VERSION 5.7 ;
  NOWIREEXTENSIONATPIN ON ;
  DIVIDERCHAR "/" ;
  BUSBITCHARS "[]" ;
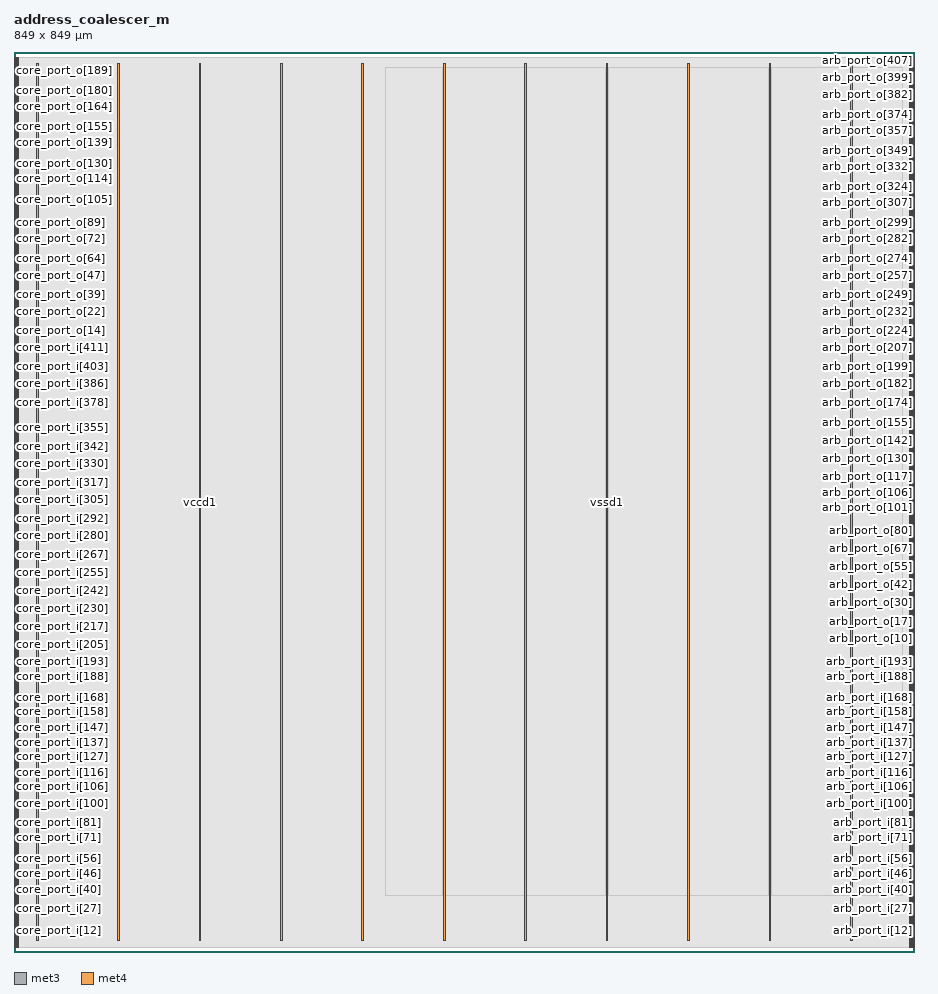
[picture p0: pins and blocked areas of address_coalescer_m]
MACRO address_coalescer_m
  CLASS BLOCK ;
  FOREIGN address_coalescer_m ;
  ORIGIN 0.000 0.000 ;
  SIZE 849.000 BY 849.000 ;
  PIN arb_port_i[0]
    DIRECTION INPUT ;
    USE SIGNAL ;
    ANTENNAGATEAREA 0.852000 ;
    PORT
      LAYER met3 ;
        RECT 845.000 4.120 849.000 4.720 ;
    END
  END arb_port_i[0]
  PIN arb_port_i[100]
    DIRECTION INPUT ;
    USE SIGNAL ;
    ANTENNAGATEAREA 0.426000 ;
    PORT
      LAYER met3 ;
        RECT 845.000 140.120 849.000 140.720 ;
    END
  END arb_port_i[100]
  PIN arb_port_i[101]
    DIRECTION INPUT ;
    USE SIGNAL ;
    ANTENNAGATEAREA 0.426000 ;
    PORT
      LAYER met3 ;
        RECT 845.000 141.480 849.000 142.080 ;
    END
  END arb_port_i[101]
  PIN arb_port_i[102]
    DIRECTION INPUT ;
    USE SIGNAL ;
    ANTENNAGATEAREA 0.426000 ;
    PORT
      LAYER met3 ;
        RECT 845.000 142.840 849.000 143.440 ;
    END
  END arb_port_i[102]
  PIN arb_port_i[103]
    DIRECTION INPUT ;
    USE SIGNAL ;
    ANTENNAGATEAREA 0.426000 ;
    PORT
      LAYER met3 ;
        RECT 845.000 144.200 849.000 144.800 ;
    END
  END arb_port_i[103]
  PIN arb_port_i[104]
    DIRECTION INPUT ;
    USE SIGNAL ;
    ANTENNAGATEAREA 0.426000 ;
    PORT
      LAYER met3 ;
        RECT 845.000 145.560 849.000 146.160 ;
    END
  END arb_port_i[104]
  PIN arb_port_i[105]
    DIRECTION INPUT ;
    USE SIGNAL ;
    ANTENNAGATEAREA 0.426000 ;
    PORT
      LAYER met3 ;
        RECT 845.000 146.920 849.000 147.520 ;
    END
  END arb_port_i[105]
  PIN arb_port_i[106]
    DIRECTION INPUT ;
    USE SIGNAL ;
    ANTENNAGATEAREA 0.426000 ;
    PORT
      LAYER met3 ;
        RECT 845.000 148.280 849.000 148.880 ;
    END
  END arb_port_i[106]
  PIN arb_port_i[107]
    DIRECTION INPUT ;
    USE SIGNAL ;
    ANTENNAGATEAREA 0.426000 ;
    PORT
      LAYER met3 ;
        RECT 845.000 149.640 849.000 150.240 ;
    END
  END arb_port_i[107]
  PIN arb_port_i[108]
    DIRECTION INPUT ;
    USE SIGNAL ;
    ANTENNAGATEAREA 0.426000 ;
    PORT
      LAYER met3 ;
        RECT 845.000 151.000 849.000 151.600 ;
    END
  END arb_port_i[108]
  PIN arb_port_i[109]
    DIRECTION INPUT ;
    USE SIGNAL ;
    ANTENNAGATEAREA 0.426000 ;
    PORT
      LAYER met3 ;
        RECT 845.000 152.360 849.000 152.960 ;
    END
  END arb_port_i[109]
  PIN arb_port_i[10]
    DIRECTION INPUT ;
    USE SIGNAL ;
    ANTENNAGATEAREA 0.852000 ;
    PORT
      LAYER met3 ;
        RECT 845.000 17.720 849.000 18.320 ;
    END
  END arb_port_i[10]
  PIN arb_port_i[110]
    DIRECTION INPUT ;
    USE SIGNAL ;
    ANTENNAGATEAREA 0.426000 ;
    PORT
      LAYER met3 ;
        RECT 845.000 153.720 849.000 154.320 ;
    END
  END arb_port_i[110]
  PIN arb_port_i[111]
    DIRECTION INPUT ;
    USE SIGNAL ;
    ANTENNAGATEAREA 0.426000 ;
    PORT
      LAYER met3 ;
        RECT 845.000 155.080 849.000 155.680 ;
    END
  END arb_port_i[111]
  PIN arb_port_i[112]
    DIRECTION INPUT ;
    USE SIGNAL ;
    ANTENNAGATEAREA 0.426000 ;
    PORT
      LAYER met3 ;
        RECT 845.000 156.440 849.000 157.040 ;
    END
  END arb_port_i[112]
  PIN arb_port_i[113]
    DIRECTION INPUT ;
    USE SIGNAL ;
    ANTENNAGATEAREA 0.426000 ;
    PORT
      LAYER met3 ;
        RECT 845.000 157.800 849.000 158.400 ;
    END
  END arb_port_i[113]
  PIN arb_port_i[114]
    DIRECTION INPUT ;
    USE SIGNAL ;
    ANTENNAGATEAREA 0.247500 ;
    PORT
      LAYER met3 ;
        RECT 845.000 159.160 849.000 159.760 ;
    END
  END arb_port_i[114]
  PIN arb_port_i[115]
    DIRECTION INPUT ;
    USE SIGNAL ;
    ANTENNAGATEAREA 0.247500 ;
    PORT
      LAYER met3 ;
        RECT 845.000 160.520 849.000 161.120 ;
    END
  END arb_port_i[115]
  PIN arb_port_i[116]
    DIRECTION INPUT ;
    USE SIGNAL ;
    ANTENNAGATEAREA 0.247500 ;
    PORT
      LAYER met3 ;
        RECT 845.000 161.880 849.000 162.480 ;
    END
  END arb_port_i[116]
  PIN arb_port_i[117]
    DIRECTION INPUT ;
    USE SIGNAL ;
    ANTENNAGATEAREA 0.426000 ;
    PORT
      LAYER met3 ;
        RECT 845.000 163.240 849.000 163.840 ;
    END
  END arb_port_i[117]
  PIN arb_port_i[118]
    DIRECTION INPUT ;
    USE SIGNAL ;
    ANTENNAGATEAREA 0.426000 ;
    PORT
      LAYER met3 ;
        RECT 845.000 164.600 849.000 165.200 ;
    END
  END arb_port_i[118]
  PIN arb_port_i[119]
    DIRECTION INPUT ;
    USE SIGNAL ;
    ANTENNAGATEAREA 0.426000 ;
    PORT
      LAYER met3 ;
        RECT 845.000 165.960 849.000 166.560 ;
    END
  END arb_port_i[119]
  PIN arb_port_i[11]
    DIRECTION INPUT ;
    USE SIGNAL ;
    ANTENNAGATEAREA 0.852000 ;
    PORT
      LAYER met3 ;
        RECT 845.000 19.080 849.000 19.680 ;
    END
  END arb_port_i[11]
  PIN arb_port_i[120]
    DIRECTION INPUT ;
    USE SIGNAL ;
    ANTENNAGATEAREA 0.426000 ;
    PORT
      LAYER met3 ;
        RECT 845.000 167.320 849.000 167.920 ;
    END
  END arb_port_i[120]
  PIN arb_port_i[121]
    DIRECTION INPUT ;
    USE SIGNAL ;
    ANTENNAGATEAREA 0.426000 ;
    PORT
      LAYER met3 ;
        RECT 845.000 168.680 849.000 169.280 ;
    END
  END arb_port_i[121]
  PIN arb_port_i[122]
    DIRECTION INPUT ;
    USE SIGNAL ;
    ANTENNAGATEAREA 0.426000 ;
    PORT
      LAYER met3 ;
        RECT 845.000 170.040 849.000 170.640 ;
    END
  END arb_port_i[122]
  PIN arb_port_i[123]
    DIRECTION INPUT ;
    USE SIGNAL ;
    ANTENNAGATEAREA 0.426000 ;
    PORT
      LAYER met3 ;
        RECT 845.000 171.400 849.000 172.000 ;
    END
  END arb_port_i[123]
  PIN arb_port_i[124]
    DIRECTION INPUT ;
    USE SIGNAL ;
    ANTENNAGATEAREA 0.426000 ;
    PORT
      LAYER met3 ;
        RECT 845.000 172.760 849.000 173.360 ;
    END
  END arb_port_i[124]
  PIN arb_port_i[125]
    DIRECTION INPUT ;
    USE SIGNAL ;
    ANTENNAGATEAREA 0.426000 ;
    PORT
      LAYER met3 ;
        RECT 845.000 174.120 849.000 174.720 ;
    END
  END arb_port_i[125]
  PIN arb_port_i[126]
    DIRECTION INPUT ;
    USE SIGNAL ;
    ANTENNAGATEAREA 0.426000 ;
    PORT
      LAYER met3 ;
        RECT 845.000 175.480 849.000 176.080 ;
    END
  END arb_port_i[126]
  PIN arb_port_i[127]
    DIRECTION INPUT ;
    USE SIGNAL ;
    ANTENNAGATEAREA 0.426000 ;
    PORT
      LAYER met3 ;
        RECT 845.000 176.840 849.000 177.440 ;
    END
  END arb_port_i[127]
  PIN arb_port_i[128]
    DIRECTION INPUT ;
    USE SIGNAL ;
    ANTENNAGATEAREA 0.426000 ;
    PORT
      LAYER met3 ;
        RECT 845.000 178.200 849.000 178.800 ;
    END
  END arb_port_i[128]
  PIN arb_port_i[129]
    DIRECTION INPUT ;
    USE SIGNAL ;
    ANTENNAGATEAREA 0.426000 ;
    PORT
      LAYER met3 ;
        RECT 845.000 179.560 849.000 180.160 ;
    END
  END arb_port_i[129]
  PIN arb_port_i[12]
    DIRECTION INPUT ;
    USE SIGNAL ;
    ANTENNAGATEAREA 0.852000 ;
    PORT
      LAYER met3 ;
        RECT 845.000 20.440 849.000 21.040 ;
    END
  END arb_port_i[12]
  PIN arb_port_i[130]
    DIRECTION INPUT ;
    USE SIGNAL ;
    ANTENNAGATEAREA 0.426000 ;
    PORT
      LAYER met3 ;
        RECT 845.000 180.920 849.000 181.520 ;
    END
  END arb_port_i[130]
  PIN arb_port_i[131]
    DIRECTION INPUT ;
    USE SIGNAL ;
    ANTENNAGATEAREA 0.426000 ;
    PORT
      LAYER met3 ;
        RECT 845.000 182.280 849.000 182.880 ;
    END
  END arb_port_i[131]
  PIN arb_port_i[132]
    DIRECTION INPUT ;
    USE SIGNAL ;
    ANTENNAGATEAREA 0.426000 ;
    PORT
      LAYER met3 ;
        RECT 845.000 183.640 849.000 184.240 ;
    END
  END arb_port_i[132]
  PIN arb_port_i[133]
    DIRECTION INPUT ;
    USE SIGNAL ;
    ANTENNAGATEAREA 0.426000 ;
    PORT
      LAYER met3 ;
        RECT 845.000 185.000 849.000 185.600 ;
    END
  END arb_port_i[133]
  PIN arb_port_i[134]
    DIRECTION INPUT ;
    USE SIGNAL ;
    ANTENNAGATEAREA 0.426000 ;
    PORT
      LAYER met3 ;
        RECT 845.000 186.360 849.000 186.960 ;
    END
  END arb_port_i[134]
  PIN arb_port_i[135]
    DIRECTION INPUT ;
    USE SIGNAL ;
    ANTENNAGATEAREA 0.426000 ;
    PORT
      LAYER met3 ;
        RECT 845.000 187.720 849.000 188.320 ;
    END
  END arb_port_i[135]
  PIN arb_port_i[136]
    DIRECTION INPUT ;
    USE SIGNAL ;
    ANTENNAGATEAREA 0.426000 ;
    PORT
      LAYER met3 ;
        RECT 845.000 189.080 849.000 189.680 ;
    END
  END arb_port_i[136]
  PIN arb_port_i[137]
    DIRECTION INPUT ;
    USE SIGNAL ;
    ANTENNAGATEAREA 0.426000 ;
    PORT
      LAYER met3 ;
        RECT 845.000 190.440 849.000 191.040 ;
    END
  END arb_port_i[137]
  PIN arb_port_i[138]
    DIRECTION INPUT ;
    USE SIGNAL ;
    ANTENNAGATEAREA 0.426000 ;
    PORT
      LAYER met3 ;
        RECT 845.000 191.800 849.000 192.400 ;
    END
  END arb_port_i[138]
  PIN arb_port_i[139]
    DIRECTION INPUT ;
    USE SIGNAL ;
    ANTENNAGATEAREA 0.426000 ;
    PORT
      LAYER met3 ;
        RECT 845.000 193.160 849.000 193.760 ;
    END
  END arb_port_i[139]
  PIN arb_port_i[13]
    DIRECTION INPUT ;
    USE SIGNAL ;
    ANTENNAGATEAREA 0.852000 ;
    PORT
      LAYER met3 ;
        RECT 845.000 21.800 849.000 22.400 ;
    END
  END arb_port_i[13]
  PIN arb_port_i[140]
    DIRECTION INPUT ;
    USE SIGNAL ;
    ANTENNAGATEAREA 0.426000 ;
    PORT
      LAYER met3 ;
        RECT 845.000 194.520 849.000 195.120 ;
    END
  END arb_port_i[140]
  PIN arb_port_i[141]
    DIRECTION INPUT ;
    USE SIGNAL ;
    ANTENNAGATEAREA 0.426000 ;
    PORT
      LAYER met3 ;
        RECT 845.000 195.880 849.000 196.480 ;
    END
  END arb_port_i[141]
  PIN arb_port_i[142]
    DIRECTION INPUT ;
    USE SIGNAL ;
    ANTENNAGATEAREA 0.426000 ;
    PORT
      LAYER met3 ;
        RECT 845.000 197.240 849.000 197.840 ;
    END
  END arb_port_i[142]
  PIN arb_port_i[143]
    DIRECTION INPUT ;
    USE SIGNAL ;
    ANTENNAGATEAREA 0.426000 ;
    PORT
      LAYER met3 ;
        RECT 845.000 198.600 849.000 199.200 ;
    END
  END arb_port_i[143]
  PIN arb_port_i[144]
    DIRECTION INPUT ;
    USE SIGNAL ;
    ANTENNAGATEAREA 0.426000 ;
    PORT
      LAYER met3 ;
        RECT 845.000 199.960 849.000 200.560 ;
    END
  END arb_port_i[144]
  PIN arb_port_i[145]
    DIRECTION INPUT ;
    USE SIGNAL ;
    ANTENNAGATEAREA 0.426000 ;
    PORT
      LAYER met3 ;
        RECT 845.000 201.320 849.000 201.920 ;
    END
  END arb_port_i[145]
  PIN arb_port_i[146]
    DIRECTION INPUT ;
    USE SIGNAL ;
    ANTENNAGATEAREA 0.426000 ;
    PORT
      LAYER met3 ;
        RECT 845.000 202.680 849.000 203.280 ;
    END
  END arb_port_i[146]
  PIN arb_port_i[147]
    DIRECTION INPUT ;
    USE SIGNAL ;
    ANTENNAGATEAREA 0.426000 ;
    PORT
      LAYER met3 ;
        RECT 845.000 204.040 849.000 204.640 ;
    END
  END arb_port_i[147]
  PIN arb_port_i[148]
    DIRECTION INPUT ;
    USE SIGNAL ;
    ANTENNAGATEAREA 0.426000 ;
    PORT
      LAYER met3 ;
        RECT 845.000 205.400 849.000 206.000 ;
    END
  END arb_port_i[148]
  PIN arb_port_i[149]
    DIRECTION INPUT ;
    USE SIGNAL ;
    ANTENNAGATEAREA 0.426000 ;
    PORT
      LAYER met3 ;
        RECT 845.000 206.760 849.000 207.360 ;
    END
  END arb_port_i[149]
  PIN arb_port_i[14]
    DIRECTION INPUT ;
    USE SIGNAL ;
    ANTENNAGATEAREA 0.852000 ;
    PORT
      LAYER met3 ;
        RECT 845.000 23.160 849.000 23.760 ;
    END
  END arb_port_i[14]
  PIN arb_port_i[150]
    DIRECTION INPUT ;
    USE SIGNAL ;
    ANTENNAGATEAREA 0.426000 ;
    PORT
      LAYER met3 ;
        RECT 845.000 208.120 849.000 208.720 ;
    END
  END arb_port_i[150]
  PIN arb_port_i[151]
    DIRECTION INPUT ;
    USE SIGNAL ;
    ANTENNAGATEAREA 0.426000 ;
    PORT
      LAYER met3 ;
        RECT 845.000 209.480 849.000 210.080 ;
    END
  END arb_port_i[151]
  PIN arb_port_i[152]
    DIRECTION INPUT ;
    USE SIGNAL ;
    ANTENNAGATEAREA 0.426000 ;
    PORT
      LAYER met3 ;
        RECT 845.000 210.840 849.000 211.440 ;
    END
  END arb_port_i[152]
  PIN arb_port_i[153]
    DIRECTION INPUT ;
    USE SIGNAL ;
    ANTENNAGATEAREA 0.426000 ;
    PORT
      LAYER met3 ;
        RECT 845.000 212.200 849.000 212.800 ;
    END
  END arb_port_i[153]
  PIN arb_port_i[154]
    DIRECTION INPUT ;
    USE SIGNAL ;
    ANTENNAGATEAREA 0.426000 ;
    PORT
      LAYER met3 ;
        RECT 845.000 213.560 849.000 214.160 ;
    END
  END arb_port_i[154]
  PIN arb_port_i[155]
    DIRECTION INPUT ;
    USE SIGNAL ;
    ANTENNAGATEAREA 0.426000 ;
    PORT
      LAYER met3 ;
        RECT 845.000 214.920 849.000 215.520 ;
    END
  END arb_port_i[155]
  PIN arb_port_i[156]
    DIRECTION INPUT ;
    USE SIGNAL ;
    ANTENNAGATEAREA 0.426000 ;
    PORT
      LAYER met3 ;
        RECT 845.000 216.280 849.000 216.880 ;
    END
  END arb_port_i[156]
  PIN arb_port_i[157]
    DIRECTION INPUT ;
    USE SIGNAL ;
    ANTENNAGATEAREA 0.426000 ;
    PORT
      LAYER met3 ;
        RECT 845.000 217.640 849.000 218.240 ;
    END
  END arb_port_i[157]
  PIN arb_port_i[158]
    DIRECTION INPUT ;
    USE SIGNAL ;
    ANTENNAGATEAREA 0.426000 ;
    PORT
      LAYER met3 ;
        RECT 845.000 219.000 849.000 219.600 ;
    END
  END arb_port_i[158]
  PIN arb_port_i[159]
    DIRECTION INPUT ;
    USE SIGNAL ;
    ANTENNAGATEAREA 0.426000 ;
    PORT
      LAYER met3 ;
        RECT 845.000 220.360 849.000 220.960 ;
    END
  END arb_port_i[159]
  PIN arb_port_i[15]
    DIRECTION INPUT ;
    USE SIGNAL ;
    ANTENNAGATEAREA 0.852000 ;
    PORT
      LAYER met3 ;
        RECT 845.000 24.520 849.000 25.120 ;
    END
  END arb_port_i[15]
  PIN arb_port_i[160]
    DIRECTION INPUT ;
    USE SIGNAL ;
    ANTENNAGATEAREA 0.426000 ;
    PORT
      LAYER met3 ;
        RECT 845.000 221.720 849.000 222.320 ;
    END
  END arb_port_i[160]
  PIN arb_port_i[161]
    DIRECTION INPUT ;
    USE SIGNAL ;
    ANTENNAGATEAREA 0.426000 ;
    PORT
      LAYER met3 ;
        RECT 845.000 223.080 849.000 223.680 ;
    END
  END arb_port_i[161]
  PIN arb_port_i[162]
    DIRECTION INPUT ;
    USE SIGNAL ;
    ANTENNAGATEAREA 0.426000 ;
    PORT
      LAYER met3 ;
        RECT 845.000 224.440 849.000 225.040 ;
    END
  END arb_port_i[162]
  PIN arb_port_i[163]
    DIRECTION INPUT ;
    USE SIGNAL ;
    ANTENNAGATEAREA 0.426000 ;
    PORT
      LAYER met3 ;
        RECT 845.000 225.800 849.000 226.400 ;
    END
  END arb_port_i[163]
  PIN arb_port_i[164]
    DIRECTION INPUT ;
    USE SIGNAL ;
    ANTENNAGATEAREA 0.426000 ;
    PORT
      LAYER met3 ;
        RECT 845.000 227.160 849.000 227.760 ;
    END
  END arb_port_i[164]
  PIN arb_port_i[165]
    DIRECTION INPUT ;
    USE SIGNAL ;
    ANTENNAGATEAREA 0.247500 ;
    PORT
      LAYER met3 ;
        RECT 845.000 228.520 849.000 229.120 ;
    END
  END arb_port_i[165]
  PIN arb_port_i[166]
    DIRECTION INPUT ;
    USE SIGNAL ;
    ANTENNAGATEAREA 0.247500 ;
    PORT
      LAYER met3 ;
        RECT 845.000 229.880 849.000 230.480 ;
    END
  END arb_port_i[166]
  PIN arb_port_i[167]
    DIRECTION INPUT ;
    USE SIGNAL ;
    ANTENNAGATEAREA 0.247500 ;
    PORT
      LAYER met3 ;
        RECT 845.000 231.240 849.000 231.840 ;
    END
  END arb_port_i[167]
  PIN arb_port_i[168]
    DIRECTION INPUT ;
    USE SIGNAL ;
    ANTENNAGATEAREA 0.247500 ;
    PORT
      LAYER met3 ;
        RECT 845.000 232.600 849.000 233.200 ;
    END
  END arb_port_i[168]
  PIN arb_port_i[169]
    DIRECTION INPUT ;
    USE SIGNAL ;
    ANTENNAGATEAREA 0.247500 ;
    PORT
      LAYER met3 ;
        RECT 845.000 233.960 849.000 234.560 ;
    END
  END arb_port_i[169]
  PIN arb_port_i[16]
    DIRECTION INPUT ;
    USE SIGNAL ;
    ANTENNAGATEAREA 0.742500 ;
    PORT
      LAYER met3 ;
        RECT 845.000 25.880 849.000 26.480 ;
    END
  END arb_port_i[16]
  PIN arb_port_i[170]
    DIRECTION INPUT ;
    USE SIGNAL ;
    ANTENNAGATEAREA 0.247500 ;
    PORT
      LAYER met3 ;
        RECT 845.000 235.320 849.000 235.920 ;
    END
  END arb_port_i[170]
  PIN arb_port_i[171]
    DIRECTION INPUT ;
    USE SIGNAL ;
    ANTENNAGATEAREA 0.426000 ;
    PORT
      LAYER met3 ;
        RECT 845.000 236.680 849.000 237.280 ;
    END
  END arb_port_i[171]
  PIN arb_port_i[172]
    DIRECTION INPUT ;
    USE SIGNAL ;
    ANTENNAGATEAREA 0.426000 ;
    PORT
      LAYER met3 ;
        RECT 845.000 238.040 849.000 238.640 ;
    END
  END arb_port_i[172]
  PIN arb_port_i[173]
    DIRECTION INPUT ;
    USE SIGNAL ;
    ANTENNAGATEAREA 0.426000 ;
    PORT
      LAYER met3 ;
        RECT 845.000 239.400 849.000 240.000 ;
    END
  END arb_port_i[173]
  PIN arb_port_i[174]
    DIRECTION INPUT ;
    USE SIGNAL ;
    ANTENNAGATEAREA 0.247500 ;
    PORT
      LAYER met3 ;
        RECT 845.000 240.760 849.000 241.360 ;
    END
  END arb_port_i[174]
  PIN arb_port_i[175]
    DIRECTION INPUT ;
    USE SIGNAL ;
    ANTENNAGATEAREA 0.247500 ;
    PORT
      LAYER met3 ;
        RECT 845.000 242.120 849.000 242.720 ;
    END
  END arb_port_i[175]
  PIN arb_port_i[176]
    DIRECTION INPUT ;
    USE SIGNAL ;
    ANTENNAGATEAREA 0.247500 ;
    PORT
      LAYER met3 ;
        RECT 845.000 243.480 849.000 244.080 ;
    END
  END arb_port_i[176]
  PIN arb_port_i[177]
    DIRECTION INPUT ;
    USE SIGNAL ;
    ANTENNAGATEAREA 0.247500 ;
    PORT
      LAYER met3 ;
        RECT 845.000 244.840 849.000 245.440 ;
    END
  END arb_port_i[177]
  PIN arb_port_i[178]
    DIRECTION INPUT ;
    USE SIGNAL ;
    ANTENNAGATEAREA 0.426000 ;
    PORT
      LAYER met3 ;
        RECT 845.000 246.200 849.000 246.800 ;
    END
  END arb_port_i[178]
  PIN arb_port_i[179]
    DIRECTION INPUT ;
    USE SIGNAL ;
    ANTENNAGATEAREA 0.426000 ;
    PORT
      LAYER met3 ;
        RECT 845.000 247.560 849.000 248.160 ;
    END
  END arb_port_i[179]
  PIN arb_port_i[17]
    DIRECTION INPUT ;
    USE SIGNAL ;
    ANTENNAGATEAREA 0.852000 ;
    PORT
      LAYER met3 ;
        RECT 845.000 27.240 849.000 27.840 ;
    END
  END arb_port_i[17]
  PIN arb_port_i[180]
    DIRECTION INPUT ;
    USE SIGNAL ;
    ANTENNAGATEAREA 0.247500 ;
    PORT
      LAYER met3 ;
        RECT 845.000 248.920 849.000 249.520 ;
    END
  END arb_port_i[180]
  PIN arb_port_i[181]
    DIRECTION INPUT ;
    USE SIGNAL ;
    ANTENNAGATEAREA 0.247500 ;
    PORT
      LAYER met3 ;
        RECT 845.000 250.280 849.000 250.880 ;
    END
  END arb_port_i[181]
  PIN arb_port_i[182]
    DIRECTION INPUT ;
    USE SIGNAL ;
    ANTENNAGATEAREA 0.247500 ;
    PORT
      LAYER met3 ;
        RECT 845.000 251.640 849.000 252.240 ;
    END
  END arb_port_i[182]
  PIN arb_port_i[183]
    DIRECTION INPUT ;
    USE SIGNAL ;
    ANTENNAGATEAREA 0.247500 ;
    PORT
      LAYER met3 ;
        RECT 845.000 253.000 849.000 253.600 ;
    END
  END arb_port_i[183]
  PIN arb_port_i[184]
    DIRECTION INPUT ;
    USE SIGNAL ;
    ANTENNAGATEAREA 0.247500 ;
    PORT
      LAYER met3 ;
        RECT 845.000 254.360 849.000 254.960 ;
    END
  END arb_port_i[184]
  PIN arb_port_i[185]
    DIRECTION INPUT ;
    USE SIGNAL ;
    ANTENNAGATEAREA 0.247500 ;
    PORT
      LAYER met3 ;
        RECT 845.000 255.720 849.000 256.320 ;
    END
  END arb_port_i[185]
  PIN arb_port_i[186]
    DIRECTION INPUT ;
    USE SIGNAL ;
    ANTENNAGATEAREA 0.247500 ;
    PORT
      LAYER met3 ;
        RECT 845.000 257.080 849.000 257.680 ;
    END
  END arb_port_i[186]
  PIN arb_port_i[187]
    DIRECTION INPUT ;
    USE SIGNAL ;
    ANTENNAGATEAREA 0.247500 ;
    PORT
      LAYER met3 ;
        RECT 845.000 258.440 849.000 259.040 ;
    END
  END arb_port_i[187]
  PIN arb_port_i[188]
    DIRECTION INPUT ;
    USE SIGNAL ;
    ANTENNAGATEAREA 0.426000 ;
    PORT
      LAYER met3 ;
        RECT 845.000 259.800 849.000 260.400 ;
    END
  END arb_port_i[188]
  PIN arb_port_i[189]
    DIRECTION INPUT ;
    USE SIGNAL ;
    ANTENNAGATEAREA 0.247500 ;
    PORT
      LAYER met3 ;
        RECT 845.000 261.160 849.000 261.760 ;
    END
  END arb_port_i[189]
  PIN arb_port_i[18]
    DIRECTION INPUT ;
    USE SIGNAL ;
    ANTENNAGATEAREA 0.742500 ;
    PORT
      LAYER met3 ;
        RECT 845.000 28.600 849.000 29.200 ;
    END
  END arb_port_i[18]
  PIN arb_port_i[190]
    DIRECTION INPUT ;
    USE SIGNAL ;
    ANTENNAGATEAREA 0.426000 ;
    PORT
      LAYER met3 ;
        RECT 845.000 262.520 849.000 263.120 ;
    END
  END arb_port_i[190]
  PIN arb_port_i[191]
    DIRECTION INPUT ;
    USE SIGNAL ;
    ANTENNAGATEAREA 0.426000 ;
    PORT
      LAYER met3 ;
        RECT 845.000 263.880 849.000 264.480 ;
    END
  END arb_port_i[191]
  PIN arb_port_i[192]
    DIRECTION INPUT ;
    USE SIGNAL ;
    ANTENNAGATEAREA 0.247500 ;
    PORT
      LAYER met3 ;
        RECT 845.000 265.240 849.000 265.840 ;
    END
  END arb_port_i[192]
  PIN arb_port_i[193]
    DIRECTION INPUT ;
    USE SIGNAL ;
    ANTENNAGATEAREA 0.426000 ;
    PORT
      LAYER met3 ;
        RECT 845.000 266.600 849.000 267.200 ;
    END
  END arb_port_i[193]
  PIN arb_port_i[194]
    DIRECTION INPUT ;
    USE SIGNAL ;
    ANTENNAGATEAREA 0.247500 ;
    PORT
      LAYER met3 ;
        RECT 845.000 267.960 849.000 268.560 ;
    END
  END arb_port_i[194]
  PIN arb_port_i[195]
    DIRECTION INPUT ;
    USE SIGNAL ;
    ANTENNAGATEAREA 0.426000 ;
    PORT
      LAYER met3 ;
        RECT 845.000 269.320 849.000 269.920 ;
    END
  END arb_port_i[195]
  PIN arb_port_i[196]
    DIRECTION INPUT ;
    USE SIGNAL ;
    ANTENNAGATEAREA 0.247500 ;
    PORT
      LAYER met3 ;
        RECT 845.000 270.680 849.000 271.280 ;
    END
  END arb_port_i[196]
  PIN arb_port_i[197]
    DIRECTION INPUT ;
    USE SIGNAL ;
    ANTENNAGATEAREA 0.426000 ;
    PORT
      LAYER met3 ;
        RECT 845.000 272.040 849.000 272.640 ;
    END
  END arb_port_i[197]
  PIN arb_port_i[198]
    DIRECTION INPUT ;
    USE SIGNAL ;
    ANTENNAGATEAREA 0.247500 ;
    PORT
      LAYER met3 ;
        RECT 845.000 273.400 849.000 274.000 ;
    END
  END arb_port_i[198]
  PIN arb_port_i[199]
    DIRECTION INPUT ;
    USE SIGNAL ;
    ANTENNAGATEAREA 0.247500 ;
    PORT
      LAYER met3 ;
        RECT 845.000 274.760 849.000 275.360 ;
    END
  END arb_port_i[199]
  PIN arb_port_i[19]
    DIRECTION INPUT ;
    USE SIGNAL ;
    ANTENNAGATEAREA 0.852000 ;
    PORT
      LAYER met3 ;
        RECT 845.000 29.960 849.000 30.560 ;
    END
  END arb_port_i[19]
  PIN arb_port_i[1]
    DIRECTION INPUT ;
    USE SIGNAL ;
    ANTENNAGATEAREA 0.742500 ;
    PORT
      LAYER met3 ;
        RECT 845.000 5.480 849.000 6.080 ;
    END
  END arb_port_i[1]
  PIN arb_port_i[200]
    DIRECTION INPUT ;
    USE SIGNAL ;
    ANTENNAGATEAREA 0.247500 ;
    PORT
      LAYER met3 ;
        RECT 845.000 276.120 849.000 276.720 ;
    END
  END arb_port_i[200]
  PIN arb_port_i[201]
    DIRECTION INPUT ;
    USE SIGNAL ;
    ANTENNAGATEAREA 0.247500 ;
    PORT
      LAYER met3 ;
        RECT 845.000 277.480 849.000 278.080 ;
    END
  END arb_port_i[201]
  PIN arb_port_i[202]
    DIRECTION INPUT ;
    USE SIGNAL ;
    ANTENNAGATEAREA 0.247500 ;
    PORT
      LAYER met3 ;
        RECT 845.000 278.840 849.000 279.440 ;
    END
  END arb_port_i[202]
  PIN arb_port_i[203]
    DIRECTION INPUT ;
    USE SIGNAL ;
    ANTENNAGATEAREA 0.247500 ;
    PORT
      LAYER met3 ;
        RECT 845.000 280.200 849.000 280.800 ;
    END
  END arb_port_i[203]
  PIN arb_port_i[20]
    DIRECTION INPUT ;
    USE SIGNAL ;
    ANTENNAGATEAREA 0.742500 ;
    PORT
      LAYER met3 ;
        RECT 845.000 31.320 849.000 31.920 ;
    END
  END arb_port_i[20]
  PIN arb_port_i[21]
    DIRECTION INPUT ;
    USE SIGNAL ;
    ANTENNAGATEAREA 0.852000 ;
    PORT
      LAYER met3 ;
        RECT 845.000 32.680 849.000 33.280 ;
    END
  END arb_port_i[21]
  PIN arb_port_i[22]
    DIRECTION INPUT ;
    USE SIGNAL ;
    ANTENNAGATEAREA 0.852000 ;
    PORT
      LAYER met3 ;
        RECT 845.000 34.040 849.000 34.640 ;
    END
  END arb_port_i[22]
  PIN arb_port_i[23]
    DIRECTION INPUT ;
    USE SIGNAL ;
    ANTENNAGATEAREA 0.852000 ;
    PORT
      LAYER met3 ;
        RECT 845.000 35.400 849.000 36.000 ;
    END
  END arb_port_i[23]
  PIN arb_port_i[24]
    DIRECTION INPUT ;
    USE SIGNAL ;
    ANTENNAGATEAREA 0.852000 ;
    PORT
      LAYER met3 ;
        RECT 845.000 36.760 849.000 37.360 ;
    END
  END arb_port_i[24]
  PIN arb_port_i[25]
    DIRECTION INPUT ;
    USE SIGNAL ;
    ANTENNAGATEAREA 0.852000 ;
    PORT
      LAYER met3 ;
        RECT 845.000 38.120 849.000 38.720 ;
    END
  END arb_port_i[25]
  PIN arb_port_i[26]
    DIRECTION INPUT ;
    USE SIGNAL ;
    ANTENNAGATEAREA 0.742500 ;
    PORT
      LAYER met3 ;
        RECT 845.000 39.480 849.000 40.080 ;
    END
  END arb_port_i[26]
  PIN arb_port_i[27]
    DIRECTION INPUT ;
    USE SIGNAL ;
    ANTENNAGATEAREA 0.852000 ;
    PORT
      LAYER met3 ;
        RECT 845.000 40.840 849.000 41.440 ;
    END
  END arb_port_i[27]
  PIN arb_port_i[28]
    DIRECTION INPUT ;
    USE SIGNAL ;
    ANTENNAGATEAREA 0.852000 ;
    PORT
      LAYER met3 ;
        RECT 845.000 42.200 849.000 42.800 ;
    END
  END arb_port_i[28]
  PIN arb_port_i[29]
    DIRECTION INPUT ;
    USE SIGNAL ;
    ANTENNAGATEAREA 0.742500 ;
    PORT
      LAYER met3 ;
        RECT 845.000 43.560 849.000 44.160 ;
    END
  END arb_port_i[29]
  PIN arb_port_i[2]
    DIRECTION INPUT ;
    USE SIGNAL ;
    ANTENNAGATEAREA 0.742500 ;
    PORT
      LAYER met3 ;
        RECT 845.000 6.840 849.000 7.440 ;
    END
  END arb_port_i[2]
  PIN arb_port_i[30]
    DIRECTION INPUT ;
    USE SIGNAL ;
    ANTENNAGATEAREA 0.742500 ;
    PORT
      LAYER met3 ;
        RECT 845.000 44.920 849.000 45.520 ;
    END
  END arb_port_i[30]
  PIN arb_port_i[31]
    DIRECTION INPUT ;
    USE SIGNAL ;
    ANTENNAGATEAREA 0.742500 ;
    PORT
      LAYER met3 ;
        RECT 845.000 46.280 849.000 46.880 ;
    END
  END arb_port_i[31]
  PIN arb_port_i[32]
    DIRECTION INPUT ;
    USE SIGNAL ;
    ANTENNAGATEAREA 0.742500 ;
    PORT
      LAYER met3 ;
        RECT 845.000 47.640 849.000 48.240 ;
    END
  END arb_port_i[32]
  PIN arb_port_i[33]
    DIRECTION INPUT ;
    USE SIGNAL ;
    ANTENNAGATEAREA 0.742500 ;
    PORT
      LAYER met3 ;
        RECT 845.000 49.000 849.000 49.600 ;
    END
  END arb_port_i[33]
  PIN arb_port_i[34]
    DIRECTION INPUT ;
    USE SIGNAL ;
    ANTENNAGATEAREA 0.426000 ;
    PORT
      LAYER met3 ;
        RECT 845.000 50.360 849.000 50.960 ;
    END
  END arb_port_i[34]
  PIN arb_port_i[35]
    DIRECTION INPUT ;
    USE SIGNAL ;
    ANTENNAGATEAREA 0.426000 ;
    PORT
      LAYER met3 ;
        RECT 845.000 51.720 849.000 52.320 ;
    END
  END arb_port_i[35]
  PIN arb_port_i[36]
    DIRECTION INPUT ;
    USE SIGNAL ;
    ANTENNAGATEAREA 0.426000 ;
    PORT
      LAYER met3 ;
        RECT 845.000 53.080 849.000 53.680 ;
    END
  END arb_port_i[36]
  PIN arb_port_i[37]
    DIRECTION INPUT ;
    USE SIGNAL ;
    ANTENNAGATEAREA 0.426000 ;
    PORT
      LAYER met3 ;
        RECT 845.000 54.440 849.000 55.040 ;
    END
  END arb_port_i[37]
  PIN arb_port_i[38]
    DIRECTION INPUT ;
    USE SIGNAL ;
    ANTENNAGATEAREA 0.426000 ;
    PORT
      LAYER met3 ;
        RECT 845.000 55.800 849.000 56.400 ;
    END
  END arb_port_i[38]
  PIN arb_port_i[39]
    DIRECTION INPUT ;
    USE SIGNAL ;
    ANTENNAGATEAREA 0.426000 ;
    PORT
      LAYER met3 ;
        RECT 845.000 57.160 849.000 57.760 ;
    END
  END arb_port_i[39]
  PIN arb_port_i[3]
    DIRECTION INPUT ;
    USE SIGNAL ;
    ANTENNAGATEAREA 0.742500 ;
    PORT
      LAYER met3 ;
        RECT 845.000 8.200 849.000 8.800 ;
    END
  END arb_port_i[3]
  PIN arb_port_i[40]
    DIRECTION INPUT ;
    USE SIGNAL ;
    ANTENNAGATEAREA 0.426000 ;
    PORT
      LAYER met3 ;
        RECT 845.000 58.520 849.000 59.120 ;
    END
  END arb_port_i[40]
  PIN arb_port_i[41]
    DIRECTION INPUT ;
    USE SIGNAL ;
    ANTENNAGATEAREA 0.426000 ;
    PORT
      LAYER met3 ;
        RECT 845.000 59.880 849.000 60.480 ;
    END
  END arb_port_i[41]
  PIN arb_port_i[42]
    DIRECTION INPUT ;
    USE SIGNAL ;
    ANTENNAGATEAREA 0.426000 ;
    PORT
      LAYER met3 ;
        RECT 845.000 61.240 849.000 61.840 ;
    END
  END arb_port_i[42]
  PIN arb_port_i[43]
    DIRECTION INPUT ;
    USE SIGNAL ;
    ANTENNAGATEAREA 0.426000 ;
    PORT
      LAYER met3 ;
        RECT 845.000 62.600 849.000 63.200 ;
    END
  END arb_port_i[43]
  PIN arb_port_i[44]
    DIRECTION INPUT ;
    USE SIGNAL ;
    ANTENNAGATEAREA 0.426000 ;
    PORT
      LAYER met3 ;
        RECT 845.000 63.960 849.000 64.560 ;
    END
  END arb_port_i[44]
  PIN arb_port_i[45]
    DIRECTION INPUT ;
    USE SIGNAL ;
    ANTENNAGATEAREA 0.426000 ;
    PORT
      LAYER met3 ;
        RECT 845.000 65.320 849.000 65.920 ;
    END
  END arb_port_i[45]
  PIN arb_port_i[46]
    DIRECTION INPUT ;
    USE SIGNAL ;
    ANTENNAGATEAREA 0.426000 ;
    PORT
      LAYER met3 ;
        RECT 845.000 66.680 849.000 67.280 ;
    END
  END arb_port_i[46]
  PIN arb_port_i[47]
    DIRECTION INPUT ;
    USE SIGNAL ;
    ANTENNAGATEAREA 0.426000 ;
    PORT
      LAYER met3 ;
        RECT 845.000 68.040 849.000 68.640 ;
    END
  END arb_port_i[47]
  PIN arb_port_i[48]
    DIRECTION INPUT ;
    USE SIGNAL ;
    ANTENNAGATEAREA 0.426000 ;
    PORT
      LAYER met3 ;
        RECT 845.000 69.400 849.000 70.000 ;
    END
  END arb_port_i[48]
  PIN arb_port_i[49]
    DIRECTION INPUT ;
    USE SIGNAL ;
    ANTENNAGATEAREA 0.426000 ;
    PORT
      LAYER met3 ;
        RECT 845.000 70.760 849.000 71.360 ;
    END
  END arb_port_i[49]
  PIN arb_port_i[4]
    DIRECTION INPUT ;
    USE SIGNAL ;
    ANTENNAGATEAREA 0.742500 ;
    PORT
      LAYER met3 ;
        RECT 845.000 9.560 849.000 10.160 ;
    END
  END arb_port_i[4]
  PIN arb_port_i[50]
    DIRECTION INPUT ;
    USE SIGNAL ;
    ANTENNAGATEAREA 0.426000 ;
    PORT
      LAYER met3 ;
        RECT 845.000 72.120 849.000 72.720 ;
    END
  END arb_port_i[50]
  PIN arb_port_i[51]
    DIRECTION INPUT ;
    USE SIGNAL ;
    ANTENNAGATEAREA 0.426000 ;
    PORT
      LAYER met3 ;
        RECT 845.000 73.480 849.000 74.080 ;
    END
  END arb_port_i[51]
  PIN arb_port_i[52]
    DIRECTION INPUT ;
    USE SIGNAL ;
    ANTENNAGATEAREA 0.426000 ;
    PORT
      LAYER met3 ;
        RECT 845.000 74.840 849.000 75.440 ;
    END
  END arb_port_i[52]
  PIN arb_port_i[53]
    DIRECTION INPUT ;
    USE SIGNAL ;
    ANTENNAGATEAREA 0.426000 ;
    PORT
      LAYER met3 ;
        RECT 845.000 76.200 849.000 76.800 ;
    END
  END arb_port_i[53]
  PIN arb_port_i[54]
    DIRECTION INPUT ;
    USE SIGNAL ;
    ANTENNAGATEAREA 0.426000 ;
    PORT
      LAYER met3 ;
        RECT 845.000 77.560 849.000 78.160 ;
    END
  END arb_port_i[54]
  PIN arb_port_i[55]
    DIRECTION INPUT ;
    USE SIGNAL ;
    ANTENNAGATEAREA 0.426000 ;
    PORT
      LAYER met3 ;
        RECT 845.000 78.920 849.000 79.520 ;
    END
  END arb_port_i[55]
  PIN arb_port_i[56]
    DIRECTION INPUT ;
    USE SIGNAL ;
    ANTENNAGATEAREA 0.426000 ;
    PORT
      LAYER met3 ;
        RECT 845.000 80.280 849.000 80.880 ;
    END
  END arb_port_i[56]
  PIN arb_port_i[57]
    DIRECTION INPUT ;
    USE SIGNAL ;
    ANTENNAGATEAREA 0.426000 ;
    PORT
      LAYER met3 ;
        RECT 845.000 81.640 849.000 82.240 ;
    END
  END arb_port_i[57]
  PIN arb_port_i[58]
    DIRECTION INPUT ;
    USE SIGNAL ;
    ANTENNAGATEAREA 0.426000 ;
    PORT
      LAYER met3 ;
        RECT 845.000 83.000 849.000 83.600 ;
    END
  END arb_port_i[58]
  PIN arb_port_i[59]
    DIRECTION INPUT ;
    USE SIGNAL ;
    ANTENNAGATEAREA 0.426000 ;
    PORT
      LAYER met3 ;
        RECT 845.000 84.360 849.000 84.960 ;
    END
  END arb_port_i[59]
  PIN arb_port_i[5]
    DIRECTION INPUT ;
    USE SIGNAL ;
    ANTENNAGATEAREA 0.742500 ;
    PORT
      LAYER met3 ;
        RECT 845.000 10.920 849.000 11.520 ;
    END
  END arb_port_i[5]
  PIN arb_port_i[60]
    DIRECTION INPUT ;
    USE SIGNAL ;
    ANTENNAGATEAREA 0.426000 ;
    PORT
      LAYER met3 ;
        RECT 845.000 85.720 849.000 86.320 ;
    END
  END arb_port_i[60]
  PIN arb_port_i[61]
    DIRECTION INPUT ;
    USE SIGNAL ;
    ANTENNAGATEAREA 0.426000 ;
    PORT
      LAYER met3 ;
        RECT 845.000 87.080 849.000 87.680 ;
    END
  END arb_port_i[61]
  PIN arb_port_i[62]
    DIRECTION INPUT ;
    USE SIGNAL ;
    ANTENNAGATEAREA 0.426000 ;
    PORT
      LAYER met3 ;
        RECT 845.000 88.440 849.000 89.040 ;
    END
  END arb_port_i[62]
  PIN arb_port_i[63]
    DIRECTION INPUT ;
    USE SIGNAL ;
    ANTENNAGATEAREA 0.426000 ;
    PORT
      LAYER met3 ;
        RECT 845.000 89.800 849.000 90.400 ;
    END
  END arb_port_i[63]
  PIN arb_port_i[64]
    DIRECTION INPUT ;
    USE SIGNAL ;
    ANTENNAGATEAREA 0.426000 ;
    PORT
      LAYER met3 ;
        RECT 845.000 91.160 849.000 91.760 ;
    END
  END arb_port_i[64]
  PIN arb_port_i[65]
    DIRECTION INPUT ;
    USE SIGNAL ;
    ANTENNAGATEAREA 0.426000 ;
    PORT
      LAYER met3 ;
        RECT 845.000 92.520 849.000 93.120 ;
    END
  END arb_port_i[65]
  PIN arb_port_i[66]
    DIRECTION INPUT ;
    USE SIGNAL ;
    ANTENNAGATEAREA 0.426000 ;
    PORT
      LAYER met3 ;
        RECT 845.000 93.880 849.000 94.480 ;
    END
  END arb_port_i[66]
  PIN arb_port_i[67]
    DIRECTION INPUT ;
    USE SIGNAL ;
    ANTENNAGATEAREA 0.426000 ;
    PORT
      LAYER met3 ;
        RECT 845.000 95.240 849.000 95.840 ;
    END
  END arb_port_i[67]
  PIN arb_port_i[68]
    DIRECTION INPUT ;
    USE SIGNAL ;
    ANTENNAGATEAREA 0.426000 ;
    PORT
      LAYER met3 ;
        RECT 845.000 96.600 849.000 97.200 ;
    END
  END arb_port_i[68]
  PIN arb_port_i[69]
    DIRECTION INPUT ;
    USE SIGNAL ;
    ANTENNAGATEAREA 0.426000 ;
    PORT
      LAYER met3 ;
        RECT 845.000 97.960 849.000 98.560 ;
    END
  END arb_port_i[69]
  PIN arb_port_i[6]
    DIRECTION INPUT ;
    USE SIGNAL ;
    ANTENNAGATEAREA 0.742500 ;
    PORT
      LAYER met3 ;
        RECT 845.000 12.280 849.000 12.880 ;
    END
  END arb_port_i[6]
  PIN arb_port_i[70]
    DIRECTION INPUT ;
    USE SIGNAL ;
    ANTENNAGATEAREA 0.426000 ;
    PORT
      LAYER met3 ;
        RECT 845.000 99.320 849.000 99.920 ;
    END
  END arb_port_i[70]
  PIN arb_port_i[71]
    DIRECTION INPUT ;
    USE SIGNAL ;
    ANTENNAGATEAREA 0.426000 ;
    PORT
      LAYER met3 ;
        RECT 845.000 100.680 849.000 101.280 ;
    END
  END arb_port_i[71]
  PIN arb_port_i[72]
    DIRECTION INPUT ;
    USE SIGNAL ;
    ANTENNAGATEAREA 0.426000 ;
    PORT
      LAYER met3 ;
        RECT 845.000 102.040 849.000 102.640 ;
    END
  END arb_port_i[72]
  PIN arb_port_i[73]
    DIRECTION INPUT ;
    USE SIGNAL ;
    ANTENNAGATEAREA 0.426000 ;
    PORT
      LAYER met3 ;
        RECT 845.000 103.400 849.000 104.000 ;
    END
  END arb_port_i[73]
  PIN arb_port_i[74]
    DIRECTION INPUT ;
    USE SIGNAL ;
    ANTENNAGATEAREA 0.426000 ;
    PORT
      LAYER met3 ;
        RECT 845.000 104.760 849.000 105.360 ;
    END
  END arb_port_i[74]
  PIN arb_port_i[75]
    DIRECTION INPUT ;
    USE SIGNAL ;
    ANTENNAGATEAREA 0.426000 ;
    PORT
      LAYER met3 ;
        RECT 845.000 106.120 849.000 106.720 ;
    END
  END arb_port_i[75]
  PIN arb_port_i[76]
    DIRECTION INPUT ;
    USE SIGNAL ;
    ANTENNAGATEAREA 0.426000 ;
    PORT
      LAYER met3 ;
        RECT 845.000 107.480 849.000 108.080 ;
    END
  END arb_port_i[76]
  PIN arb_port_i[77]
    DIRECTION INPUT ;
    USE SIGNAL ;
    ANTENNAGATEAREA 0.426000 ;
    PORT
      LAYER met3 ;
        RECT 845.000 108.840 849.000 109.440 ;
    END
  END arb_port_i[77]
  PIN arb_port_i[78]
    DIRECTION INPUT ;
    USE SIGNAL ;
    ANTENNAGATEAREA 0.426000 ;
    PORT
      LAYER met3 ;
        RECT 845.000 110.200 849.000 110.800 ;
    END
  END arb_port_i[78]
  PIN arb_port_i[79]
    DIRECTION INPUT ;
    USE SIGNAL ;
    ANTENNAGATEAREA 0.426000 ;
    PORT
      LAYER met3 ;
        RECT 845.000 111.560 849.000 112.160 ;
    END
  END arb_port_i[79]
  PIN arb_port_i[7]
    DIRECTION INPUT ;
    USE SIGNAL ;
    ANTENNAGATEAREA 0.742500 ;
    PORT
      LAYER met3 ;
        RECT 845.000 13.640 849.000 14.240 ;
    END
  END arb_port_i[7]
  PIN arb_port_i[80]
    DIRECTION INPUT ;
    USE SIGNAL ;
    ANTENNAGATEAREA 0.426000 ;
    PORT
      LAYER met3 ;
        RECT 845.000 112.920 849.000 113.520 ;
    END
  END arb_port_i[80]
  PIN arb_port_i[81]
    DIRECTION INPUT ;
    USE SIGNAL ;
    ANTENNAGATEAREA 0.426000 ;
    PORT
      LAYER met3 ;
        RECT 845.000 114.280 849.000 114.880 ;
    END
  END arb_port_i[81]
  PIN arb_port_i[82]
    DIRECTION INPUT ;
    USE SIGNAL ;
    ANTENNAGATEAREA 0.426000 ;
    PORT
      LAYER met3 ;
        RECT 845.000 115.640 849.000 116.240 ;
    END
  END arb_port_i[82]
  PIN arb_port_i[83]
    DIRECTION INPUT ;
    USE SIGNAL ;
    ANTENNAGATEAREA 0.426000 ;
    PORT
      LAYER met3 ;
        RECT 845.000 117.000 849.000 117.600 ;
    END
  END arb_port_i[83]
  PIN arb_port_i[84]
    DIRECTION INPUT ;
    USE SIGNAL ;
    ANTENNAGATEAREA 0.426000 ;
    PORT
      LAYER met3 ;
        RECT 845.000 118.360 849.000 118.960 ;
    END
  END arb_port_i[84]
  PIN arb_port_i[85]
    DIRECTION INPUT ;
    USE SIGNAL ;
    ANTENNAGATEAREA 0.426000 ;
    PORT
      LAYER met3 ;
        RECT 845.000 119.720 849.000 120.320 ;
    END
  END arb_port_i[85]
  PIN arb_port_i[86]
    DIRECTION INPUT ;
    USE SIGNAL ;
    ANTENNAGATEAREA 0.495000 ;
    PORT
      LAYER met3 ;
        RECT 845.000 121.080 849.000 121.680 ;
    END
  END arb_port_i[86]
  PIN arb_port_i[87]
    DIRECTION INPUT ;
    USE SIGNAL ;
    ANTENNAGATEAREA 0.495000 ;
    PORT
      LAYER met3 ;
        RECT 845.000 122.440 849.000 123.040 ;
    END
  END arb_port_i[87]
  PIN arb_port_i[88]
    DIRECTION INPUT ;
    USE SIGNAL ;
    ANTENNAGATEAREA 0.495000 ;
    PORT
      LAYER met3 ;
        RECT 845.000 123.800 849.000 124.400 ;
    END
  END arb_port_i[88]
  PIN arb_port_i[89]
    DIRECTION INPUT ;
    USE SIGNAL ;
    ANTENNAGATEAREA 0.426000 ;
    PORT
      LAYER met3 ;
        RECT 845.000 125.160 849.000 125.760 ;
    END
  END arb_port_i[89]
  PIN arb_port_i[8]
    DIRECTION INPUT ;
    USE SIGNAL ;
    ANTENNAGATEAREA 0.742500 ;
    PORT
      LAYER met3 ;
        RECT 845.000 15.000 849.000 15.600 ;
    END
  END arb_port_i[8]
  PIN arb_port_i[90]
    DIRECTION INPUT ;
    USE SIGNAL ;
    ANTENNAGATEAREA 0.495000 ;
    PORT
      LAYER met3 ;
        RECT 845.000 126.520 849.000 127.120 ;
    END
  END arb_port_i[90]
  PIN arb_port_i[91]
    DIRECTION INPUT ;
    USE SIGNAL ;
    ANTENNAGATEAREA 0.426000 ;
    PORT
      LAYER met3 ;
        RECT 845.000 127.880 849.000 128.480 ;
    END
  END arb_port_i[91]
  PIN arb_port_i[92]
    DIRECTION INPUT ;
    USE SIGNAL ;
    ANTENNAGATEAREA 0.495000 ;
    PORT
      LAYER met3 ;
        RECT 845.000 129.240 849.000 129.840 ;
    END
  END arb_port_i[92]
  PIN arb_port_i[93]
    DIRECTION INPUT ;
    USE SIGNAL ;
    ANTENNAGATEAREA 0.426000 ;
    PORT
      LAYER met3 ;
        RECT 845.000 130.600 849.000 131.200 ;
    END
  END arb_port_i[93]
  PIN arb_port_i[94]
    DIRECTION INPUT ;
    USE SIGNAL ;
    ANTENNAGATEAREA 0.426000 ;
    PORT
      LAYER met3 ;
        RECT 845.000 131.960 849.000 132.560 ;
    END
  END arb_port_i[94]
  PIN arb_port_i[95]
    DIRECTION INPUT ;
    USE SIGNAL ;
    ANTENNAGATEAREA 0.495000 ;
    PORT
      LAYER met3 ;
        RECT 845.000 133.320 849.000 133.920 ;
    END
  END arb_port_i[95]
  PIN arb_port_i[96]
    DIRECTION INPUT ;
    USE SIGNAL ;
    ANTENNAGATEAREA 0.426000 ;
    PORT
      LAYER met3 ;
        RECT 845.000 134.680 849.000 135.280 ;
    END
  END arb_port_i[96]
  PIN arb_port_i[97]
    DIRECTION INPUT ;
    USE SIGNAL ;
    ANTENNAGATEAREA 0.426000 ;
    PORT
      LAYER met3 ;
        RECT 845.000 136.040 849.000 136.640 ;
    END
  END arb_port_i[97]
  PIN arb_port_i[98]
    DIRECTION INPUT ;
    USE SIGNAL ;
    ANTENNAGATEAREA 0.426000 ;
    PORT
      LAYER met3 ;
        RECT 845.000 137.400 849.000 138.000 ;
    END
  END arb_port_i[98]
  PIN arb_port_i[99]
    DIRECTION INPUT ;
    USE SIGNAL ;
    ANTENNAGATEAREA 0.426000 ;
    PORT
      LAYER met3 ;
        RECT 845.000 138.760 849.000 139.360 ;
    END
  END arb_port_i[99]
  PIN arb_port_i[9]
    DIRECTION INPUT ;
    USE SIGNAL ;
    ANTENNAGATEAREA 0.742500 ;
    PORT
      LAYER met3 ;
        RECT 845.000 16.360 849.000 16.960 ;
    END
  END arb_port_i[9]
  PIN arb_port_o[0]
    DIRECTION OUTPUT TRISTATE ;
    USE SIGNAL ;
    ANTENNADIFFAREA 2.673000 ;
    PORT
      LAYER met3 ;
        RECT 845.000 281.560 849.000 282.160 ;
    END
  END arb_port_o[0]
  PIN arb_port_o[100]
    DIRECTION OUTPUT TRISTATE ;
    USE SIGNAL ;
    ANTENNADIFFAREA 2.673000 ;
    PORT
      LAYER met3 ;
        RECT 845.000 417.560 849.000 418.160 ;
    END
  END arb_port_o[100]
  PIN arb_port_o[101]
    DIRECTION OUTPUT TRISTATE ;
    USE SIGNAL ;
    ANTENNADIFFAREA 2.673000 ;
    PORT
      LAYER met3 ;
        RECT 845.000 418.920 849.000 419.520 ;
    END
  END arb_port_o[101]
  PIN arb_port_o[102]
    DIRECTION OUTPUT TRISTATE ;
    USE SIGNAL ;
    ANTENNADIFFAREA 2.673000 ;
    PORT
      LAYER met3 ;
        RECT 845.000 420.280 849.000 420.880 ;
    END
  END arb_port_o[102]
  PIN arb_port_o[103]
    DIRECTION OUTPUT TRISTATE ;
    USE SIGNAL ;
    ANTENNADIFFAREA 2.673000 ;
    PORT
      LAYER met3 ;
        RECT 845.000 421.640 849.000 422.240 ;
    END
  END arb_port_o[103]
  PIN arb_port_o[104]
    DIRECTION OUTPUT TRISTATE ;
    USE SIGNAL ;
    ANTENNADIFFAREA 2.673000 ;
    PORT
      LAYER met3 ;
        RECT 845.000 423.000 849.000 423.600 ;
    END
  END arb_port_o[104]
  PIN arb_port_o[105]
    DIRECTION OUTPUT TRISTATE ;
    USE SIGNAL ;
    ANTENNADIFFAREA 2.673000 ;
    PORT
      LAYER met3 ;
        RECT 845.000 424.360 849.000 424.960 ;
    END
  END arb_port_o[105]
  PIN arb_port_o[106]
    DIRECTION OUTPUT TRISTATE ;
    USE SIGNAL ;
    ANTENNADIFFAREA 2.673000 ;
    PORT
      LAYER met3 ;
        RECT 845.000 425.720 849.000 426.320 ;
    END
  END arb_port_o[106]
  PIN arb_port_o[107]
    DIRECTION OUTPUT TRISTATE ;
    USE SIGNAL ;
    ANTENNADIFFAREA 2.673000 ;
    PORT
      LAYER met3 ;
        RECT 845.000 427.080 849.000 427.680 ;
    END
  END arb_port_o[107]
  PIN arb_port_o[108]
    DIRECTION OUTPUT TRISTATE ;
    USE SIGNAL ;
    ANTENNADIFFAREA 2.673000 ;
    PORT
      LAYER met3 ;
        RECT 845.000 428.440 849.000 429.040 ;
    END
  END arb_port_o[108]
  PIN arb_port_o[109]
    DIRECTION OUTPUT TRISTATE ;
    USE SIGNAL ;
    ANTENNADIFFAREA 2.673000 ;
    PORT
      LAYER met3 ;
        RECT 845.000 429.800 849.000 430.400 ;
    END
  END arb_port_o[109]
  PIN arb_port_o[10]
    DIRECTION OUTPUT TRISTATE ;
    USE SIGNAL ;
    ANTENNADIFFAREA 2.673000 ;
    PORT
      LAYER met3 ;
        RECT 845.000 295.160 849.000 295.760 ;
    END
  END arb_port_o[10]
  PIN arb_port_o[110]
    DIRECTION OUTPUT TRISTATE ;
    USE SIGNAL ;
    ANTENNADIFFAREA 2.673000 ;
    PORT
      LAYER met3 ;
        RECT 845.000 431.160 849.000 431.760 ;
    END
  END arb_port_o[110]
  PIN arb_port_o[111]
    DIRECTION OUTPUT TRISTATE ;
    USE SIGNAL ;
    ANTENNADIFFAREA 2.673000 ;
    PORT
      LAYER met3 ;
        RECT 845.000 432.520 849.000 433.120 ;
    END
  END arb_port_o[111]
  PIN arb_port_o[112]
    DIRECTION OUTPUT TRISTATE ;
    USE SIGNAL ;
    ANTENNADIFFAREA 2.673000 ;
    PORT
      LAYER met3 ;
        RECT 845.000 433.880 849.000 434.480 ;
    END
  END arb_port_o[112]
  PIN arb_port_o[113]
    DIRECTION OUTPUT TRISTATE ;
    USE SIGNAL ;
    ANTENNADIFFAREA 2.673000 ;
    PORT
      LAYER met3 ;
        RECT 845.000 435.240 849.000 435.840 ;
    END
  END arb_port_o[113]
  PIN arb_port_o[114]
    DIRECTION OUTPUT TRISTATE ;
    USE SIGNAL ;
    ANTENNADIFFAREA 2.673000 ;
    PORT
      LAYER met3 ;
        RECT 845.000 436.600 849.000 437.200 ;
    END
  END arb_port_o[114]
  PIN arb_port_o[115]
    DIRECTION OUTPUT TRISTATE ;
    USE SIGNAL ;
    ANTENNADIFFAREA 2.673000 ;
    PORT
      LAYER met3 ;
        RECT 845.000 437.960 849.000 438.560 ;
    END
  END arb_port_o[115]
  PIN arb_port_o[116]
    DIRECTION OUTPUT TRISTATE ;
    USE SIGNAL ;
    ANTENNADIFFAREA 2.673000 ;
    PORT
      LAYER met3 ;
        RECT 845.000 439.320 849.000 439.920 ;
    END
  END arb_port_o[116]
  PIN arb_port_o[117]
    DIRECTION OUTPUT TRISTATE ;
    USE SIGNAL ;
    ANTENNADIFFAREA 2.673000 ;
    PORT
      LAYER met3 ;
        RECT 845.000 440.680 849.000 441.280 ;
    END
  END arb_port_o[117]
  PIN arb_port_o[118]
    DIRECTION OUTPUT TRISTATE ;
    USE SIGNAL ;
    ANTENNADIFFAREA 2.673000 ;
    PORT
      LAYER met3 ;
        RECT 845.000 442.040 849.000 442.640 ;
    END
  END arb_port_o[118]
  PIN arb_port_o[119]
    DIRECTION OUTPUT TRISTATE ;
    USE SIGNAL ;
    ANTENNADIFFAREA 2.673000 ;
    PORT
      LAYER met3 ;
        RECT 845.000 443.400 849.000 444.000 ;
    END
  END arb_port_o[119]
  PIN arb_port_o[11]
    DIRECTION OUTPUT TRISTATE ;
    USE SIGNAL ;
    ANTENNADIFFAREA 2.673000 ;
    PORT
      LAYER met3 ;
        RECT 845.000 296.520 849.000 297.120 ;
    END
  END arb_port_o[11]
  PIN arb_port_o[120]
    DIRECTION OUTPUT TRISTATE ;
    USE SIGNAL ;
    ANTENNADIFFAREA 2.673000 ;
    PORT
      LAYER met3 ;
        RECT 845.000 444.760 849.000 445.360 ;
    END
  END arb_port_o[120]
  PIN arb_port_o[121]
    DIRECTION OUTPUT TRISTATE ;
    USE SIGNAL ;
    ANTENNADIFFAREA 2.673000 ;
    PORT
      LAYER met3 ;
        RECT 845.000 446.120 849.000 446.720 ;
    END
  END arb_port_o[121]
  PIN arb_port_o[122]
    DIRECTION OUTPUT TRISTATE ;
    USE SIGNAL ;
    ANTENNADIFFAREA 2.673000 ;
    PORT
      LAYER met3 ;
        RECT 845.000 447.480 849.000 448.080 ;
    END
  END arb_port_o[122]
  PIN arb_port_o[123]
    DIRECTION OUTPUT TRISTATE ;
    USE SIGNAL ;
    ANTENNADIFFAREA 2.673000 ;
    PORT
      LAYER met3 ;
        RECT 845.000 448.840 849.000 449.440 ;
    END
  END arb_port_o[123]
  PIN arb_port_o[124]
    DIRECTION OUTPUT TRISTATE ;
    USE SIGNAL ;
    ANTENNADIFFAREA 2.673000 ;
    PORT
      LAYER met3 ;
        RECT 845.000 450.200 849.000 450.800 ;
    END
  END arb_port_o[124]
  PIN arb_port_o[125]
    DIRECTION OUTPUT TRISTATE ;
    USE SIGNAL ;
    ANTENNADIFFAREA 2.673000 ;
    PORT
      LAYER met3 ;
        RECT 845.000 451.560 849.000 452.160 ;
    END
  END arb_port_o[125]
  PIN arb_port_o[126]
    DIRECTION OUTPUT TRISTATE ;
    USE SIGNAL ;
    ANTENNADIFFAREA 2.673000 ;
    PORT
      LAYER met3 ;
        RECT 845.000 452.920 849.000 453.520 ;
    END
  END arb_port_o[126]
  PIN arb_port_o[127]
    DIRECTION OUTPUT TRISTATE ;
    USE SIGNAL ;
    ANTENNADIFFAREA 2.673000 ;
    PORT
      LAYER met3 ;
        RECT 845.000 454.280 849.000 454.880 ;
    END
  END arb_port_o[127]
  PIN arb_port_o[128]
    DIRECTION OUTPUT TRISTATE ;
    USE SIGNAL ;
    ANTENNADIFFAREA 2.673000 ;
    PORT
      LAYER met3 ;
        RECT 845.000 455.640 849.000 456.240 ;
    END
  END arb_port_o[128]
  PIN arb_port_o[129]
    DIRECTION OUTPUT TRISTATE ;
    USE SIGNAL ;
    ANTENNADIFFAREA 2.673000 ;
    PORT
      LAYER met3 ;
        RECT 845.000 457.000 849.000 457.600 ;
    END
  END arb_port_o[129]
  PIN arb_port_o[12]
    DIRECTION OUTPUT TRISTATE ;
    USE SIGNAL ;
    ANTENNADIFFAREA 2.673000 ;
    PORT
      LAYER met3 ;
        RECT 845.000 297.880 849.000 298.480 ;
    END
  END arb_port_o[12]
  PIN arb_port_o[130]
    DIRECTION OUTPUT TRISTATE ;
    USE SIGNAL ;
    ANTENNADIFFAREA 2.673000 ;
    PORT
      LAYER met3 ;
        RECT 845.000 458.360 849.000 458.960 ;
    END
  END arb_port_o[130]
  PIN arb_port_o[131]
    DIRECTION OUTPUT TRISTATE ;
    USE SIGNAL ;
    ANTENNADIFFAREA 2.673000 ;
    PORT
      LAYER met3 ;
        RECT 845.000 459.720 849.000 460.320 ;
    END
  END arb_port_o[131]
  PIN arb_port_o[132]
    DIRECTION OUTPUT TRISTATE ;
    USE SIGNAL ;
    ANTENNADIFFAREA 2.673000 ;
    PORT
      LAYER met3 ;
        RECT 845.000 461.080 849.000 461.680 ;
    END
  END arb_port_o[132]
  PIN arb_port_o[133]
    DIRECTION OUTPUT TRISTATE ;
    USE SIGNAL ;
    ANTENNADIFFAREA 2.673000 ;
    PORT
      LAYER met3 ;
        RECT 845.000 462.440 849.000 463.040 ;
    END
  END arb_port_o[133]
  PIN arb_port_o[134]
    DIRECTION OUTPUT TRISTATE ;
    USE SIGNAL ;
    ANTENNADIFFAREA 2.673000 ;
    PORT
      LAYER met3 ;
        RECT 845.000 463.800 849.000 464.400 ;
    END
  END arb_port_o[134]
  PIN arb_port_o[135]
    DIRECTION OUTPUT TRISTATE ;
    USE SIGNAL ;
    ANTENNADIFFAREA 2.673000 ;
    PORT
      LAYER met3 ;
        RECT 845.000 465.160 849.000 465.760 ;
    END
  END arb_port_o[135]
  PIN arb_port_o[136]
    DIRECTION OUTPUT TRISTATE ;
    USE SIGNAL ;
    ANTENNADIFFAREA 2.673000 ;
    PORT
      LAYER met3 ;
        RECT 845.000 466.520 849.000 467.120 ;
    END
  END arb_port_o[136]
  PIN arb_port_o[137]
    DIRECTION OUTPUT TRISTATE ;
    USE SIGNAL ;
    ANTENNADIFFAREA 2.673000 ;
    PORT
      LAYER met3 ;
        RECT 845.000 467.880 849.000 468.480 ;
    END
  END arb_port_o[137]
  PIN arb_port_o[138]
    DIRECTION OUTPUT TRISTATE ;
    USE SIGNAL ;
    ANTENNADIFFAREA 2.673000 ;
    PORT
      LAYER met3 ;
        RECT 845.000 469.240 849.000 469.840 ;
    END
  END arb_port_o[138]
  PIN arb_port_o[139]
    DIRECTION OUTPUT TRISTATE ;
    USE SIGNAL ;
    ANTENNADIFFAREA 2.673000 ;
    PORT
      LAYER met3 ;
        RECT 845.000 470.600 849.000 471.200 ;
    END
  END arb_port_o[139]
  PIN arb_port_o[13]
    DIRECTION OUTPUT TRISTATE ;
    USE SIGNAL ;
    ANTENNADIFFAREA 2.673000 ;
    PORT
      LAYER met3 ;
        RECT 845.000 299.240 849.000 299.840 ;
    END
  END arb_port_o[13]
  PIN arb_port_o[140]
    DIRECTION OUTPUT TRISTATE ;
    USE SIGNAL ;
    ANTENNADIFFAREA 2.673000 ;
    PORT
      LAYER met3 ;
        RECT 845.000 471.960 849.000 472.560 ;
    END
  END arb_port_o[140]
  PIN arb_port_o[141]
    DIRECTION OUTPUT TRISTATE ;
    USE SIGNAL ;
    ANTENNADIFFAREA 2.673000 ;
    PORT
      LAYER met3 ;
        RECT 845.000 473.320 849.000 473.920 ;
    END
  END arb_port_o[141]
  PIN arb_port_o[142]
    DIRECTION OUTPUT TRISTATE ;
    USE SIGNAL ;
    ANTENNADIFFAREA 2.673000 ;
    PORT
      LAYER met3 ;
        RECT 845.000 474.680 849.000 475.280 ;
    END
  END arb_port_o[142]
  PIN arb_port_o[143]
    DIRECTION OUTPUT TRISTATE ;
    USE SIGNAL ;
    ANTENNADIFFAREA 2.673000 ;
    PORT
      LAYER met3 ;
        RECT 845.000 476.040 849.000 476.640 ;
    END
  END arb_port_o[143]
  PIN arb_port_o[144]
    DIRECTION OUTPUT TRISTATE ;
    USE SIGNAL ;
    ANTENNADIFFAREA 2.673000 ;
    PORT
      LAYER met3 ;
        RECT 845.000 477.400 849.000 478.000 ;
    END
  END arb_port_o[144]
  PIN arb_port_o[145]
    DIRECTION OUTPUT TRISTATE ;
    USE SIGNAL ;
    ANTENNADIFFAREA 2.673000 ;
    PORT
      LAYER met3 ;
        RECT 845.000 478.760 849.000 479.360 ;
    END
  END arb_port_o[145]
  PIN arb_port_o[146]
    DIRECTION OUTPUT TRISTATE ;
    USE SIGNAL ;
    ANTENNADIFFAREA 2.673000 ;
    PORT
      LAYER met3 ;
        RECT 845.000 480.120 849.000 480.720 ;
    END
  END arb_port_o[146]
  PIN arb_port_o[147]
    DIRECTION OUTPUT TRISTATE ;
    USE SIGNAL ;
    ANTENNADIFFAREA 2.673000 ;
    PORT
      LAYER met3 ;
        RECT 845.000 481.480 849.000 482.080 ;
    END
  END arb_port_o[147]
  PIN arb_port_o[148]
    DIRECTION OUTPUT TRISTATE ;
    USE SIGNAL ;
    ANTENNADIFFAREA 2.673000 ;
    PORT
      LAYER met3 ;
        RECT 845.000 482.840 849.000 483.440 ;
    END
  END arb_port_o[148]
  PIN arb_port_o[149]
    DIRECTION OUTPUT TRISTATE ;
    USE SIGNAL ;
    ANTENNADIFFAREA 2.673000 ;
    PORT
      LAYER met3 ;
        RECT 845.000 484.200 849.000 484.800 ;
    END
  END arb_port_o[149]
  PIN arb_port_o[14]
    DIRECTION OUTPUT TRISTATE ;
    USE SIGNAL ;
    ANTENNADIFFAREA 2.673000 ;
    PORT
      LAYER met3 ;
        RECT 845.000 300.600 849.000 301.200 ;
    END
  END arb_port_o[14]
  PIN arb_port_o[150]
    DIRECTION OUTPUT TRISTATE ;
    USE SIGNAL ;
    ANTENNADIFFAREA 2.673000 ;
    PORT
      LAYER met3 ;
        RECT 845.000 485.560 849.000 486.160 ;
    END
  END arb_port_o[150]
  PIN arb_port_o[151]
    DIRECTION OUTPUT TRISTATE ;
    USE SIGNAL ;
    ANTENNADIFFAREA 2.673000 ;
    PORT
      LAYER met3 ;
        RECT 845.000 486.920 849.000 487.520 ;
    END
  END arb_port_o[151]
  PIN arb_port_o[152]
    DIRECTION OUTPUT TRISTATE ;
    USE SIGNAL ;
    ANTENNADIFFAREA 2.673000 ;
    PORT
      LAYER met3 ;
        RECT 845.000 488.280 849.000 488.880 ;
    END
  END arb_port_o[152]
  PIN arb_port_o[153]
    DIRECTION OUTPUT TRISTATE ;
    USE SIGNAL ;
    ANTENNADIFFAREA 2.673000 ;
    PORT
      LAYER met3 ;
        RECT 845.000 489.640 849.000 490.240 ;
    END
  END arb_port_o[153]
  PIN arb_port_o[154]
    DIRECTION OUTPUT TRISTATE ;
    USE SIGNAL ;
    ANTENNADIFFAREA 2.673000 ;
    PORT
      LAYER met3 ;
        RECT 845.000 491.000 849.000 491.600 ;
    END
  END arb_port_o[154]
  PIN arb_port_o[155]
    DIRECTION OUTPUT TRISTATE ;
    USE SIGNAL ;
    ANTENNADIFFAREA 2.673000 ;
    PORT
      LAYER met3 ;
        RECT 845.000 492.360 849.000 492.960 ;
    END
  END arb_port_o[155]
  PIN arb_port_o[156]
    DIRECTION OUTPUT TRISTATE ;
    USE SIGNAL ;
    ANTENNADIFFAREA 2.673000 ;
    PORT
      LAYER met3 ;
        RECT 845.000 493.720 849.000 494.320 ;
    END
  END arb_port_o[156]
  PIN arb_port_o[157]
    DIRECTION OUTPUT TRISTATE ;
    USE SIGNAL ;
    ANTENNADIFFAREA 2.673000 ;
    PORT
      LAYER met3 ;
        RECT 845.000 495.080 849.000 495.680 ;
    END
  END arb_port_o[157]
  PIN arb_port_o[158]
    DIRECTION OUTPUT TRISTATE ;
    USE SIGNAL ;
    ANTENNADIFFAREA 2.673000 ;
    PORT
      LAYER met3 ;
        RECT 845.000 496.440 849.000 497.040 ;
    END
  END arb_port_o[158]
  PIN arb_port_o[159]
    DIRECTION OUTPUT TRISTATE ;
    USE SIGNAL ;
    ANTENNADIFFAREA 2.673000 ;
    PORT
      LAYER met3 ;
        RECT 845.000 497.800 849.000 498.400 ;
    END
  END arb_port_o[159]
  PIN arb_port_o[15]
    DIRECTION OUTPUT TRISTATE ;
    USE SIGNAL ;
    ANTENNADIFFAREA 2.673000 ;
    PORT
      LAYER met3 ;
        RECT 845.000 301.960 849.000 302.560 ;
    END
  END arb_port_o[15]
  PIN arb_port_o[160]
    DIRECTION OUTPUT TRISTATE ;
    USE SIGNAL ;
    ANTENNADIFFAREA 2.673000 ;
    PORT
      LAYER met3 ;
        RECT 845.000 499.160 849.000 499.760 ;
    END
  END arb_port_o[160]
  PIN arb_port_o[161]
    DIRECTION OUTPUT TRISTATE ;
    USE SIGNAL ;
    ANTENNADIFFAREA 2.673000 ;
    PORT
      LAYER met3 ;
        RECT 845.000 500.520 849.000 501.120 ;
    END
  END arb_port_o[161]
  PIN arb_port_o[162]
    DIRECTION OUTPUT TRISTATE ;
    USE SIGNAL ;
    ANTENNADIFFAREA 2.673000 ;
    PORT
      LAYER met3 ;
        RECT 845.000 501.880 849.000 502.480 ;
    END
  END arb_port_o[162]
  PIN arb_port_o[163]
    DIRECTION OUTPUT TRISTATE ;
    USE SIGNAL ;
    ANTENNADIFFAREA 2.673000 ;
    PORT
      LAYER met3 ;
        RECT 845.000 503.240 849.000 503.840 ;
    END
  END arb_port_o[163]
  PIN arb_port_o[164]
    DIRECTION OUTPUT TRISTATE ;
    USE SIGNAL ;
    ANTENNADIFFAREA 2.673000 ;
    PORT
      LAYER met3 ;
        RECT 845.000 504.600 849.000 505.200 ;
    END
  END arb_port_o[164]
  PIN arb_port_o[165]
    DIRECTION OUTPUT TRISTATE ;
    USE SIGNAL ;
    ANTENNADIFFAREA 2.673000 ;
    PORT
      LAYER met3 ;
        RECT 845.000 505.960 849.000 506.560 ;
    END
  END arb_port_o[165]
  PIN arb_port_o[166]
    DIRECTION OUTPUT TRISTATE ;
    USE SIGNAL ;
    ANTENNADIFFAREA 2.673000 ;
    PORT
      LAYER met3 ;
        RECT 845.000 507.320 849.000 507.920 ;
    END
  END arb_port_o[166]
  PIN arb_port_o[167]
    DIRECTION OUTPUT TRISTATE ;
    USE SIGNAL ;
    ANTENNADIFFAREA 2.673000 ;
    PORT
      LAYER met3 ;
        RECT 845.000 508.680 849.000 509.280 ;
    END
  END arb_port_o[167]
  PIN arb_port_o[168]
    DIRECTION OUTPUT TRISTATE ;
    USE SIGNAL ;
    ANTENNADIFFAREA 2.673000 ;
    PORT
      LAYER met3 ;
        RECT 845.000 510.040 849.000 510.640 ;
    END
  END arb_port_o[168]
  PIN arb_port_o[169]
    DIRECTION OUTPUT TRISTATE ;
    USE SIGNAL ;
    ANTENNADIFFAREA 2.673000 ;
    PORT
      LAYER met3 ;
        RECT 845.000 511.400 849.000 512.000 ;
    END
  END arb_port_o[169]
  PIN arb_port_o[16]
    DIRECTION OUTPUT TRISTATE ;
    USE SIGNAL ;
    ANTENNADIFFAREA 2.673000 ;
    PORT
      LAYER met3 ;
        RECT 845.000 303.320 849.000 303.920 ;
    END
  END arb_port_o[16]
  PIN arb_port_o[170]
    DIRECTION OUTPUT TRISTATE ;
    USE SIGNAL ;
    ANTENNADIFFAREA 2.673000 ;
    PORT
      LAYER met3 ;
        RECT 845.000 512.760 849.000 513.360 ;
    END
  END arb_port_o[170]
  PIN arb_port_o[171]
    DIRECTION OUTPUT TRISTATE ;
    USE SIGNAL ;
    ANTENNADIFFAREA 2.673000 ;
    PORT
      LAYER met3 ;
        RECT 845.000 514.120 849.000 514.720 ;
    END
  END arb_port_o[171]
  PIN arb_port_o[172]
    DIRECTION OUTPUT TRISTATE ;
    USE SIGNAL ;
    ANTENNADIFFAREA 2.673000 ;
    PORT
      LAYER met3 ;
        RECT 845.000 515.480 849.000 516.080 ;
    END
  END arb_port_o[172]
  PIN arb_port_o[173]
    DIRECTION OUTPUT TRISTATE ;
    USE SIGNAL ;
    ANTENNADIFFAREA 2.673000 ;
    PORT
      LAYER met3 ;
        RECT 845.000 516.840 849.000 517.440 ;
    END
  END arb_port_o[173]
  PIN arb_port_o[174]
    DIRECTION OUTPUT TRISTATE ;
    USE SIGNAL ;
    ANTENNADIFFAREA 2.673000 ;
    PORT
      LAYER met3 ;
        RECT 845.000 518.200 849.000 518.800 ;
    END
  END arb_port_o[174]
  PIN arb_port_o[175]
    DIRECTION OUTPUT TRISTATE ;
    USE SIGNAL ;
    ANTENNADIFFAREA 2.673000 ;
    PORT
      LAYER met3 ;
        RECT 845.000 519.560 849.000 520.160 ;
    END
  END arb_port_o[175]
  PIN arb_port_o[176]
    DIRECTION OUTPUT TRISTATE ;
    USE SIGNAL ;
    ANTENNADIFFAREA 2.673000 ;
    PORT
      LAYER met3 ;
        RECT 845.000 520.920 849.000 521.520 ;
    END
  END arb_port_o[176]
  PIN arb_port_o[177]
    DIRECTION OUTPUT TRISTATE ;
    USE SIGNAL ;
    ANTENNADIFFAREA 2.673000 ;
    PORT
      LAYER met3 ;
        RECT 845.000 522.280 849.000 522.880 ;
    END
  END arb_port_o[177]
  PIN arb_port_o[178]
    DIRECTION OUTPUT TRISTATE ;
    USE SIGNAL ;
    ANTENNADIFFAREA 2.673000 ;
    PORT
      LAYER met3 ;
        RECT 845.000 523.640 849.000 524.240 ;
    END
  END arb_port_o[178]
  PIN arb_port_o[179]
    DIRECTION OUTPUT TRISTATE ;
    USE SIGNAL ;
    ANTENNADIFFAREA 2.673000 ;
    PORT
      LAYER met3 ;
        RECT 845.000 525.000 849.000 525.600 ;
    END
  END arb_port_o[179]
  PIN arb_port_o[17]
    DIRECTION OUTPUT TRISTATE ;
    USE SIGNAL ;
    ANTENNADIFFAREA 2.673000 ;
    PORT
      LAYER met3 ;
        RECT 845.000 304.680 849.000 305.280 ;
    END
  END arb_port_o[17]
  PIN arb_port_o[180]
    DIRECTION OUTPUT TRISTATE ;
    USE SIGNAL ;
    ANTENNADIFFAREA 2.673000 ;
    PORT
      LAYER met3 ;
        RECT 845.000 526.360 849.000 526.960 ;
    END
  END arb_port_o[180]
  PIN arb_port_o[181]
    DIRECTION OUTPUT TRISTATE ;
    USE SIGNAL ;
    ANTENNADIFFAREA 2.673000 ;
    PORT
      LAYER met3 ;
        RECT 845.000 527.720 849.000 528.320 ;
    END
  END arb_port_o[181]
  PIN arb_port_o[182]
    DIRECTION OUTPUT TRISTATE ;
    USE SIGNAL ;
    ANTENNADIFFAREA 2.673000 ;
    PORT
      LAYER met3 ;
        RECT 845.000 529.080 849.000 529.680 ;
    END
  END arb_port_o[182]
  PIN arb_port_o[183]
    DIRECTION OUTPUT TRISTATE ;
    USE SIGNAL ;
    ANTENNADIFFAREA 2.673000 ;
    PORT
      LAYER met3 ;
        RECT 845.000 530.440 849.000 531.040 ;
    END
  END arb_port_o[183]
  PIN arb_port_o[184]
    DIRECTION OUTPUT TRISTATE ;
    USE SIGNAL ;
    ANTENNADIFFAREA 2.673000 ;
    PORT
      LAYER met3 ;
        RECT 845.000 531.800 849.000 532.400 ;
    END
  END arb_port_o[184]
  PIN arb_port_o[185]
    DIRECTION OUTPUT TRISTATE ;
    USE SIGNAL ;
    ANTENNADIFFAREA 2.673000 ;
    PORT
      LAYER met3 ;
        RECT 845.000 533.160 849.000 533.760 ;
    END
  END arb_port_o[185]
  PIN arb_port_o[186]
    DIRECTION OUTPUT TRISTATE ;
    USE SIGNAL ;
    ANTENNADIFFAREA 2.673000 ;
    PORT
      LAYER met3 ;
        RECT 845.000 534.520 849.000 535.120 ;
    END
  END arb_port_o[186]
  PIN arb_port_o[187]
    DIRECTION OUTPUT TRISTATE ;
    USE SIGNAL ;
    ANTENNADIFFAREA 2.673000 ;
    PORT
      LAYER met3 ;
        RECT 845.000 535.880 849.000 536.480 ;
    END
  END arb_port_o[187]
  PIN arb_port_o[188]
    DIRECTION OUTPUT TRISTATE ;
    USE SIGNAL ;
    ANTENNADIFFAREA 2.673000 ;
    PORT
      LAYER met3 ;
        RECT 845.000 537.240 849.000 537.840 ;
    END
  END arb_port_o[188]
  PIN arb_port_o[189]
    DIRECTION OUTPUT TRISTATE ;
    USE SIGNAL ;
    ANTENNADIFFAREA 2.673000 ;
    PORT
      LAYER met3 ;
        RECT 845.000 538.600 849.000 539.200 ;
    END
  END arb_port_o[189]
  PIN arb_port_o[18]
    DIRECTION OUTPUT TRISTATE ;
    USE SIGNAL ;
    ANTENNADIFFAREA 2.673000 ;
    PORT
      LAYER met3 ;
        RECT 845.000 306.040 849.000 306.640 ;
    END
  END arb_port_o[18]
  PIN arb_port_o[190]
    DIRECTION OUTPUT TRISTATE ;
    USE SIGNAL ;
    ANTENNADIFFAREA 2.673000 ;
    PORT
      LAYER met3 ;
        RECT 845.000 539.960 849.000 540.560 ;
    END
  END arb_port_o[190]
  PIN arb_port_o[191]
    DIRECTION OUTPUT TRISTATE ;
    USE SIGNAL ;
    ANTENNADIFFAREA 2.673000 ;
    PORT
      LAYER met3 ;
        RECT 845.000 541.320 849.000 541.920 ;
    END
  END arb_port_o[191]
  PIN arb_port_o[192]
    DIRECTION OUTPUT TRISTATE ;
    USE SIGNAL ;
    ANTENNADIFFAREA 2.673000 ;
    PORT
      LAYER met3 ;
        RECT 845.000 542.680 849.000 543.280 ;
    END
  END arb_port_o[192]
  PIN arb_port_o[193]
    DIRECTION OUTPUT TRISTATE ;
    USE SIGNAL ;
    ANTENNADIFFAREA 2.673000 ;
    PORT
      LAYER met3 ;
        RECT 845.000 544.040 849.000 544.640 ;
    END
  END arb_port_o[193]
  PIN arb_port_o[194]
    DIRECTION OUTPUT TRISTATE ;
    USE SIGNAL ;
    ANTENNADIFFAREA 2.673000 ;
    PORT
      LAYER met3 ;
        RECT 845.000 545.400 849.000 546.000 ;
    END
  END arb_port_o[194]
  PIN arb_port_o[195]
    DIRECTION OUTPUT TRISTATE ;
    USE SIGNAL ;
    ANTENNADIFFAREA 2.673000 ;
    PORT
      LAYER met3 ;
        RECT 845.000 546.760 849.000 547.360 ;
    END
  END arb_port_o[195]
  PIN arb_port_o[196]
    DIRECTION OUTPUT TRISTATE ;
    USE SIGNAL ;
    ANTENNADIFFAREA 2.673000 ;
    PORT
      LAYER met3 ;
        RECT 845.000 548.120 849.000 548.720 ;
    END
  END arb_port_o[196]
  PIN arb_port_o[197]
    DIRECTION OUTPUT TRISTATE ;
    USE SIGNAL ;
    ANTENNADIFFAREA 2.673000 ;
    PORT
      LAYER met3 ;
        RECT 845.000 549.480 849.000 550.080 ;
    END
  END arb_port_o[197]
  PIN arb_port_o[198]
    DIRECTION OUTPUT TRISTATE ;
    USE SIGNAL ;
    ANTENNADIFFAREA 2.673000 ;
    PORT
      LAYER met3 ;
        RECT 845.000 550.840 849.000 551.440 ;
    END
  END arb_port_o[198]
  PIN arb_port_o[199]
    DIRECTION OUTPUT TRISTATE ;
    USE SIGNAL ;
    ANTENNADIFFAREA 2.673000 ;
    PORT
      LAYER met3 ;
        RECT 845.000 552.200 849.000 552.800 ;
    END
  END arb_port_o[199]
  PIN arb_port_o[19]
    DIRECTION OUTPUT TRISTATE ;
    USE SIGNAL ;
    ANTENNADIFFAREA 2.673000 ;
    PORT
      LAYER met3 ;
        RECT 845.000 307.400 849.000 308.000 ;
    END
  END arb_port_o[19]
  PIN arb_port_o[1]
    DIRECTION OUTPUT TRISTATE ;
    USE SIGNAL ;
    ANTENNADIFFAREA 2.673000 ;
    PORT
      LAYER met3 ;
        RECT 845.000 282.920 849.000 283.520 ;
    END
  END arb_port_o[1]
  PIN arb_port_o[200]
    DIRECTION OUTPUT TRISTATE ;
    USE SIGNAL ;
    ANTENNADIFFAREA 2.673000 ;
    PORT
      LAYER met3 ;
        RECT 845.000 553.560 849.000 554.160 ;
    END
  END arb_port_o[200]
  PIN arb_port_o[201]
    DIRECTION OUTPUT TRISTATE ;
    USE SIGNAL ;
    ANTENNADIFFAREA 2.673000 ;
    PORT
      LAYER met3 ;
        RECT 845.000 554.920 849.000 555.520 ;
    END
  END arb_port_o[201]
  PIN arb_port_o[202]
    DIRECTION OUTPUT TRISTATE ;
    USE SIGNAL ;
    ANTENNADIFFAREA 2.673000 ;
    PORT
      LAYER met3 ;
        RECT 845.000 556.280 849.000 556.880 ;
    END
  END arb_port_o[202]
  PIN arb_port_o[203]
    DIRECTION OUTPUT TRISTATE ;
    USE SIGNAL ;
    ANTENNADIFFAREA 2.673000 ;
    PORT
      LAYER met3 ;
        RECT 845.000 557.640 849.000 558.240 ;
    END
  END arb_port_o[203]
  PIN arb_port_o[204]
    DIRECTION OUTPUT TRISTATE ;
    USE SIGNAL ;
    ANTENNADIFFAREA 2.673000 ;
    PORT
      LAYER met3 ;
        RECT 845.000 559.000 849.000 559.600 ;
    END
  END arb_port_o[204]
  PIN arb_port_o[205]
    DIRECTION OUTPUT TRISTATE ;
    USE SIGNAL ;
    ANTENNADIFFAREA 2.673000 ;
    PORT
      LAYER met3 ;
        RECT 845.000 560.360 849.000 560.960 ;
    END
  END arb_port_o[205]
  PIN arb_port_o[206]
    DIRECTION OUTPUT TRISTATE ;
    USE SIGNAL ;
    ANTENNADIFFAREA 2.673000 ;
    PORT
      LAYER met3 ;
        RECT 845.000 561.720 849.000 562.320 ;
    END
  END arb_port_o[206]
  PIN arb_port_o[207]
    DIRECTION OUTPUT TRISTATE ;
    USE SIGNAL ;
    ANTENNADIFFAREA 2.673000 ;
    PORT
      LAYER met3 ;
        RECT 845.000 563.080 849.000 563.680 ;
    END
  END arb_port_o[207]
  PIN arb_port_o[208]
    DIRECTION OUTPUT TRISTATE ;
    USE SIGNAL ;
    ANTENNADIFFAREA 2.673000 ;
    PORT
      LAYER met3 ;
        RECT 845.000 564.440 849.000 565.040 ;
    END
  END arb_port_o[208]
  PIN arb_port_o[209]
    DIRECTION OUTPUT TRISTATE ;
    USE SIGNAL ;
    ANTENNADIFFAREA 2.673000 ;
    PORT
      LAYER met3 ;
        RECT 845.000 565.800 849.000 566.400 ;
    END
  END arb_port_o[209]
  PIN arb_port_o[20]
    DIRECTION OUTPUT TRISTATE ;
    USE SIGNAL ;
    ANTENNADIFFAREA 2.673000 ;
    PORT
      LAYER met3 ;
        RECT 845.000 308.760 849.000 309.360 ;
    END
  END arb_port_o[20]
  PIN arb_port_o[210]
    DIRECTION OUTPUT TRISTATE ;
    USE SIGNAL ;
    ANTENNADIFFAREA 2.673000 ;
    PORT
      LAYER met3 ;
        RECT 845.000 567.160 849.000 567.760 ;
    END
  END arb_port_o[210]
  PIN arb_port_o[211]
    DIRECTION OUTPUT TRISTATE ;
    USE SIGNAL ;
    ANTENNADIFFAREA 2.673000 ;
    PORT
      LAYER met3 ;
        RECT 845.000 568.520 849.000 569.120 ;
    END
  END arb_port_o[211]
  PIN arb_port_o[212]
    DIRECTION OUTPUT TRISTATE ;
    USE SIGNAL ;
    ANTENNADIFFAREA 2.673000 ;
    PORT
      LAYER met3 ;
        RECT 845.000 569.880 849.000 570.480 ;
    END
  END arb_port_o[212]
  PIN arb_port_o[213]
    DIRECTION OUTPUT TRISTATE ;
    USE SIGNAL ;
    ANTENNADIFFAREA 2.673000 ;
    PORT
      LAYER met3 ;
        RECT 845.000 571.240 849.000 571.840 ;
    END
  END arb_port_o[213]
  PIN arb_port_o[214]
    DIRECTION OUTPUT TRISTATE ;
    USE SIGNAL ;
    ANTENNADIFFAREA 2.673000 ;
    PORT
      LAYER met3 ;
        RECT 845.000 572.600 849.000 573.200 ;
    END
  END arb_port_o[214]
  PIN arb_port_o[215]
    DIRECTION OUTPUT TRISTATE ;
    USE SIGNAL ;
    ANTENNADIFFAREA 2.673000 ;
    PORT
      LAYER met3 ;
        RECT 845.000 573.960 849.000 574.560 ;
    END
  END arb_port_o[215]
  PIN arb_port_o[216]
    DIRECTION OUTPUT TRISTATE ;
    USE SIGNAL ;
    ANTENNADIFFAREA 2.673000 ;
    PORT
      LAYER met3 ;
        RECT 845.000 575.320 849.000 575.920 ;
    END
  END arb_port_o[216]
  PIN arb_port_o[217]
    DIRECTION OUTPUT TRISTATE ;
    USE SIGNAL ;
    ANTENNADIFFAREA 2.673000 ;
    PORT
      LAYER met3 ;
        RECT 845.000 576.680 849.000 577.280 ;
    END
  END arb_port_o[217]
  PIN arb_port_o[218]
    DIRECTION OUTPUT TRISTATE ;
    USE SIGNAL ;
    ANTENNADIFFAREA 2.673000 ;
    PORT
      LAYER met3 ;
        RECT 845.000 578.040 849.000 578.640 ;
    END
  END arb_port_o[218]
  PIN arb_port_o[219]
    DIRECTION OUTPUT TRISTATE ;
    USE SIGNAL ;
    ANTENNADIFFAREA 2.673000 ;
    PORT
      LAYER met3 ;
        RECT 845.000 579.400 849.000 580.000 ;
    END
  END arb_port_o[219]
  PIN arb_port_o[21]
    DIRECTION OUTPUT TRISTATE ;
    USE SIGNAL ;
    ANTENNADIFFAREA 2.673000 ;
    PORT
      LAYER met3 ;
        RECT 845.000 310.120 849.000 310.720 ;
    END
  END arb_port_o[21]
  PIN arb_port_o[220]
    DIRECTION OUTPUT TRISTATE ;
    USE SIGNAL ;
    ANTENNADIFFAREA 2.673000 ;
    PORT
      LAYER met3 ;
        RECT 845.000 580.760 849.000 581.360 ;
    END
  END arb_port_o[220]
  PIN arb_port_o[221]
    DIRECTION OUTPUT TRISTATE ;
    USE SIGNAL ;
    ANTENNADIFFAREA 2.673000 ;
    PORT
      LAYER met3 ;
        RECT 845.000 582.120 849.000 582.720 ;
    END
  END arb_port_o[221]
  PIN arb_port_o[222]
    DIRECTION OUTPUT TRISTATE ;
    USE SIGNAL ;
    ANTENNADIFFAREA 2.673000 ;
    PORT
      LAYER met3 ;
        RECT 845.000 583.480 849.000 584.080 ;
    END
  END arb_port_o[222]
  PIN arb_port_o[223]
    DIRECTION OUTPUT TRISTATE ;
    USE SIGNAL ;
    ANTENNADIFFAREA 2.673000 ;
    PORT
      LAYER met3 ;
        RECT 845.000 584.840 849.000 585.440 ;
    END
  END arb_port_o[223]
  PIN arb_port_o[224]
    DIRECTION OUTPUT TRISTATE ;
    USE SIGNAL ;
    ANTENNADIFFAREA 2.673000 ;
    PORT
      LAYER met3 ;
        RECT 845.000 586.200 849.000 586.800 ;
    END
  END arb_port_o[224]
  PIN arb_port_o[225]
    DIRECTION OUTPUT TRISTATE ;
    USE SIGNAL ;
    ANTENNADIFFAREA 2.673000 ;
    PORT
      LAYER met3 ;
        RECT 845.000 587.560 849.000 588.160 ;
    END
  END arb_port_o[225]
  PIN arb_port_o[226]
    DIRECTION OUTPUT TRISTATE ;
    USE SIGNAL ;
    ANTENNADIFFAREA 2.673000 ;
    PORT
      LAYER met3 ;
        RECT 845.000 588.920 849.000 589.520 ;
    END
  END arb_port_o[226]
  PIN arb_port_o[227]
    DIRECTION OUTPUT TRISTATE ;
    USE SIGNAL ;
    ANTENNADIFFAREA 2.673000 ;
    PORT
      LAYER met3 ;
        RECT 845.000 590.280 849.000 590.880 ;
    END
  END arb_port_o[227]
  PIN arb_port_o[228]
    DIRECTION OUTPUT TRISTATE ;
    USE SIGNAL ;
    ANTENNADIFFAREA 2.673000 ;
    PORT
      LAYER met3 ;
        RECT 845.000 591.640 849.000 592.240 ;
    END
  END arb_port_o[228]
  PIN arb_port_o[229]
    DIRECTION OUTPUT TRISTATE ;
    USE SIGNAL ;
    ANTENNADIFFAREA 2.673000 ;
    PORT
      LAYER met3 ;
        RECT 845.000 593.000 849.000 593.600 ;
    END
  END arb_port_o[229]
  PIN arb_port_o[22]
    DIRECTION OUTPUT TRISTATE ;
    USE SIGNAL ;
    ANTENNADIFFAREA 2.673000 ;
    PORT
      LAYER met3 ;
        RECT 845.000 311.480 849.000 312.080 ;
    END
  END arb_port_o[22]
  PIN arb_port_o[230]
    DIRECTION OUTPUT TRISTATE ;
    USE SIGNAL ;
    ANTENNADIFFAREA 2.673000 ;
    PORT
      LAYER met3 ;
        RECT 845.000 594.360 849.000 594.960 ;
    END
  END arb_port_o[230]
  PIN arb_port_o[231]
    DIRECTION OUTPUT TRISTATE ;
    USE SIGNAL ;
    ANTENNADIFFAREA 2.673000 ;
    PORT
      LAYER met3 ;
        RECT 845.000 595.720 849.000 596.320 ;
    END
  END arb_port_o[231]
  PIN arb_port_o[232]
    DIRECTION OUTPUT TRISTATE ;
    USE SIGNAL ;
    ANTENNADIFFAREA 2.673000 ;
    PORT
      LAYER met3 ;
        RECT 845.000 597.080 849.000 597.680 ;
    END
  END arb_port_o[232]
  PIN arb_port_o[233]
    DIRECTION OUTPUT TRISTATE ;
    USE SIGNAL ;
    ANTENNADIFFAREA 2.673000 ;
    PORT
      LAYER met3 ;
        RECT 845.000 598.440 849.000 599.040 ;
    END
  END arb_port_o[233]
  PIN arb_port_o[234]
    DIRECTION OUTPUT TRISTATE ;
    USE SIGNAL ;
    ANTENNADIFFAREA 2.673000 ;
    PORT
      LAYER met3 ;
        RECT 845.000 599.800 849.000 600.400 ;
    END
  END arb_port_o[234]
  PIN arb_port_o[235]
    DIRECTION OUTPUT TRISTATE ;
    USE SIGNAL ;
    ANTENNADIFFAREA 2.673000 ;
    PORT
      LAYER met3 ;
        RECT 845.000 601.160 849.000 601.760 ;
    END
  END arb_port_o[235]
  PIN arb_port_o[236]
    DIRECTION OUTPUT TRISTATE ;
    USE SIGNAL ;
    ANTENNADIFFAREA 2.673000 ;
    PORT
      LAYER met3 ;
        RECT 845.000 602.520 849.000 603.120 ;
    END
  END arb_port_o[236]
  PIN arb_port_o[237]
    DIRECTION OUTPUT TRISTATE ;
    USE SIGNAL ;
    ANTENNADIFFAREA 2.673000 ;
    PORT
      LAYER met3 ;
        RECT 845.000 603.880 849.000 604.480 ;
    END
  END arb_port_o[237]
  PIN arb_port_o[238]
    DIRECTION OUTPUT TRISTATE ;
    USE SIGNAL ;
    ANTENNADIFFAREA 2.673000 ;
    PORT
      LAYER met3 ;
        RECT 845.000 605.240 849.000 605.840 ;
    END
  END arb_port_o[238]
  PIN arb_port_o[239]
    DIRECTION OUTPUT TRISTATE ;
    USE SIGNAL ;
    ANTENNADIFFAREA 2.673000 ;
    PORT
      LAYER met3 ;
        RECT 845.000 606.600 849.000 607.200 ;
    END
  END arb_port_o[239]
  PIN arb_port_o[23]
    DIRECTION OUTPUT TRISTATE ;
    USE SIGNAL ;
    ANTENNADIFFAREA 2.673000 ;
    PORT
      LAYER met3 ;
        RECT 845.000 312.840 849.000 313.440 ;
    END
  END arb_port_o[23]
  PIN arb_port_o[240]
    DIRECTION OUTPUT TRISTATE ;
    USE SIGNAL ;
    ANTENNADIFFAREA 2.673000 ;
    PORT
      LAYER met3 ;
        RECT 845.000 607.960 849.000 608.560 ;
    END
  END arb_port_o[240]
  PIN arb_port_o[241]
    DIRECTION OUTPUT TRISTATE ;
    USE SIGNAL ;
    ANTENNADIFFAREA 2.673000 ;
    PORT
      LAYER met3 ;
        RECT 845.000 609.320 849.000 609.920 ;
    END
  END arb_port_o[241]
  PIN arb_port_o[242]
    DIRECTION OUTPUT TRISTATE ;
    USE SIGNAL ;
    ANTENNADIFFAREA 2.673000 ;
    PORT
      LAYER met3 ;
        RECT 845.000 610.680 849.000 611.280 ;
    END
  END arb_port_o[242]
  PIN arb_port_o[243]
    DIRECTION OUTPUT TRISTATE ;
    USE SIGNAL ;
    ANTENNADIFFAREA 2.673000 ;
    PORT
      LAYER met3 ;
        RECT 845.000 612.040 849.000 612.640 ;
    END
  END arb_port_o[243]
  PIN arb_port_o[244]
    DIRECTION OUTPUT TRISTATE ;
    USE SIGNAL ;
    ANTENNADIFFAREA 2.673000 ;
    PORT
      LAYER met3 ;
        RECT 845.000 613.400 849.000 614.000 ;
    END
  END arb_port_o[244]
  PIN arb_port_o[245]
    DIRECTION OUTPUT TRISTATE ;
    USE SIGNAL ;
    ANTENNADIFFAREA 2.673000 ;
    PORT
      LAYER met3 ;
        RECT 845.000 614.760 849.000 615.360 ;
    END
  END arb_port_o[245]
  PIN arb_port_o[246]
    DIRECTION OUTPUT TRISTATE ;
    USE SIGNAL ;
    ANTENNADIFFAREA 2.673000 ;
    PORT
      LAYER met3 ;
        RECT 845.000 616.120 849.000 616.720 ;
    END
  END arb_port_o[246]
  PIN arb_port_o[247]
    DIRECTION OUTPUT TRISTATE ;
    USE SIGNAL ;
    ANTENNADIFFAREA 2.673000 ;
    PORT
      LAYER met3 ;
        RECT 845.000 617.480 849.000 618.080 ;
    END
  END arb_port_o[247]
  PIN arb_port_o[248]
    DIRECTION OUTPUT TRISTATE ;
    USE SIGNAL ;
    ANTENNADIFFAREA 2.673000 ;
    PORT
      LAYER met3 ;
        RECT 845.000 618.840 849.000 619.440 ;
    END
  END arb_port_o[248]
  PIN arb_port_o[249]
    DIRECTION OUTPUT TRISTATE ;
    USE SIGNAL ;
    ANTENNADIFFAREA 2.673000 ;
    PORT
      LAYER met3 ;
        RECT 845.000 620.200 849.000 620.800 ;
    END
  END arb_port_o[249]
  PIN arb_port_o[24]
    DIRECTION OUTPUT TRISTATE ;
    USE SIGNAL ;
    ANTENNADIFFAREA 2.673000 ;
    PORT
      LAYER met3 ;
        RECT 845.000 314.200 849.000 314.800 ;
    END
  END arb_port_o[24]
  PIN arb_port_o[250]
    DIRECTION OUTPUT TRISTATE ;
    USE SIGNAL ;
    ANTENNADIFFAREA 2.673000 ;
    PORT
      LAYER met3 ;
        RECT 845.000 621.560 849.000 622.160 ;
    END
  END arb_port_o[250]
  PIN arb_port_o[251]
    DIRECTION OUTPUT TRISTATE ;
    USE SIGNAL ;
    ANTENNADIFFAREA 2.673000 ;
    PORT
      LAYER met3 ;
        RECT 845.000 622.920 849.000 623.520 ;
    END
  END arb_port_o[251]
  PIN arb_port_o[252]
    DIRECTION OUTPUT TRISTATE ;
    USE SIGNAL ;
    ANTENNADIFFAREA 2.673000 ;
    PORT
      LAYER met3 ;
        RECT 845.000 624.280 849.000 624.880 ;
    END
  END arb_port_o[252]
  PIN arb_port_o[253]
    DIRECTION OUTPUT TRISTATE ;
    USE SIGNAL ;
    ANTENNADIFFAREA 2.673000 ;
    PORT
      LAYER met3 ;
        RECT 845.000 625.640 849.000 626.240 ;
    END
  END arb_port_o[253]
  PIN arb_port_o[254]
    DIRECTION OUTPUT TRISTATE ;
    USE SIGNAL ;
    ANTENNADIFFAREA 2.673000 ;
    PORT
      LAYER met3 ;
        RECT 845.000 627.000 849.000 627.600 ;
    END
  END arb_port_o[254]
  PIN arb_port_o[255]
    DIRECTION OUTPUT TRISTATE ;
    USE SIGNAL ;
    ANTENNADIFFAREA 2.673000 ;
    PORT
      LAYER met3 ;
        RECT 845.000 628.360 849.000 628.960 ;
    END
  END arb_port_o[255]
  PIN arb_port_o[256]
    DIRECTION OUTPUT TRISTATE ;
    USE SIGNAL ;
    ANTENNADIFFAREA 2.673000 ;
    PORT
      LAYER met3 ;
        RECT 845.000 629.720 849.000 630.320 ;
    END
  END arb_port_o[256]
  PIN arb_port_o[257]
    DIRECTION OUTPUT TRISTATE ;
    USE SIGNAL ;
    ANTENNADIFFAREA 2.673000 ;
    PORT
      LAYER met3 ;
        RECT 845.000 631.080 849.000 631.680 ;
    END
  END arb_port_o[257]
  PIN arb_port_o[258]
    DIRECTION OUTPUT TRISTATE ;
    USE SIGNAL ;
    ANTENNADIFFAREA 2.673000 ;
    PORT
      LAYER met3 ;
        RECT 845.000 632.440 849.000 633.040 ;
    END
  END arb_port_o[258]
  PIN arb_port_o[259]
    DIRECTION OUTPUT TRISTATE ;
    USE SIGNAL ;
    ANTENNADIFFAREA 2.673000 ;
    PORT
      LAYER met3 ;
        RECT 845.000 633.800 849.000 634.400 ;
    END
  END arb_port_o[259]
  PIN arb_port_o[25]
    DIRECTION OUTPUT TRISTATE ;
    USE SIGNAL ;
    ANTENNADIFFAREA 2.673000 ;
    PORT
      LAYER met3 ;
        RECT 845.000 315.560 849.000 316.160 ;
    END
  END arb_port_o[25]
  PIN arb_port_o[260]
    DIRECTION OUTPUT TRISTATE ;
    USE SIGNAL ;
    ANTENNADIFFAREA 2.673000 ;
    PORT
      LAYER met3 ;
        RECT 845.000 635.160 849.000 635.760 ;
    END
  END arb_port_o[260]
  PIN arb_port_o[261]
    DIRECTION OUTPUT TRISTATE ;
    USE SIGNAL ;
    ANTENNADIFFAREA 2.673000 ;
    PORT
      LAYER met3 ;
        RECT 845.000 636.520 849.000 637.120 ;
    END
  END arb_port_o[261]
  PIN arb_port_o[262]
    DIRECTION OUTPUT TRISTATE ;
    USE SIGNAL ;
    ANTENNADIFFAREA 2.673000 ;
    PORT
      LAYER met3 ;
        RECT 845.000 637.880 849.000 638.480 ;
    END
  END arb_port_o[262]
  PIN arb_port_o[263]
    DIRECTION OUTPUT TRISTATE ;
    USE SIGNAL ;
    ANTENNADIFFAREA 2.673000 ;
    PORT
      LAYER met3 ;
        RECT 845.000 639.240 849.000 639.840 ;
    END
  END arb_port_o[263]
  PIN arb_port_o[264]
    DIRECTION OUTPUT TRISTATE ;
    USE SIGNAL ;
    ANTENNADIFFAREA 2.673000 ;
    PORT
      LAYER met3 ;
        RECT 845.000 640.600 849.000 641.200 ;
    END
  END arb_port_o[264]
  PIN arb_port_o[265]
    DIRECTION OUTPUT TRISTATE ;
    USE SIGNAL ;
    ANTENNADIFFAREA 2.673000 ;
    PORT
      LAYER met3 ;
        RECT 845.000 641.960 849.000 642.560 ;
    END
  END arb_port_o[265]
  PIN arb_port_o[266]
    DIRECTION OUTPUT TRISTATE ;
    USE SIGNAL ;
    ANTENNADIFFAREA 2.673000 ;
    PORT
      LAYER met3 ;
        RECT 845.000 643.320 849.000 643.920 ;
    END
  END arb_port_o[266]
  PIN arb_port_o[267]
    DIRECTION OUTPUT TRISTATE ;
    USE SIGNAL ;
    ANTENNADIFFAREA 2.673000 ;
    PORT
      LAYER met3 ;
        RECT 845.000 644.680 849.000 645.280 ;
    END
  END arb_port_o[267]
  PIN arb_port_o[268]
    DIRECTION OUTPUT TRISTATE ;
    USE SIGNAL ;
    ANTENNADIFFAREA 2.673000 ;
    PORT
      LAYER met3 ;
        RECT 845.000 646.040 849.000 646.640 ;
    END
  END arb_port_o[268]
  PIN arb_port_o[269]
    DIRECTION OUTPUT TRISTATE ;
    USE SIGNAL ;
    ANTENNADIFFAREA 2.673000 ;
    PORT
      LAYER met3 ;
        RECT 845.000 647.400 849.000 648.000 ;
    END
  END arb_port_o[269]
  PIN arb_port_o[26]
    DIRECTION OUTPUT TRISTATE ;
    USE SIGNAL ;
    ANTENNADIFFAREA 2.673000 ;
    PORT
      LAYER met3 ;
        RECT 845.000 316.920 849.000 317.520 ;
    END
  END arb_port_o[26]
  PIN arb_port_o[270]
    DIRECTION OUTPUT TRISTATE ;
    USE SIGNAL ;
    ANTENNADIFFAREA 2.673000 ;
    PORT
      LAYER met3 ;
        RECT 845.000 648.760 849.000 649.360 ;
    END
  END arb_port_o[270]
  PIN arb_port_o[271]
    DIRECTION OUTPUT TRISTATE ;
    USE SIGNAL ;
    ANTENNADIFFAREA 2.673000 ;
    PORT
      LAYER met3 ;
        RECT 845.000 650.120 849.000 650.720 ;
    END
  END arb_port_o[271]
  PIN arb_port_o[272]
    DIRECTION OUTPUT TRISTATE ;
    USE SIGNAL ;
    ANTENNADIFFAREA 2.673000 ;
    PORT
      LAYER met3 ;
        RECT 845.000 651.480 849.000 652.080 ;
    END
  END arb_port_o[272]
  PIN arb_port_o[273]
    DIRECTION OUTPUT TRISTATE ;
    USE SIGNAL ;
    ANTENNADIFFAREA 2.673000 ;
    PORT
      LAYER met3 ;
        RECT 845.000 652.840 849.000 653.440 ;
    END
  END arb_port_o[273]
  PIN arb_port_o[274]
    DIRECTION OUTPUT TRISTATE ;
    USE SIGNAL ;
    ANTENNADIFFAREA 2.673000 ;
    PORT
      LAYER met3 ;
        RECT 845.000 654.200 849.000 654.800 ;
    END
  END arb_port_o[274]
  PIN arb_port_o[275]
    DIRECTION OUTPUT TRISTATE ;
    USE SIGNAL ;
    ANTENNADIFFAREA 2.673000 ;
    PORT
      LAYER met3 ;
        RECT 845.000 655.560 849.000 656.160 ;
    END
  END arb_port_o[275]
  PIN arb_port_o[276]
    DIRECTION OUTPUT TRISTATE ;
    USE SIGNAL ;
    ANTENNADIFFAREA 2.673000 ;
    PORT
      LAYER met3 ;
        RECT 845.000 656.920 849.000 657.520 ;
    END
  END arb_port_o[276]
  PIN arb_port_o[277]
    DIRECTION OUTPUT TRISTATE ;
    USE SIGNAL ;
    ANTENNADIFFAREA 2.673000 ;
    PORT
      LAYER met3 ;
        RECT 845.000 658.280 849.000 658.880 ;
    END
  END arb_port_o[277]
  PIN arb_port_o[278]
    DIRECTION OUTPUT TRISTATE ;
    USE SIGNAL ;
    ANTENNADIFFAREA 2.673000 ;
    PORT
      LAYER met3 ;
        RECT 845.000 659.640 849.000 660.240 ;
    END
  END arb_port_o[278]
  PIN arb_port_o[279]
    DIRECTION OUTPUT TRISTATE ;
    USE SIGNAL ;
    ANTENNADIFFAREA 2.673000 ;
    PORT
      LAYER met3 ;
        RECT 845.000 661.000 849.000 661.600 ;
    END
  END arb_port_o[279]
  PIN arb_port_o[27]
    DIRECTION OUTPUT TRISTATE ;
    USE SIGNAL ;
    ANTENNADIFFAREA 2.673000 ;
    PORT
      LAYER met3 ;
        RECT 845.000 318.280 849.000 318.880 ;
    END
  END arb_port_o[27]
  PIN arb_port_o[280]
    DIRECTION OUTPUT TRISTATE ;
    USE SIGNAL ;
    ANTENNADIFFAREA 2.673000 ;
    PORT
      LAYER met3 ;
        RECT 845.000 662.360 849.000 662.960 ;
    END
  END arb_port_o[280]
  PIN arb_port_o[281]
    DIRECTION OUTPUT TRISTATE ;
    USE SIGNAL ;
    ANTENNADIFFAREA 2.673000 ;
    PORT
      LAYER met3 ;
        RECT 845.000 663.720 849.000 664.320 ;
    END
  END arb_port_o[281]
  PIN arb_port_o[282]
    DIRECTION OUTPUT TRISTATE ;
    USE SIGNAL ;
    ANTENNADIFFAREA 2.673000 ;
    PORT
      LAYER met3 ;
        RECT 845.000 665.080 849.000 665.680 ;
    END
  END arb_port_o[282]
  PIN arb_port_o[283]
    DIRECTION OUTPUT TRISTATE ;
    USE SIGNAL ;
    ANTENNADIFFAREA 2.673000 ;
    PORT
      LAYER met3 ;
        RECT 845.000 666.440 849.000 667.040 ;
    END
  END arb_port_o[283]
  PIN arb_port_o[284]
    DIRECTION OUTPUT TRISTATE ;
    USE SIGNAL ;
    ANTENNADIFFAREA 2.673000 ;
    PORT
      LAYER met3 ;
        RECT 845.000 667.800 849.000 668.400 ;
    END
  END arb_port_o[284]
  PIN arb_port_o[285]
    DIRECTION OUTPUT TRISTATE ;
    USE SIGNAL ;
    ANTENNADIFFAREA 2.673000 ;
    PORT
      LAYER met3 ;
        RECT 845.000 669.160 849.000 669.760 ;
    END
  END arb_port_o[285]
  PIN arb_port_o[286]
    DIRECTION OUTPUT TRISTATE ;
    USE SIGNAL ;
    ANTENNADIFFAREA 2.673000 ;
    PORT
      LAYER met3 ;
        RECT 845.000 670.520 849.000 671.120 ;
    END
  END arb_port_o[286]
  PIN arb_port_o[287]
    DIRECTION OUTPUT TRISTATE ;
    USE SIGNAL ;
    ANTENNADIFFAREA 2.673000 ;
    PORT
      LAYER met3 ;
        RECT 845.000 671.880 849.000 672.480 ;
    END
  END arb_port_o[287]
  PIN arb_port_o[288]
    DIRECTION OUTPUT TRISTATE ;
    USE SIGNAL ;
    ANTENNADIFFAREA 2.673000 ;
    PORT
      LAYER met3 ;
        RECT 845.000 673.240 849.000 673.840 ;
    END
  END arb_port_o[288]
  PIN arb_port_o[289]
    DIRECTION OUTPUT TRISTATE ;
    USE SIGNAL ;
    ANTENNADIFFAREA 2.673000 ;
    PORT
      LAYER met3 ;
        RECT 845.000 674.600 849.000 675.200 ;
    END
  END arb_port_o[289]
  PIN arb_port_o[28]
    DIRECTION OUTPUT TRISTATE ;
    USE SIGNAL ;
    ANTENNADIFFAREA 2.673000 ;
    PORT
      LAYER met3 ;
        RECT 845.000 319.640 849.000 320.240 ;
    END
  END arb_port_o[28]
  PIN arb_port_o[290]
    DIRECTION OUTPUT TRISTATE ;
    USE SIGNAL ;
    ANTENNADIFFAREA 2.673000 ;
    PORT
      LAYER met3 ;
        RECT 845.000 675.960 849.000 676.560 ;
    END
  END arb_port_o[290]
  PIN arb_port_o[291]
    DIRECTION OUTPUT TRISTATE ;
    USE SIGNAL ;
    ANTENNADIFFAREA 2.673000 ;
    PORT
      LAYER met3 ;
        RECT 845.000 677.320 849.000 677.920 ;
    END
  END arb_port_o[291]
  PIN arb_port_o[292]
    DIRECTION OUTPUT TRISTATE ;
    USE SIGNAL ;
    ANTENNADIFFAREA 2.673000 ;
    PORT
      LAYER met3 ;
        RECT 845.000 678.680 849.000 679.280 ;
    END
  END arb_port_o[292]
  PIN arb_port_o[293]
    DIRECTION OUTPUT TRISTATE ;
    USE SIGNAL ;
    ANTENNADIFFAREA 2.673000 ;
    PORT
      LAYER met3 ;
        RECT 845.000 680.040 849.000 680.640 ;
    END
  END arb_port_o[293]
  PIN arb_port_o[294]
    DIRECTION OUTPUT TRISTATE ;
    USE SIGNAL ;
    ANTENNADIFFAREA 2.673000 ;
    PORT
      LAYER met3 ;
        RECT 845.000 681.400 849.000 682.000 ;
    END
  END arb_port_o[294]
  PIN arb_port_o[295]
    DIRECTION OUTPUT TRISTATE ;
    USE SIGNAL ;
    ANTENNADIFFAREA 2.673000 ;
    PORT
      LAYER met3 ;
        RECT 845.000 682.760 849.000 683.360 ;
    END
  END arb_port_o[295]
  PIN arb_port_o[296]
    DIRECTION OUTPUT TRISTATE ;
    USE SIGNAL ;
    ANTENNADIFFAREA 2.673000 ;
    PORT
      LAYER met3 ;
        RECT 845.000 684.120 849.000 684.720 ;
    END
  END arb_port_o[296]
  PIN arb_port_o[297]
    DIRECTION OUTPUT TRISTATE ;
    USE SIGNAL ;
    ANTENNADIFFAREA 2.673000 ;
    PORT
      LAYER met3 ;
        RECT 845.000 685.480 849.000 686.080 ;
    END
  END arb_port_o[297]
  PIN arb_port_o[298]
    DIRECTION OUTPUT TRISTATE ;
    USE SIGNAL ;
    ANTENNADIFFAREA 2.673000 ;
    PORT
      LAYER met3 ;
        RECT 845.000 686.840 849.000 687.440 ;
    END
  END arb_port_o[298]
  PIN arb_port_o[299]
    DIRECTION OUTPUT TRISTATE ;
    USE SIGNAL ;
    ANTENNADIFFAREA 2.673000 ;
    PORT
      LAYER met3 ;
        RECT 845.000 688.200 849.000 688.800 ;
    END
  END arb_port_o[299]
  PIN arb_port_o[29]
    DIRECTION OUTPUT TRISTATE ;
    USE SIGNAL ;
    ANTENNADIFFAREA 2.673000 ;
    PORT
      LAYER met3 ;
        RECT 845.000 321.000 849.000 321.600 ;
    END
  END arb_port_o[29]
  PIN arb_port_o[2]
    DIRECTION OUTPUT TRISTATE ;
    USE SIGNAL ;
    ANTENNADIFFAREA 2.673000 ;
    PORT
      LAYER met3 ;
        RECT 845.000 284.280 849.000 284.880 ;
    END
  END arb_port_o[2]
  PIN arb_port_o[300]
    DIRECTION OUTPUT TRISTATE ;
    USE SIGNAL ;
    ANTENNADIFFAREA 2.673000 ;
    PORT
      LAYER met3 ;
        RECT 845.000 689.560 849.000 690.160 ;
    END
  END arb_port_o[300]
  PIN arb_port_o[301]
    DIRECTION OUTPUT TRISTATE ;
    USE SIGNAL ;
    ANTENNADIFFAREA 2.673000 ;
    PORT
      LAYER met3 ;
        RECT 845.000 690.920 849.000 691.520 ;
    END
  END arb_port_o[301]
  PIN arb_port_o[302]
    DIRECTION OUTPUT TRISTATE ;
    USE SIGNAL ;
    ANTENNADIFFAREA 2.673000 ;
    PORT
      LAYER met3 ;
        RECT 845.000 692.280 849.000 692.880 ;
    END
  END arb_port_o[302]
  PIN arb_port_o[303]
    DIRECTION OUTPUT TRISTATE ;
    USE SIGNAL ;
    ANTENNADIFFAREA 2.673000 ;
    PORT
      LAYER met3 ;
        RECT 845.000 693.640 849.000 694.240 ;
    END
  END arb_port_o[303]
  PIN arb_port_o[304]
    DIRECTION OUTPUT TRISTATE ;
    USE SIGNAL ;
    ANTENNADIFFAREA 2.673000 ;
    PORT
      LAYER met3 ;
        RECT 845.000 695.000 849.000 695.600 ;
    END
  END arb_port_o[304]
  PIN arb_port_o[305]
    DIRECTION OUTPUT TRISTATE ;
    USE SIGNAL ;
    ANTENNADIFFAREA 2.673000 ;
    PORT
      LAYER met3 ;
        RECT 845.000 696.360 849.000 696.960 ;
    END
  END arb_port_o[305]
  PIN arb_port_o[306]
    DIRECTION OUTPUT TRISTATE ;
    USE SIGNAL ;
    ANTENNADIFFAREA 2.673000 ;
    PORT
      LAYER met3 ;
        RECT 845.000 697.720 849.000 698.320 ;
    END
  END arb_port_o[306]
  PIN arb_port_o[307]
    DIRECTION OUTPUT TRISTATE ;
    USE SIGNAL ;
    ANTENNADIFFAREA 2.673000 ;
    PORT
      LAYER met3 ;
        RECT 845.000 699.080 849.000 699.680 ;
    END
  END arb_port_o[307]
  PIN arb_port_o[308]
    DIRECTION OUTPUT TRISTATE ;
    USE SIGNAL ;
    ANTENNADIFFAREA 2.673000 ;
    PORT
      LAYER met3 ;
        RECT 845.000 700.440 849.000 701.040 ;
    END
  END arb_port_o[308]
  PIN arb_port_o[309]
    DIRECTION OUTPUT TRISTATE ;
    USE SIGNAL ;
    ANTENNADIFFAREA 2.673000 ;
    PORT
      LAYER met3 ;
        RECT 845.000 701.800 849.000 702.400 ;
    END
  END arb_port_o[309]
  PIN arb_port_o[30]
    DIRECTION OUTPUT TRISTATE ;
    USE SIGNAL ;
    ANTENNADIFFAREA 2.673000 ;
    PORT
      LAYER met3 ;
        RECT 845.000 322.360 849.000 322.960 ;
    END
  END arb_port_o[30]
  PIN arb_port_o[310]
    DIRECTION OUTPUT TRISTATE ;
    USE SIGNAL ;
    ANTENNADIFFAREA 2.673000 ;
    PORT
      LAYER met3 ;
        RECT 845.000 703.160 849.000 703.760 ;
    END
  END arb_port_o[310]
  PIN arb_port_o[311]
    DIRECTION OUTPUT TRISTATE ;
    USE SIGNAL ;
    ANTENNADIFFAREA 2.673000 ;
    PORT
      LAYER met3 ;
        RECT 845.000 704.520 849.000 705.120 ;
    END
  END arb_port_o[311]
  PIN arb_port_o[312]
    DIRECTION OUTPUT TRISTATE ;
    USE SIGNAL ;
    ANTENNADIFFAREA 2.673000 ;
    PORT
      LAYER met3 ;
        RECT 845.000 705.880 849.000 706.480 ;
    END
  END arb_port_o[312]
  PIN arb_port_o[313]
    DIRECTION OUTPUT TRISTATE ;
    USE SIGNAL ;
    ANTENNADIFFAREA 2.673000 ;
    PORT
      LAYER met3 ;
        RECT 845.000 707.240 849.000 707.840 ;
    END
  END arb_port_o[313]
  PIN arb_port_o[314]
    DIRECTION OUTPUT TRISTATE ;
    USE SIGNAL ;
    ANTENNADIFFAREA 2.673000 ;
    PORT
      LAYER met3 ;
        RECT 845.000 708.600 849.000 709.200 ;
    END
  END arb_port_o[314]
  PIN arb_port_o[315]
    DIRECTION OUTPUT TRISTATE ;
    USE SIGNAL ;
    ANTENNADIFFAREA 2.673000 ;
    PORT
      LAYER met3 ;
        RECT 845.000 709.960 849.000 710.560 ;
    END
  END arb_port_o[315]
  PIN arb_port_o[316]
    DIRECTION OUTPUT TRISTATE ;
    USE SIGNAL ;
    ANTENNADIFFAREA 2.673000 ;
    PORT
      LAYER met3 ;
        RECT 845.000 711.320 849.000 711.920 ;
    END
  END arb_port_o[316]
  PIN arb_port_o[317]
    DIRECTION OUTPUT TRISTATE ;
    USE SIGNAL ;
    ANTENNADIFFAREA 2.673000 ;
    PORT
      LAYER met3 ;
        RECT 845.000 712.680 849.000 713.280 ;
    END
  END arb_port_o[317]
  PIN arb_port_o[318]
    DIRECTION OUTPUT TRISTATE ;
    USE SIGNAL ;
    ANTENNADIFFAREA 2.673000 ;
    PORT
      LAYER met3 ;
        RECT 845.000 714.040 849.000 714.640 ;
    END
  END arb_port_o[318]
  PIN arb_port_o[319]
    DIRECTION OUTPUT TRISTATE ;
    USE SIGNAL ;
    ANTENNADIFFAREA 2.673000 ;
    PORT
      LAYER met3 ;
        RECT 845.000 715.400 849.000 716.000 ;
    END
  END arb_port_o[319]
  PIN arb_port_o[31]
    DIRECTION OUTPUT TRISTATE ;
    USE SIGNAL ;
    ANTENNADIFFAREA 2.673000 ;
    PORT
      LAYER met3 ;
        RECT 845.000 323.720 849.000 324.320 ;
    END
  END arb_port_o[31]
  PIN arb_port_o[320]
    DIRECTION OUTPUT TRISTATE ;
    USE SIGNAL ;
    ANTENNADIFFAREA 2.673000 ;
    PORT
      LAYER met3 ;
        RECT 845.000 716.760 849.000 717.360 ;
    END
  END arb_port_o[320]
  PIN arb_port_o[321]
    DIRECTION OUTPUT TRISTATE ;
    USE SIGNAL ;
    ANTENNADIFFAREA 2.673000 ;
    PORT
      LAYER met3 ;
        RECT 845.000 718.120 849.000 718.720 ;
    END
  END arb_port_o[321]
  PIN arb_port_o[322]
    DIRECTION OUTPUT TRISTATE ;
    USE SIGNAL ;
    ANTENNADIFFAREA 2.673000 ;
    PORT
      LAYER met3 ;
        RECT 845.000 719.480 849.000 720.080 ;
    END
  END arb_port_o[322]
  PIN arb_port_o[323]
    DIRECTION OUTPUT TRISTATE ;
    USE SIGNAL ;
    ANTENNADIFFAREA 2.673000 ;
    PORT
      LAYER met3 ;
        RECT 845.000 720.840 849.000 721.440 ;
    END
  END arb_port_o[323]
  PIN arb_port_o[324]
    DIRECTION OUTPUT TRISTATE ;
    USE SIGNAL ;
    ANTENNADIFFAREA 2.673000 ;
    PORT
      LAYER met3 ;
        RECT 845.000 722.200 849.000 722.800 ;
    END
  END arb_port_o[324]
  PIN arb_port_o[325]
    DIRECTION OUTPUT TRISTATE ;
    USE SIGNAL ;
    ANTENNADIFFAREA 2.673000 ;
    PORT
      LAYER met3 ;
        RECT 845.000 723.560 849.000 724.160 ;
    END
  END arb_port_o[325]
  PIN arb_port_o[326]
    DIRECTION OUTPUT TRISTATE ;
    USE SIGNAL ;
    ANTENNADIFFAREA 2.673000 ;
    PORT
      LAYER met3 ;
        RECT 845.000 724.920 849.000 725.520 ;
    END
  END arb_port_o[326]
  PIN arb_port_o[327]
    DIRECTION OUTPUT TRISTATE ;
    USE SIGNAL ;
    ANTENNADIFFAREA 2.673000 ;
    PORT
      LAYER met3 ;
        RECT 845.000 726.280 849.000 726.880 ;
    END
  END arb_port_o[327]
  PIN arb_port_o[328]
    DIRECTION OUTPUT TRISTATE ;
    USE SIGNAL ;
    ANTENNADIFFAREA 2.673000 ;
    PORT
      LAYER met3 ;
        RECT 845.000 727.640 849.000 728.240 ;
    END
  END arb_port_o[328]
  PIN arb_port_o[329]
    DIRECTION OUTPUT TRISTATE ;
    USE SIGNAL ;
    ANTENNADIFFAREA 2.673000 ;
    PORT
      LAYER met3 ;
        RECT 845.000 729.000 849.000 729.600 ;
    END
  END arb_port_o[329]
  PIN arb_port_o[32]
    DIRECTION OUTPUT TRISTATE ;
    USE SIGNAL ;
    ANTENNADIFFAREA 2.673000 ;
    PORT
      LAYER met3 ;
        RECT 845.000 325.080 849.000 325.680 ;
    END
  END arb_port_o[32]
  PIN arb_port_o[330]
    DIRECTION OUTPUT TRISTATE ;
    USE SIGNAL ;
    ANTENNADIFFAREA 2.673000 ;
    PORT
      LAYER met3 ;
        RECT 845.000 730.360 849.000 730.960 ;
    END
  END arb_port_o[330]
  PIN arb_port_o[331]
    DIRECTION OUTPUT TRISTATE ;
    USE SIGNAL ;
    ANTENNADIFFAREA 2.673000 ;
    PORT
      LAYER met3 ;
        RECT 845.000 731.720 849.000 732.320 ;
    END
  END arb_port_o[331]
  PIN arb_port_o[332]
    DIRECTION OUTPUT TRISTATE ;
    USE SIGNAL ;
    ANTENNADIFFAREA 2.673000 ;
    PORT
      LAYER met3 ;
        RECT 845.000 733.080 849.000 733.680 ;
    END
  END arb_port_o[332]
  PIN arb_port_o[333]
    DIRECTION OUTPUT TRISTATE ;
    USE SIGNAL ;
    ANTENNADIFFAREA 2.673000 ;
    PORT
      LAYER met3 ;
        RECT 845.000 734.440 849.000 735.040 ;
    END
  END arb_port_o[333]
  PIN arb_port_o[334]
    DIRECTION OUTPUT TRISTATE ;
    USE SIGNAL ;
    ANTENNADIFFAREA 2.673000 ;
    PORT
      LAYER met3 ;
        RECT 845.000 735.800 849.000 736.400 ;
    END
  END arb_port_o[334]
  PIN arb_port_o[335]
    DIRECTION OUTPUT TRISTATE ;
    USE SIGNAL ;
    ANTENNADIFFAREA 2.673000 ;
    PORT
      LAYER met3 ;
        RECT 845.000 737.160 849.000 737.760 ;
    END
  END arb_port_o[335]
  PIN arb_port_o[336]
    DIRECTION OUTPUT TRISTATE ;
    USE SIGNAL ;
    ANTENNADIFFAREA 2.673000 ;
    PORT
      LAYER met3 ;
        RECT 845.000 738.520 849.000 739.120 ;
    END
  END arb_port_o[336]
  PIN arb_port_o[337]
    DIRECTION OUTPUT TRISTATE ;
    USE SIGNAL ;
    ANTENNADIFFAREA 2.673000 ;
    PORT
      LAYER met3 ;
        RECT 845.000 739.880 849.000 740.480 ;
    END
  END arb_port_o[337]
  PIN arb_port_o[338]
    DIRECTION OUTPUT TRISTATE ;
    USE SIGNAL ;
    ANTENNADIFFAREA 2.673000 ;
    PORT
      LAYER met3 ;
        RECT 845.000 741.240 849.000 741.840 ;
    END
  END arb_port_o[338]
  PIN arb_port_o[339]
    DIRECTION OUTPUT TRISTATE ;
    USE SIGNAL ;
    ANTENNADIFFAREA 2.673000 ;
    PORT
      LAYER met3 ;
        RECT 845.000 742.600 849.000 743.200 ;
    END
  END arb_port_o[339]
  PIN arb_port_o[33]
    DIRECTION OUTPUT TRISTATE ;
    USE SIGNAL ;
    ANTENNADIFFAREA 2.673000 ;
    PORT
      LAYER met3 ;
        RECT 845.000 326.440 849.000 327.040 ;
    END
  END arb_port_o[33]
  PIN arb_port_o[340]
    DIRECTION OUTPUT TRISTATE ;
    USE SIGNAL ;
    ANTENNADIFFAREA 2.673000 ;
    PORT
      LAYER met3 ;
        RECT 845.000 743.960 849.000 744.560 ;
    END
  END arb_port_o[340]
  PIN arb_port_o[341]
    DIRECTION OUTPUT TRISTATE ;
    USE SIGNAL ;
    ANTENNADIFFAREA 2.673000 ;
    PORT
      LAYER met3 ;
        RECT 845.000 745.320 849.000 745.920 ;
    END
  END arb_port_o[341]
  PIN arb_port_o[342]
    DIRECTION OUTPUT TRISTATE ;
    USE SIGNAL ;
    ANTENNADIFFAREA 2.673000 ;
    PORT
      LAYER met3 ;
        RECT 845.000 746.680 849.000 747.280 ;
    END
  END arb_port_o[342]
  PIN arb_port_o[343]
    DIRECTION OUTPUT TRISTATE ;
    USE SIGNAL ;
    ANTENNADIFFAREA 2.673000 ;
    PORT
      LAYER met3 ;
        RECT 845.000 748.040 849.000 748.640 ;
    END
  END arb_port_o[343]
  PIN arb_port_o[344]
    DIRECTION OUTPUT TRISTATE ;
    USE SIGNAL ;
    ANTENNADIFFAREA 2.673000 ;
    PORT
      LAYER met3 ;
        RECT 845.000 749.400 849.000 750.000 ;
    END
  END arb_port_o[344]
  PIN arb_port_o[345]
    DIRECTION OUTPUT TRISTATE ;
    USE SIGNAL ;
    ANTENNADIFFAREA 2.673000 ;
    PORT
      LAYER met3 ;
        RECT 845.000 750.760 849.000 751.360 ;
    END
  END arb_port_o[345]
  PIN arb_port_o[346]
    DIRECTION OUTPUT TRISTATE ;
    USE SIGNAL ;
    ANTENNADIFFAREA 2.673000 ;
    PORT
      LAYER met3 ;
        RECT 845.000 752.120 849.000 752.720 ;
    END
  END arb_port_o[346]
  PIN arb_port_o[347]
    DIRECTION OUTPUT TRISTATE ;
    USE SIGNAL ;
    ANTENNADIFFAREA 2.673000 ;
    PORT
      LAYER met3 ;
        RECT 845.000 753.480 849.000 754.080 ;
    END
  END arb_port_o[347]
  PIN arb_port_o[348]
    DIRECTION OUTPUT TRISTATE ;
    USE SIGNAL ;
    ANTENNADIFFAREA 2.673000 ;
    PORT
      LAYER met3 ;
        RECT 845.000 754.840 849.000 755.440 ;
    END
  END arb_port_o[348]
  PIN arb_port_o[349]
    DIRECTION OUTPUT TRISTATE ;
    USE SIGNAL ;
    ANTENNADIFFAREA 2.673000 ;
    PORT
      LAYER met3 ;
        RECT 845.000 756.200 849.000 756.800 ;
    END
  END arb_port_o[349]
  PIN arb_port_o[34]
    DIRECTION OUTPUT TRISTATE ;
    USE SIGNAL ;
    ANTENNADIFFAREA 2.673000 ;
    PORT
      LAYER met3 ;
        RECT 845.000 327.800 849.000 328.400 ;
    END
  END arb_port_o[34]
  PIN arb_port_o[350]
    DIRECTION OUTPUT TRISTATE ;
    USE SIGNAL ;
    ANTENNADIFFAREA 2.673000 ;
    PORT
      LAYER met3 ;
        RECT 845.000 757.560 849.000 758.160 ;
    END
  END arb_port_o[350]
  PIN arb_port_o[351]
    DIRECTION OUTPUT TRISTATE ;
    USE SIGNAL ;
    ANTENNADIFFAREA 2.673000 ;
    PORT
      LAYER met3 ;
        RECT 845.000 758.920 849.000 759.520 ;
    END
  END arb_port_o[351]
  PIN arb_port_o[352]
    DIRECTION OUTPUT TRISTATE ;
    USE SIGNAL ;
    ANTENNADIFFAREA 2.673000 ;
    PORT
      LAYER met3 ;
        RECT 845.000 760.280 849.000 760.880 ;
    END
  END arb_port_o[352]
  PIN arb_port_o[353]
    DIRECTION OUTPUT TRISTATE ;
    USE SIGNAL ;
    ANTENNADIFFAREA 2.673000 ;
    PORT
      LAYER met3 ;
        RECT 845.000 761.640 849.000 762.240 ;
    END
  END arb_port_o[353]
  PIN arb_port_o[354]
    DIRECTION OUTPUT TRISTATE ;
    USE SIGNAL ;
    ANTENNADIFFAREA 2.673000 ;
    PORT
      LAYER met3 ;
        RECT 845.000 763.000 849.000 763.600 ;
    END
  END arb_port_o[354]
  PIN arb_port_o[355]
    DIRECTION OUTPUT TRISTATE ;
    USE SIGNAL ;
    ANTENNADIFFAREA 2.673000 ;
    PORT
      LAYER met3 ;
        RECT 845.000 764.360 849.000 764.960 ;
    END
  END arb_port_o[355]
  PIN arb_port_o[356]
    DIRECTION OUTPUT TRISTATE ;
    USE SIGNAL ;
    ANTENNADIFFAREA 2.673000 ;
    PORT
      LAYER met3 ;
        RECT 845.000 765.720 849.000 766.320 ;
    END
  END arb_port_o[356]
  PIN arb_port_o[357]
    DIRECTION OUTPUT TRISTATE ;
    USE SIGNAL ;
    ANTENNADIFFAREA 2.673000 ;
    PORT
      LAYER met3 ;
        RECT 845.000 767.080 849.000 767.680 ;
    END
  END arb_port_o[357]
  PIN arb_port_o[358]
    DIRECTION OUTPUT TRISTATE ;
    USE SIGNAL ;
    ANTENNADIFFAREA 2.673000 ;
    PORT
      LAYER met3 ;
        RECT 845.000 768.440 849.000 769.040 ;
    END
  END arb_port_o[358]
  PIN arb_port_o[359]
    DIRECTION OUTPUT TRISTATE ;
    USE SIGNAL ;
    ANTENNADIFFAREA 2.673000 ;
    PORT
      LAYER met3 ;
        RECT 845.000 769.800 849.000 770.400 ;
    END
  END arb_port_o[359]
  PIN arb_port_o[35]
    DIRECTION OUTPUT TRISTATE ;
    USE SIGNAL ;
    ANTENNADIFFAREA 2.673000 ;
    PORT
      LAYER met3 ;
        RECT 845.000 329.160 849.000 329.760 ;
    END
  END arb_port_o[35]
  PIN arb_port_o[360]
    DIRECTION OUTPUT TRISTATE ;
    USE SIGNAL ;
    ANTENNADIFFAREA 2.673000 ;
    PORT
      LAYER met3 ;
        RECT 845.000 771.160 849.000 771.760 ;
    END
  END arb_port_o[360]
  PIN arb_port_o[361]
    DIRECTION OUTPUT TRISTATE ;
    USE SIGNAL ;
    ANTENNADIFFAREA 2.673000 ;
    PORT
      LAYER met3 ;
        RECT 845.000 772.520 849.000 773.120 ;
    END
  END arb_port_o[361]
  PIN arb_port_o[362]
    DIRECTION OUTPUT TRISTATE ;
    USE SIGNAL ;
    ANTENNADIFFAREA 2.673000 ;
    PORT
      LAYER met3 ;
        RECT 845.000 773.880 849.000 774.480 ;
    END
  END arb_port_o[362]
  PIN arb_port_o[363]
    DIRECTION OUTPUT TRISTATE ;
    USE SIGNAL ;
    ANTENNADIFFAREA 2.673000 ;
    PORT
      LAYER met3 ;
        RECT 845.000 775.240 849.000 775.840 ;
    END
  END arb_port_o[363]
  PIN arb_port_o[364]
    DIRECTION OUTPUT TRISTATE ;
    USE SIGNAL ;
    ANTENNADIFFAREA 2.673000 ;
    PORT
      LAYER met3 ;
        RECT 845.000 776.600 849.000 777.200 ;
    END
  END arb_port_o[364]
  PIN arb_port_o[365]
    DIRECTION OUTPUT TRISTATE ;
    USE SIGNAL ;
    ANTENNADIFFAREA 2.673000 ;
    PORT
      LAYER met3 ;
        RECT 845.000 777.960 849.000 778.560 ;
    END
  END arb_port_o[365]
  PIN arb_port_o[366]
    DIRECTION OUTPUT TRISTATE ;
    USE SIGNAL ;
    ANTENNADIFFAREA 2.673000 ;
    PORT
      LAYER met3 ;
        RECT 845.000 779.320 849.000 779.920 ;
    END
  END arb_port_o[366]
  PIN arb_port_o[367]
    DIRECTION OUTPUT TRISTATE ;
    USE SIGNAL ;
    ANTENNADIFFAREA 2.673000 ;
    PORT
      LAYER met3 ;
        RECT 845.000 780.680 849.000 781.280 ;
    END
  END arb_port_o[367]
  PIN arb_port_o[368]
    DIRECTION OUTPUT TRISTATE ;
    USE SIGNAL ;
    ANTENNADIFFAREA 2.673000 ;
    PORT
      LAYER met3 ;
        RECT 845.000 782.040 849.000 782.640 ;
    END
  END arb_port_o[368]
  PIN arb_port_o[369]
    DIRECTION OUTPUT TRISTATE ;
    USE SIGNAL ;
    ANTENNADIFFAREA 2.673000 ;
    PORT
      LAYER met3 ;
        RECT 845.000 783.400 849.000 784.000 ;
    END
  END arb_port_o[369]
  PIN arb_port_o[36]
    DIRECTION OUTPUT TRISTATE ;
    USE SIGNAL ;
    ANTENNADIFFAREA 2.673000 ;
    PORT
      LAYER met3 ;
        RECT 845.000 330.520 849.000 331.120 ;
    END
  END arb_port_o[36]
  PIN arb_port_o[370]
    DIRECTION OUTPUT TRISTATE ;
    USE SIGNAL ;
    ANTENNADIFFAREA 2.673000 ;
    PORT
      LAYER met3 ;
        RECT 845.000 784.760 849.000 785.360 ;
    END
  END arb_port_o[370]
  PIN arb_port_o[371]
    DIRECTION OUTPUT TRISTATE ;
    USE SIGNAL ;
    ANTENNADIFFAREA 2.673000 ;
    PORT
      LAYER met3 ;
        RECT 845.000 786.120 849.000 786.720 ;
    END
  END arb_port_o[371]
  PIN arb_port_o[372]
    DIRECTION OUTPUT TRISTATE ;
    USE SIGNAL ;
    ANTENNADIFFAREA 2.673000 ;
    PORT
      LAYER met3 ;
        RECT 845.000 787.480 849.000 788.080 ;
    END
  END arb_port_o[372]
  PIN arb_port_o[373]
    DIRECTION OUTPUT TRISTATE ;
    USE SIGNAL ;
    ANTENNADIFFAREA 2.673000 ;
    PORT
      LAYER met3 ;
        RECT 845.000 788.840 849.000 789.440 ;
    END
  END arb_port_o[373]
  PIN arb_port_o[374]
    DIRECTION OUTPUT TRISTATE ;
    USE SIGNAL ;
    ANTENNADIFFAREA 2.673000 ;
    PORT
      LAYER met3 ;
        RECT 845.000 790.200 849.000 790.800 ;
    END
  END arb_port_o[374]
  PIN arb_port_o[375]
    DIRECTION OUTPUT TRISTATE ;
    USE SIGNAL ;
    ANTENNADIFFAREA 2.673000 ;
    PORT
      LAYER met3 ;
        RECT 845.000 791.560 849.000 792.160 ;
    END
  END arb_port_o[375]
  PIN arb_port_o[376]
    DIRECTION OUTPUT TRISTATE ;
    USE SIGNAL ;
    ANTENNADIFFAREA 2.673000 ;
    PORT
      LAYER met3 ;
        RECT 845.000 792.920 849.000 793.520 ;
    END
  END arb_port_o[376]
  PIN arb_port_o[377]
    DIRECTION OUTPUT TRISTATE ;
    USE SIGNAL ;
    ANTENNADIFFAREA 2.673000 ;
    PORT
      LAYER met3 ;
        RECT 845.000 794.280 849.000 794.880 ;
    END
  END arb_port_o[377]
  PIN arb_port_o[378]
    DIRECTION OUTPUT TRISTATE ;
    USE SIGNAL ;
    ANTENNADIFFAREA 2.673000 ;
    PORT
      LAYER met3 ;
        RECT 845.000 795.640 849.000 796.240 ;
    END
  END arb_port_o[378]
  PIN arb_port_o[379]
    DIRECTION OUTPUT TRISTATE ;
    USE SIGNAL ;
    ANTENNADIFFAREA 2.673000 ;
    PORT
      LAYER met3 ;
        RECT 845.000 797.000 849.000 797.600 ;
    END
  END arb_port_o[379]
  PIN arb_port_o[37]
    DIRECTION OUTPUT TRISTATE ;
    USE SIGNAL ;
    ANTENNADIFFAREA 2.673000 ;
    PORT
      LAYER met3 ;
        RECT 845.000 331.880 849.000 332.480 ;
    END
  END arb_port_o[37]
  PIN arb_port_o[380]
    DIRECTION OUTPUT TRISTATE ;
    USE SIGNAL ;
    ANTENNADIFFAREA 2.673000 ;
    PORT
      LAYER met3 ;
        RECT 845.000 798.360 849.000 798.960 ;
    END
  END arb_port_o[380]
  PIN arb_port_o[381]
    DIRECTION OUTPUT TRISTATE ;
    USE SIGNAL ;
    ANTENNADIFFAREA 2.673000 ;
    PORT
      LAYER met3 ;
        RECT 845.000 799.720 849.000 800.320 ;
    END
  END arb_port_o[381]
  PIN arb_port_o[382]
    DIRECTION OUTPUT TRISTATE ;
    USE SIGNAL ;
    ANTENNADIFFAREA 2.673000 ;
    PORT
      LAYER met3 ;
        RECT 845.000 801.080 849.000 801.680 ;
    END
  END arb_port_o[382]
  PIN arb_port_o[383]
    DIRECTION OUTPUT TRISTATE ;
    USE SIGNAL ;
    ANTENNADIFFAREA 2.673000 ;
    PORT
      LAYER met3 ;
        RECT 845.000 802.440 849.000 803.040 ;
    END
  END arb_port_o[383]
  PIN arb_port_o[384]
    DIRECTION OUTPUT TRISTATE ;
    USE SIGNAL ;
    ANTENNADIFFAREA 2.673000 ;
    PORT
      LAYER met3 ;
        RECT 845.000 803.800 849.000 804.400 ;
    END
  END arb_port_o[384]
  PIN arb_port_o[385]
    DIRECTION OUTPUT TRISTATE ;
    USE SIGNAL ;
    ANTENNADIFFAREA 2.673000 ;
    PORT
      LAYER met3 ;
        RECT 845.000 805.160 849.000 805.760 ;
    END
  END arb_port_o[385]
  PIN arb_port_o[386]
    DIRECTION OUTPUT TRISTATE ;
    USE SIGNAL ;
    ANTENNADIFFAREA 2.673000 ;
    PORT
      LAYER met3 ;
        RECT 845.000 806.520 849.000 807.120 ;
    END
  END arb_port_o[386]
  PIN arb_port_o[387]
    DIRECTION OUTPUT TRISTATE ;
    USE SIGNAL ;
    ANTENNADIFFAREA 2.673000 ;
    PORT
      LAYER met3 ;
        RECT 845.000 807.880 849.000 808.480 ;
    END
  END arb_port_o[387]
  PIN arb_port_o[388]
    DIRECTION OUTPUT TRISTATE ;
    USE SIGNAL ;
    ANTENNADIFFAREA 2.673000 ;
    PORT
      LAYER met3 ;
        RECT 845.000 809.240 849.000 809.840 ;
    END
  END arb_port_o[388]
  PIN arb_port_o[389]
    DIRECTION OUTPUT TRISTATE ;
    USE SIGNAL ;
    ANTENNADIFFAREA 2.673000 ;
    PORT
      LAYER met3 ;
        RECT 845.000 810.600 849.000 811.200 ;
    END
  END arb_port_o[389]
  PIN arb_port_o[38]
    DIRECTION OUTPUT TRISTATE ;
    USE SIGNAL ;
    ANTENNADIFFAREA 2.673000 ;
    PORT
      LAYER met3 ;
        RECT 845.000 333.240 849.000 333.840 ;
    END
  END arb_port_o[38]
  PIN arb_port_o[390]
    DIRECTION OUTPUT TRISTATE ;
    USE SIGNAL ;
    ANTENNADIFFAREA 2.673000 ;
    PORT
      LAYER met3 ;
        RECT 845.000 811.960 849.000 812.560 ;
    END
  END arb_port_o[390]
  PIN arb_port_o[391]
    DIRECTION OUTPUT TRISTATE ;
    USE SIGNAL ;
    ANTENNADIFFAREA 2.673000 ;
    PORT
      LAYER met3 ;
        RECT 845.000 813.320 849.000 813.920 ;
    END
  END arb_port_o[391]
  PIN arb_port_o[392]
    DIRECTION OUTPUT TRISTATE ;
    USE SIGNAL ;
    ANTENNADIFFAREA 2.673000 ;
    PORT
      LAYER met3 ;
        RECT 845.000 814.680 849.000 815.280 ;
    END
  END arb_port_o[392]
  PIN arb_port_o[393]
    DIRECTION OUTPUT TRISTATE ;
    USE SIGNAL ;
    ANTENNADIFFAREA 2.673000 ;
    PORT
      LAYER met3 ;
        RECT 845.000 816.040 849.000 816.640 ;
    END
  END arb_port_o[393]
  PIN arb_port_o[394]
    DIRECTION OUTPUT TRISTATE ;
    USE SIGNAL ;
    ANTENNADIFFAREA 2.673000 ;
    PORT
      LAYER met3 ;
        RECT 845.000 817.400 849.000 818.000 ;
    END
  END arb_port_o[394]
  PIN arb_port_o[395]
    DIRECTION OUTPUT TRISTATE ;
    USE SIGNAL ;
    ANTENNADIFFAREA 2.673000 ;
    PORT
      LAYER met3 ;
        RECT 845.000 818.760 849.000 819.360 ;
    END
  END arb_port_o[395]
  PIN arb_port_o[396]
    DIRECTION OUTPUT TRISTATE ;
    USE SIGNAL ;
    ANTENNADIFFAREA 2.673000 ;
    PORT
      LAYER met3 ;
        RECT 845.000 820.120 849.000 820.720 ;
    END
  END arb_port_o[396]
  PIN arb_port_o[397]
    DIRECTION OUTPUT TRISTATE ;
    USE SIGNAL ;
    ANTENNADIFFAREA 2.673000 ;
    PORT
      LAYER met3 ;
        RECT 845.000 821.480 849.000 822.080 ;
    END
  END arb_port_o[397]
  PIN arb_port_o[398]
    DIRECTION OUTPUT TRISTATE ;
    USE SIGNAL ;
    ANTENNADIFFAREA 2.673000 ;
    PORT
      LAYER met3 ;
        RECT 845.000 822.840 849.000 823.440 ;
    END
  END arb_port_o[398]
  PIN arb_port_o[399]
    DIRECTION OUTPUT TRISTATE ;
    USE SIGNAL ;
    ANTENNADIFFAREA 2.673000 ;
    PORT
      LAYER met3 ;
        RECT 845.000 824.200 849.000 824.800 ;
    END
  END arb_port_o[399]
  PIN arb_port_o[39]
    DIRECTION OUTPUT TRISTATE ;
    USE SIGNAL ;
    ANTENNADIFFAREA 2.673000 ;
    PORT
      LAYER met3 ;
        RECT 845.000 334.600 849.000 335.200 ;
    END
  END arb_port_o[39]
  PIN arb_port_o[3]
    DIRECTION OUTPUT TRISTATE ;
    USE SIGNAL ;
    ANTENNADIFFAREA 2.673000 ;
    PORT
      LAYER met3 ;
        RECT 845.000 285.640 849.000 286.240 ;
    END
  END arb_port_o[3]
  PIN arb_port_o[400]
    DIRECTION OUTPUT TRISTATE ;
    USE SIGNAL ;
    ANTENNADIFFAREA 2.673000 ;
    PORT
      LAYER met3 ;
        RECT 845.000 825.560 849.000 826.160 ;
    END
  END arb_port_o[400]
  PIN arb_port_o[401]
    DIRECTION OUTPUT TRISTATE ;
    USE SIGNAL ;
    ANTENNADIFFAREA 2.673000 ;
    PORT
      LAYER met3 ;
        RECT 845.000 826.920 849.000 827.520 ;
    END
  END arb_port_o[401]
  PIN arb_port_o[402]
    DIRECTION OUTPUT TRISTATE ;
    USE SIGNAL ;
    ANTENNADIFFAREA 2.673000 ;
    PORT
      LAYER met3 ;
        RECT 845.000 828.280 849.000 828.880 ;
    END
  END arb_port_o[402]
  PIN arb_port_o[403]
    DIRECTION OUTPUT TRISTATE ;
    USE SIGNAL ;
    ANTENNADIFFAREA 2.673000 ;
    PORT
      LAYER met3 ;
        RECT 845.000 829.640 849.000 830.240 ;
    END
  END arb_port_o[403]
  PIN arb_port_o[404]
    DIRECTION OUTPUT TRISTATE ;
    USE SIGNAL ;
    ANTENNADIFFAREA 2.673000 ;
    PORT
      LAYER met3 ;
        RECT 845.000 831.000 849.000 831.600 ;
    END
  END arb_port_o[404]
  PIN arb_port_o[405]
    DIRECTION OUTPUT TRISTATE ;
    USE SIGNAL ;
    ANTENNADIFFAREA 2.673000 ;
    PORT
      LAYER met3 ;
        RECT 845.000 832.360 849.000 832.960 ;
    END
  END arb_port_o[405]
  PIN arb_port_o[406]
    DIRECTION OUTPUT TRISTATE ;
    USE SIGNAL ;
    ANTENNADIFFAREA 2.673000 ;
    PORT
      LAYER met3 ;
        RECT 845.000 833.720 849.000 834.320 ;
    END
  END arb_port_o[406]
  PIN arb_port_o[407]
    DIRECTION OUTPUT TRISTATE ;
    USE SIGNAL ;
    ANTENNADIFFAREA 2.673000 ;
    PORT
      LAYER met3 ;
        RECT 845.000 835.080 849.000 835.680 ;
    END
  END arb_port_o[407]
  PIN arb_port_o[408]
    DIRECTION OUTPUT TRISTATE ;
    USE SIGNAL ;
    ANTENNADIFFAREA 2.673000 ;
    PORT
      LAYER met3 ;
        RECT 845.000 836.440 849.000 837.040 ;
    END
  END arb_port_o[408]
  PIN arb_port_o[409]
    DIRECTION OUTPUT TRISTATE ;
    USE SIGNAL ;
    ANTENNADIFFAREA 2.673000 ;
    PORT
      LAYER met3 ;
        RECT 845.000 837.800 849.000 838.400 ;
    END
  END arb_port_o[409]
  PIN arb_port_o[40]
    DIRECTION OUTPUT TRISTATE ;
    USE SIGNAL ;
    ANTENNADIFFAREA 2.673000 ;
    PORT
      LAYER met3 ;
        RECT 845.000 335.960 849.000 336.560 ;
    END
  END arb_port_o[40]
  PIN arb_port_o[410]
    DIRECTION OUTPUT TRISTATE ;
    USE SIGNAL ;
    ANTENNADIFFAREA 2.673000 ;
    PORT
      LAYER met3 ;
        RECT 845.000 839.160 849.000 839.760 ;
    END
  END arb_port_o[410]
  PIN arb_port_o[411]
    DIRECTION OUTPUT TRISTATE ;
    USE SIGNAL ;
    ANTENNADIFFAREA 2.673000 ;
    PORT
      LAYER met3 ;
        RECT 845.000 840.520 849.000 841.120 ;
    END
  END arb_port_o[411]
  PIN arb_port_o[412]
    DIRECTION OUTPUT TRISTATE ;
    USE SIGNAL ;
    ANTENNADIFFAREA 2.673000 ;
    PORT
      LAYER met3 ;
        RECT 845.000 841.880 849.000 842.480 ;
    END
  END arb_port_o[412]
  PIN arb_port_o[413]
    DIRECTION OUTPUT TRISTATE ;
    USE SIGNAL ;
    ANTENNADIFFAREA 2.673000 ;
    PORT
      LAYER met3 ;
        RECT 845.000 843.240 849.000 843.840 ;
    END
  END arb_port_o[413]
  PIN arb_port_o[41]
    DIRECTION OUTPUT TRISTATE ;
    USE SIGNAL ;
    ANTENNADIFFAREA 2.673000 ;
    PORT
      LAYER met3 ;
        RECT 845.000 337.320 849.000 337.920 ;
    END
  END arb_port_o[41]
  PIN arb_port_o[42]
    DIRECTION OUTPUT TRISTATE ;
    USE SIGNAL ;
    ANTENNADIFFAREA 2.673000 ;
    PORT
      LAYER met3 ;
        RECT 845.000 338.680 849.000 339.280 ;
    END
  END arb_port_o[42]
  PIN arb_port_o[43]
    DIRECTION OUTPUT TRISTATE ;
    USE SIGNAL ;
    ANTENNADIFFAREA 2.673000 ;
    PORT
      LAYER met3 ;
        RECT 845.000 340.040 849.000 340.640 ;
    END
  END arb_port_o[43]
  PIN arb_port_o[44]
    DIRECTION OUTPUT TRISTATE ;
    USE SIGNAL ;
    ANTENNADIFFAREA 2.673000 ;
    PORT
      LAYER met3 ;
        RECT 845.000 341.400 849.000 342.000 ;
    END
  END arb_port_o[44]
  PIN arb_port_o[45]
    DIRECTION OUTPUT TRISTATE ;
    USE SIGNAL ;
    ANTENNADIFFAREA 2.673000 ;
    PORT
      LAYER met3 ;
        RECT 845.000 342.760 849.000 343.360 ;
    END
  END arb_port_o[45]
  PIN arb_port_o[46]
    DIRECTION OUTPUT TRISTATE ;
    USE SIGNAL ;
    ANTENNADIFFAREA 2.673000 ;
    PORT
      LAYER met3 ;
        RECT 845.000 344.120 849.000 344.720 ;
    END
  END arb_port_o[46]
  PIN arb_port_o[47]
    DIRECTION OUTPUT TRISTATE ;
    USE SIGNAL ;
    ANTENNADIFFAREA 2.673000 ;
    PORT
      LAYER met3 ;
        RECT 845.000 345.480 849.000 346.080 ;
    END
  END arb_port_o[47]
  PIN arb_port_o[48]
    DIRECTION OUTPUT TRISTATE ;
    USE SIGNAL ;
    ANTENNADIFFAREA 2.673000 ;
    PORT
      LAYER met3 ;
        RECT 845.000 346.840 849.000 347.440 ;
    END
  END arb_port_o[48]
  PIN arb_port_o[49]
    DIRECTION OUTPUT TRISTATE ;
    USE SIGNAL ;
    ANTENNADIFFAREA 2.673000 ;
    PORT
      LAYER met3 ;
        RECT 845.000 348.200 849.000 348.800 ;
    END
  END arb_port_o[49]
  PIN arb_port_o[4]
    DIRECTION OUTPUT TRISTATE ;
    USE SIGNAL ;
    ANTENNADIFFAREA 2.673000 ;
    PORT
      LAYER met3 ;
        RECT 845.000 287.000 849.000 287.600 ;
    END
  END arb_port_o[4]
  PIN arb_port_o[50]
    DIRECTION OUTPUT TRISTATE ;
    USE SIGNAL ;
    ANTENNADIFFAREA 2.673000 ;
    PORT
      LAYER met3 ;
        RECT 845.000 349.560 849.000 350.160 ;
    END
  END arb_port_o[50]
  PIN arb_port_o[51]
    DIRECTION OUTPUT TRISTATE ;
    USE SIGNAL ;
    ANTENNADIFFAREA 2.673000 ;
    PORT
      LAYER met3 ;
        RECT 845.000 350.920 849.000 351.520 ;
    END
  END arb_port_o[51]
  PIN arb_port_o[52]
    DIRECTION OUTPUT TRISTATE ;
    USE SIGNAL ;
    ANTENNADIFFAREA 2.673000 ;
    PORT
      LAYER met3 ;
        RECT 845.000 352.280 849.000 352.880 ;
    END
  END arb_port_o[52]
  PIN arb_port_o[53]
    DIRECTION OUTPUT TRISTATE ;
    USE SIGNAL ;
    ANTENNADIFFAREA 2.673000 ;
    PORT
      LAYER met3 ;
        RECT 845.000 353.640 849.000 354.240 ;
    END
  END arb_port_o[53]
  PIN arb_port_o[54]
    DIRECTION OUTPUT TRISTATE ;
    USE SIGNAL ;
    ANTENNADIFFAREA 2.673000 ;
    PORT
      LAYER met3 ;
        RECT 845.000 355.000 849.000 355.600 ;
    END
  END arb_port_o[54]
  PIN arb_port_o[55]
    DIRECTION OUTPUT TRISTATE ;
    USE SIGNAL ;
    ANTENNADIFFAREA 2.673000 ;
    PORT
      LAYER met3 ;
        RECT 845.000 356.360 849.000 356.960 ;
    END
  END arb_port_o[55]
  PIN arb_port_o[56]
    DIRECTION OUTPUT TRISTATE ;
    USE SIGNAL ;
    ANTENNADIFFAREA 2.673000 ;
    PORT
      LAYER met3 ;
        RECT 845.000 357.720 849.000 358.320 ;
    END
  END arb_port_o[56]
  PIN arb_port_o[57]
    DIRECTION OUTPUT TRISTATE ;
    USE SIGNAL ;
    ANTENNADIFFAREA 2.673000 ;
    PORT
      LAYER met3 ;
        RECT 845.000 359.080 849.000 359.680 ;
    END
  END arb_port_o[57]
  PIN arb_port_o[58]
    DIRECTION OUTPUT TRISTATE ;
    USE SIGNAL ;
    ANTENNADIFFAREA 2.673000 ;
    PORT
      LAYER met3 ;
        RECT 845.000 360.440 849.000 361.040 ;
    END
  END arb_port_o[58]
  PIN arb_port_o[59]
    DIRECTION OUTPUT TRISTATE ;
    USE SIGNAL ;
    ANTENNADIFFAREA 2.673000 ;
    PORT
      LAYER met3 ;
        RECT 845.000 361.800 849.000 362.400 ;
    END
  END arb_port_o[59]
  PIN arb_port_o[5]
    DIRECTION OUTPUT TRISTATE ;
    USE SIGNAL ;
    ANTENNADIFFAREA 2.673000 ;
    PORT
      LAYER met3 ;
        RECT 845.000 288.360 849.000 288.960 ;
    END
  END arb_port_o[5]
  PIN arb_port_o[60]
    DIRECTION OUTPUT TRISTATE ;
    USE SIGNAL ;
    ANTENNADIFFAREA 2.673000 ;
    PORT
      LAYER met3 ;
        RECT 845.000 363.160 849.000 363.760 ;
    END
  END arb_port_o[60]
  PIN arb_port_o[61]
    DIRECTION OUTPUT TRISTATE ;
    USE SIGNAL ;
    ANTENNADIFFAREA 2.673000 ;
    PORT
      LAYER met3 ;
        RECT 845.000 364.520 849.000 365.120 ;
    END
  END arb_port_o[61]
  PIN arb_port_o[62]
    DIRECTION OUTPUT TRISTATE ;
    USE SIGNAL ;
    ANTENNADIFFAREA 2.673000 ;
    PORT
      LAYER met3 ;
        RECT 845.000 365.880 849.000 366.480 ;
    END
  END arb_port_o[62]
  PIN arb_port_o[63]
    DIRECTION OUTPUT TRISTATE ;
    USE SIGNAL ;
    ANTENNADIFFAREA 2.673000 ;
    PORT
      LAYER met3 ;
        RECT 845.000 367.240 849.000 367.840 ;
    END
  END arb_port_o[63]
  PIN arb_port_o[64]
    DIRECTION OUTPUT TRISTATE ;
    USE SIGNAL ;
    ANTENNADIFFAREA 2.673000 ;
    PORT
      LAYER met3 ;
        RECT 845.000 368.600 849.000 369.200 ;
    END
  END arb_port_o[64]
  PIN arb_port_o[65]
    DIRECTION OUTPUT TRISTATE ;
    USE SIGNAL ;
    ANTENNADIFFAREA 2.673000 ;
    PORT
      LAYER met3 ;
        RECT 845.000 369.960 849.000 370.560 ;
    END
  END arb_port_o[65]
  PIN arb_port_o[66]
    DIRECTION OUTPUT TRISTATE ;
    USE SIGNAL ;
    ANTENNADIFFAREA 2.673000 ;
    PORT
      LAYER met3 ;
        RECT 845.000 371.320 849.000 371.920 ;
    END
  END arb_port_o[66]
  PIN arb_port_o[67]
    DIRECTION OUTPUT TRISTATE ;
    USE SIGNAL ;
    ANTENNADIFFAREA 2.673000 ;
    PORT
      LAYER met3 ;
        RECT 845.000 372.680 849.000 373.280 ;
    END
  END arb_port_o[67]
  PIN arb_port_o[68]
    DIRECTION OUTPUT TRISTATE ;
    USE SIGNAL ;
    ANTENNADIFFAREA 2.673000 ;
    PORT
      LAYER met3 ;
        RECT 845.000 374.040 849.000 374.640 ;
    END
  END arb_port_o[68]
  PIN arb_port_o[69]
    DIRECTION OUTPUT TRISTATE ;
    USE SIGNAL ;
    ANTENNADIFFAREA 2.673000 ;
    PORT
      LAYER met3 ;
        RECT 845.000 375.400 849.000 376.000 ;
    END
  END arb_port_o[69]
  PIN arb_port_o[6]
    DIRECTION OUTPUT TRISTATE ;
    USE SIGNAL ;
    ANTENNADIFFAREA 2.673000 ;
    PORT
      LAYER met3 ;
        RECT 845.000 289.720 849.000 290.320 ;
    END
  END arb_port_o[6]
  PIN arb_port_o[70]
    DIRECTION OUTPUT TRISTATE ;
    USE SIGNAL ;
    ANTENNADIFFAREA 2.673000 ;
    PORT
      LAYER met3 ;
        RECT 845.000 376.760 849.000 377.360 ;
    END
  END arb_port_o[70]
  PIN arb_port_o[71]
    DIRECTION OUTPUT TRISTATE ;
    USE SIGNAL ;
    ANTENNADIFFAREA 2.673000 ;
    PORT
      LAYER met3 ;
        RECT 845.000 378.120 849.000 378.720 ;
    END
  END arb_port_o[71]
  PIN arb_port_o[72]
    DIRECTION OUTPUT TRISTATE ;
    USE SIGNAL ;
    ANTENNADIFFAREA 2.673000 ;
    PORT
      LAYER met3 ;
        RECT 845.000 379.480 849.000 380.080 ;
    END
  END arb_port_o[72]
  PIN arb_port_o[73]
    DIRECTION OUTPUT TRISTATE ;
    USE SIGNAL ;
    ANTENNADIFFAREA 2.673000 ;
    PORT
      LAYER met3 ;
        RECT 845.000 380.840 849.000 381.440 ;
    END
  END arb_port_o[73]
  PIN arb_port_o[74]
    DIRECTION OUTPUT TRISTATE ;
    USE SIGNAL ;
    ANTENNADIFFAREA 2.673000 ;
    PORT
      LAYER met3 ;
        RECT 845.000 382.200 849.000 382.800 ;
    END
  END arb_port_o[74]
  PIN arb_port_o[75]
    DIRECTION OUTPUT TRISTATE ;
    USE SIGNAL ;
    ANTENNADIFFAREA 2.673000 ;
    PORT
      LAYER met3 ;
        RECT 845.000 383.560 849.000 384.160 ;
    END
  END arb_port_o[75]
  PIN arb_port_o[76]
    DIRECTION OUTPUT TRISTATE ;
    USE SIGNAL ;
    ANTENNADIFFAREA 2.673000 ;
    PORT
      LAYER met3 ;
        RECT 845.000 384.920 849.000 385.520 ;
    END
  END arb_port_o[76]
  PIN arb_port_o[77]
    DIRECTION OUTPUT TRISTATE ;
    USE SIGNAL ;
    ANTENNADIFFAREA 2.673000 ;
    PORT
      LAYER met3 ;
        RECT 845.000 386.280 849.000 386.880 ;
    END
  END arb_port_o[77]
  PIN arb_port_o[78]
    DIRECTION OUTPUT TRISTATE ;
    USE SIGNAL ;
    ANTENNADIFFAREA 2.673000 ;
    PORT
      LAYER met3 ;
        RECT 845.000 387.640 849.000 388.240 ;
    END
  END arb_port_o[78]
  PIN arb_port_o[79]
    DIRECTION OUTPUT TRISTATE ;
    USE SIGNAL ;
    ANTENNADIFFAREA 2.673000 ;
    PORT
      LAYER met3 ;
        RECT 845.000 389.000 849.000 389.600 ;
    END
  END arb_port_o[79]
  PIN arb_port_o[7]
    DIRECTION OUTPUT TRISTATE ;
    USE SIGNAL ;
    ANTENNADIFFAREA 2.673000 ;
    PORT
      LAYER met3 ;
        RECT 845.000 291.080 849.000 291.680 ;
    END
  END arb_port_o[7]
  PIN arb_port_o[80]
    DIRECTION OUTPUT TRISTATE ;
    USE SIGNAL ;
    ANTENNADIFFAREA 2.673000 ;
    PORT
      LAYER met3 ;
        RECT 845.000 390.360 849.000 390.960 ;
    END
  END arb_port_o[80]
  PIN arb_port_o[81]
    DIRECTION OUTPUT TRISTATE ;
    USE SIGNAL ;
    ANTENNADIFFAREA 2.673000 ;
    PORT
      LAYER met3 ;
        RECT 845.000 391.720 849.000 392.320 ;
    END
  END arb_port_o[81]
  PIN arb_port_o[82]
    DIRECTION OUTPUT TRISTATE ;
    USE SIGNAL ;
    ANTENNADIFFAREA 2.673000 ;
    PORT
      LAYER met3 ;
        RECT 845.000 393.080 849.000 393.680 ;
    END
  END arb_port_o[82]
  PIN arb_port_o[83]
    DIRECTION OUTPUT TRISTATE ;
    USE SIGNAL ;
    ANTENNADIFFAREA 2.673000 ;
    PORT
      LAYER met3 ;
        RECT 845.000 394.440 849.000 395.040 ;
    END
  END arb_port_o[83]
  PIN arb_port_o[84]
    DIRECTION OUTPUT TRISTATE ;
    USE SIGNAL ;
    ANTENNADIFFAREA 2.673000 ;
    PORT
      LAYER met3 ;
        RECT 845.000 395.800 849.000 396.400 ;
    END
  END arb_port_o[84]
  PIN arb_port_o[85]
    DIRECTION OUTPUT TRISTATE ;
    USE SIGNAL ;
    ANTENNADIFFAREA 2.673000 ;
    PORT
      LAYER met3 ;
        RECT 845.000 397.160 849.000 397.760 ;
    END
  END arb_port_o[85]
  PIN arb_port_o[86]
    DIRECTION OUTPUT TRISTATE ;
    USE SIGNAL ;
    ANTENNADIFFAREA 2.673000 ;
    PORT
      LAYER met3 ;
        RECT 845.000 398.520 849.000 399.120 ;
    END
  END arb_port_o[86]
  PIN arb_port_o[87]
    DIRECTION OUTPUT TRISTATE ;
    USE SIGNAL ;
    ANTENNADIFFAREA 2.673000 ;
    PORT
      LAYER met3 ;
        RECT 845.000 399.880 849.000 400.480 ;
    END
  END arb_port_o[87]
  PIN arb_port_o[88]
    DIRECTION OUTPUT TRISTATE ;
    USE SIGNAL ;
    ANTENNADIFFAREA 2.673000 ;
    PORT
      LAYER met3 ;
        RECT 845.000 401.240 849.000 401.840 ;
    END
  END arb_port_o[88]
  PIN arb_port_o[89]
    DIRECTION OUTPUT TRISTATE ;
    USE SIGNAL ;
    ANTENNADIFFAREA 2.673000 ;
    PORT
      LAYER met3 ;
        RECT 845.000 402.600 849.000 403.200 ;
    END
  END arb_port_o[89]
  PIN arb_port_o[8]
    DIRECTION OUTPUT TRISTATE ;
    USE SIGNAL ;
    ANTENNADIFFAREA 2.673000 ;
    PORT
      LAYER met3 ;
        RECT 845.000 292.440 849.000 293.040 ;
    END
  END arb_port_o[8]
  PIN arb_port_o[90]
    DIRECTION OUTPUT TRISTATE ;
    USE SIGNAL ;
    ANTENNADIFFAREA 2.673000 ;
    PORT
      LAYER met3 ;
        RECT 845.000 403.960 849.000 404.560 ;
    END
  END arb_port_o[90]
  PIN arb_port_o[91]
    DIRECTION OUTPUT TRISTATE ;
    USE SIGNAL ;
    ANTENNADIFFAREA 2.673000 ;
    PORT
      LAYER met3 ;
        RECT 845.000 405.320 849.000 405.920 ;
    END
  END arb_port_o[91]
  PIN arb_port_o[92]
    DIRECTION OUTPUT TRISTATE ;
    USE SIGNAL ;
    ANTENNADIFFAREA 2.673000 ;
    PORT
      LAYER met3 ;
        RECT 845.000 406.680 849.000 407.280 ;
    END
  END arb_port_o[92]
  PIN arb_port_o[93]
    DIRECTION OUTPUT TRISTATE ;
    USE SIGNAL ;
    ANTENNADIFFAREA 2.673000 ;
    PORT
      LAYER met3 ;
        RECT 845.000 408.040 849.000 408.640 ;
    END
  END arb_port_o[93]
  PIN arb_port_o[94]
    DIRECTION OUTPUT TRISTATE ;
    USE SIGNAL ;
    ANTENNADIFFAREA 2.673000 ;
    PORT
      LAYER met3 ;
        RECT 845.000 409.400 849.000 410.000 ;
    END
  END arb_port_o[94]
  PIN arb_port_o[95]
    DIRECTION OUTPUT TRISTATE ;
    USE SIGNAL ;
    ANTENNADIFFAREA 2.673000 ;
    PORT
      LAYER met3 ;
        RECT 845.000 410.760 849.000 411.360 ;
    END
  END arb_port_o[95]
  PIN arb_port_o[96]
    DIRECTION OUTPUT TRISTATE ;
    USE SIGNAL ;
    ANTENNADIFFAREA 2.673000 ;
    PORT
      LAYER met3 ;
        RECT 845.000 412.120 849.000 412.720 ;
    END
  END arb_port_o[96]
  PIN arb_port_o[97]
    DIRECTION OUTPUT TRISTATE ;
    USE SIGNAL ;
    ANTENNADIFFAREA 2.673000 ;
    PORT
      LAYER met3 ;
        RECT 845.000 413.480 849.000 414.080 ;
    END
  END arb_port_o[97]
  PIN arb_port_o[98]
    DIRECTION OUTPUT TRISTATE ;
    USE SIGNAL ;
    ANTENNADIFFAREA 2.673000 ;
    PORT
      LAYER met3 ;
        RECT 845.000 414.840 849.000 415.440 ;
    END
  END arb_port_o[98]
  PIN arb_port_o[99]
    DIRECTION OUTPUT TRISTATE ;
    USE SIGNAL ;
    ANTENNADIFFAREA 2.673000 ;
    PORT
      LAYER met3 ;
        RECT 845.000 416.200 849.000 416.800 ;
    END
  END arb_port_o[99]
  PIN arb_port_o[9]
    DIRECTION OUTPUT TRISTATE ;
    USE SIGNAL ;
    ANTENNADIFFAREA 2.673000 ;
    PORT
      LAYER met3 ;
        RECT 845.000 293.800 849.000 294.400 ;
    END
  END arb_port_o[9]
  PIN core_port_i[0]
    DIRECTION INPUT ;
    USE SIGNAL ;
    ANTENNAGATEAREA 0.247500 ;
    PORT
      LAYER met3 ;
        RECT 0.000 4.120 4.000 4.720 ;
    END
  END core_port_i[0]
  PIN core_port_i[100]
    DIRECTION INPUT ;
    USE SIGNAL ;
    ANTENNAGATEAREA 0.247500 ;
    PORT
      LAYER met3 ;
        RECT 0.000 140.120 4.000 140.720 ;
    END
  END core_port_i[100]
  PIN core_port_i[101]
    DIRECTION INPUT ;
    USE SIGNAL ;
    ANTENNAGATEAREA 0.426000 ;
    PORT
      LAYER met3 ;
        RECT 0.000 141.480 4.000 142.080 ;
    END
  END core_port_i[101]
  PIN core_port_i[102]
    DIRECTION INPUT ;
    USE SIGNAL ;
    ANTENNAGATEAREA 0.426000 ;
    PORT
      LAYER met3 ;
        RECT 0.000 142.840 4.000 143.440 ;
    END
  END core_port_i[102]
  PIN core_port_i[103]
    DIRECTION INPUT ;
    USE SIGNAL ;
    ANTENNAGATEAREA 0.426000 ;
    PORT
      LAYER met3 ;
        RECT 0.000 144.200 4.000 144.800 ;
    END
  END core_port_i[103]
  PIN core_port_i[104]
    DIRECTION INPUT ;
    USE SIGNAL ;
    ANTENNAGATEAREA 0.426000 ;
    PORT
      LAYER met3 ;
        RECT 0.000 145.560 4.000 146.160 ;
    END
  END core_port_i[104]
  PIN core_port_i[105]
    DIRECTION INPUT ;
    USE SIGNAL ;
    ANTENNAGATEAREA 0.426000 ;
    PORT
      LAYER met3 ;
        RECT 0.000 146.920 4.000 147.520 ;
    END
  END core_port_i[105]
  PIN core_port_i[106]
    DIRECTION INPUT ;
    USE SIGNAL ;
    ANTENNAGATEAREA 0.426000 ;
    PORT
      LAYER met3 ;
        RECT 0.000 148.280 4.000 148.880 ;
    END
  END core_port_i[106]
  PIN core_port_i[107]
    DIRECTION INPUT ;
    USE SIGNAL ;
    ANTENNAGATEAREA 0.426000 ;
    PORT
      LAYER met3 ;
        RECT 0.000 149.640 4.000 150.240 ;
    END
  END core_port_i[107]
  PIN core_port_i[108]
    DIRECTION INPUT ;
    USE SIGNAL ;
    ANTENNAGATEAREA 0.426000 ;
    PORT
      LAYER met3 ;
        RECT 0.000 151.000 4.000 151.600 ;
    END
  END core_port_i[108]
  PIN core_port_i[109]
    DIRECTION INPUT ;
    USE SIGNAL ;
    ANTENNAGATEAREA 0.426000 ;
    PORT
      LAYER met3 ;
        RECT 0.000 152.360 4.000 152.960 ;
    END
  END core_port_i[109]
  PIN core_port_i[10]
    DIRECTION INPUT ;
    USE SIGNAL ;
    ANTENNAGATEAREA 0.247500 ;
    PORT
      LAYER met3 ;
        RECT 0.000 17.720 4.000 18.320 ;
    END
  END core_port_i[10]
  PIN core_port_i[110]
    DIRECTION INPUT ;
    USE SIGNAL ;
    ANTENNAGATEAREA 0.247500 ;
    PORT
      LAYER met3 ;
        RECT 0.000 153.720 4.000 154.320 ;
    END
  END core_port_i[110]
  PIN core_port_i[111]
    DIRECTION INPUT ;
    USE SIGNAL ;
    ANTENNAGATEAREA 0.426000 ;
    PORT
      LAYER met3 ;
        RECT 0.000 155.080 4.000 155.680 ;
    END
  END core_port_i[111]
  PIN core_port_i[112]
    DIRECTION INPUT ;
    USE SIGNAL ;
    ANTENNAGATEAREA 0.426000 ;
    PORT
      LAYER met3 ;
        RECT 0.000 156.440 4.000 157.040 ;
    END
  END core_port_i[112]
  PIN core_port_i[113]
    DIRECTION INPUT ;
    USE SIGNAL ;
    ANTENNAGATEAREA 0.426000 ;
    PORT
      LAYER met3 ;
        RECT 0.000 157.800 4.000 158.400 ;
    END
  END core_port_i[113]
  PIN core_port_i[114]
    DIRECTION INPUT ;
    USE SIGNAL ;
    ANTENNAGATEAREA 0.426000 ;
    PORT
      LAYER met3 ;
        RECT 0.000 159.160 4.000 159.760 ;
    END
  END core_port_i[114]
  PIN core_port_i[115]
    DIRECTION INPUT ;
    USE SIGNAL ;
    ANTENNAGATEAREA 0.247500 ;
    PORT
      LAYER met3 ;
        RECT 0.000 160.520 4.000 161.120 ;
    END
  END core_port_i[115]
  PIN core_port_i[116]
    DIRECTION INPUT ;
    USE SIGNAL ;
    ANTENNAGATEAREA 0.426000 ;
    PORT
      LAYER met3 ;
        RECT 0.000 161.880 4.000 162.480 ;
    END
  END core_port_i[116]
  PIN core_port_i[117]
    DIRECTION INPUT ;
    USE SIGNAL ;
    ANTENNAGATEAREA 0.247500 ;
    PORT
      LAYER met3 ;
        RECT 0.000 163.240 4.000 163.840 ;
    END
  END core_port_i[117]
  PIN core_port_i[118]
    DIRECTION INPUT ;
    USE SIGNAL ;
    ANTENNAGATEAREA 0.247500 ;
    PORT
      LAYER met3 ;
        RECT 0.000 164.600 4.000 165.200 ;
    END
  END core_port_i[118]
  PIN core_port_i[119]
    DIRECTION INPUT ;
    USE SIGNAL ;
    ANTENNAGATEAREA 0.247500 ;
    PORT
      LAYER met3 ;
        RECT 0.000 165.960 4.000 166.560 ;
    END
  END core_port_i[119]
  PIN core_port_i[11]
    DIRECTION INPUT ;
    USE SIGNAL ;
    ANTENNAGATEAREA 0.247500 ;
    PORT
      LAYER met3 ;
        RECT 0.000 19.080 4.000 19.680 ;
    END
  END core_port_i[11]
  PIN core_port_i[120]
    DIRECTION INPUT ;
    USE SIGNAL ;
    ANTENNAGATEAREA 0.247500 ;
    PORT
      LAYER met3 ;
        RECT 0.000 167.320 4.000 167.920 ;
    END
  END core_port_i[120]
  PIN core_port_i[121]
    DIRECTION INPUT ;
    USE SIGNAL ;
    ANTENNAGATEAREA 0.247500 ;
    PORT
      LAYER met3 ;
        RECT 0.000 168.680 4.000 169.280 ;
    END
  END core_port_i[121]
  PIN core_port_i[122]
    DIRECTION INPUT ;
    USE SIGNAL ;
    ANTENNAGATEAREA 0.426000 ;
    PORT
      LAYER met3 ;
        RECT 0.000 170.040 4.000 170.640 ;
    END
  END core_port_i[122]
  PIN core_port_i[123]
    DIRECTION INPUT ;
    USE SIGNAL ;
    ANTENNAGATEAREA 0.247500 ;
    PORT
      LAYER met3 ;
        RECT 0.000 171.400 4.000 172.000 ;
    END
  END core_port_i[123]
  PIN core_port_i[124]
    DIRECTION INPUT ;
    USE SIGNAL ;
    ANTENNAGATEAREA 0.247500 ;
    PORT
      LAYER met3 ;
        RECT 0.000 172.760 4.000 173.360 ;
    END
  END core_port_i[124]
  PIN core_port_i[125]
    DIRECTION INPUT ;
    USE SIGNAL ;
    ANTENNAGATEAREA 0.247500 ;
    PORT
      LAYER met3 ;
        RECT 0.000 174.120 4.000 174.720 ;
    END
  END core_port_i[125]
  PIN core_port_i[126]
    DIRECTION INPUT ;
    USE SIGNAL ;
    ANTENNAGATEAREA 0.426000 ;
    PORT
      LAYER met3 ;
        RECT 0.000 175.480 4.000 176.080 ;
    END
  END core_port_i[126]
  PIN core_port_i[127]
    DIRECTION INPUT ;
    USE SIGNAL ;
    ANTENNAGATEAREA 0.426000 ;
    PORT
      LAYER met3 ;
        RECT 0.000 176.840 4.000 177.440 ;
    END
  END core_port_i[127]
  PIN core_port_i[128]
    DIRECTION INPUT ;
    USE SIGNAL ;
    ANTENNAGATEAREA 0.247500 ;
    PORT
      LAYER met3 ;
        RECT 0.000 178.200 4.000 178.800 ;
    END
  END core_port_i[128]
  PIN core_port_i[129]
    DIRECTION INPUT ;
    USE SIGNAL ;
    ANTENNAGATEAREA 0.426000 ;
    PORT
      LAYER met3 ;
        RECT 0.000 179.560 4.000 180.160 ;
    END
  END core_port_i[129]
  PIN core_port_i[12]
    DIRECTION INPUT ;
    USE SIGNAL ;
    ANTENNAGATEAREA 0.247500 ;
    PORT
      LAYER met3 ;
        RECT 0.000 20.440 4.000 21.040 ;
    END
  END core_port_i[12]
  PIN core_port_i[130]
    DIRECTION INPUT ;
    USE SIGNAL ;
    ANTENNAGATEAREA 0.426000 ;
    PORT
      LAYER met3 ;
        RECT 0.000 180.920 4.000 181.520 ;
    END
  END core_port_i[130]
  PIN core_port_i[131]
    DIRECTION INPUT ;
    USE SIGNAL ;
    ANTENNAGATEAREA 0.426000 ;
    PORT
      LAYER met3 ;
        RECT 0.000 182.280 4.000 182.880 ;
    END
  END core_port_i[131]
  PIN core_port_i[132]
    DIRECTION INPUT ;
    USE SIGNAL ;
    ANTENNAGATEAREA 0.426000 ;
    PORT
      LAYER met3 ;
        RECT 0.000 183.640 4.000 184.240 ;
    END
  END core_port_i[132]
  PIN core_port_i[133]
    DIRECTION INPUT ;
    USE SIGNAL ;
    ANTENNAGATEAREA 0.495000 ;
    PORT
      LAYER met3 ;
        RECT 0.000 185.000 4.000 185.600 ;
    END
  END core_port_i[133]
  PIN core_port_i[134]
    DIRECTION INPUT ;
    USE SIGNAL ;
    ANTENNAGATEAREA 0.247500 ;
    PORT
      LAYER met3 ;
        RECT 0.000 186.360 4.000 186.960 ;
    END
  END core_port_i[134]
  PIN core_port_i[135]
    DIRECTION INPUT ;
    USE SIGNAL ;
    ANTENNAGATEAREA 0.247500 ;
    PORT
      LAYER met3 ;
        RECT 0.000 187.720 4.000 188.320 ;
    END
  END core_port_i[135]
  PIN core_port_i[136]
    DIRECTION INPUT ;
    USE SIGNAL ;
    ANTENNAGATEAREA 0.247500 ;
    PORT
      LAYER met3 ;
        RECT 0.000 189.080 4.000 189.680 ;
    END
  END core_port_i[136]
  PIN core_port_i[137]
    DIRECTION INPUT ;
    USE SIGNAL ;
    ANTENNAGATEAREA 0.247500 ;
    PORT
      LAYER met3 ;
        RECT 0.000 190.440 4.000 191.040 ;
    END
  END core_port_i[137]
  PIN core_port_i[138]
    DIRECTION INPUT ;
    USE SIGNAL ;
    ANTENNAGATEAREA 0.247500 ;
    PORT
      LAYER met3 ;
        RECT 0.000 191.800 4.000 192.400 ;
    END
  END core_port_i[138]
  PIN core_port_i[139]
    DIRECTION INPUT ;
    USE SIGNAL ;
    ANTENNAGATEAREA 0.247500 ;
    PORT
      LAYER met3 ;
        RECT 0.000 193.160 4.000 193.760 ;
    END
  END core_port_i[139]
  PIN core_port_i[13]
    DIRECTION INPUT ;
    USE SIGNAL ;
    ANTENNAGATEAREA 0.247500 ;
    PORT
      LAYER met3 ;
        RECT 0.000 21.800 4.000 22.400 ;
    END
  END core_port_i[13]
  PIN core_port_i[140]
    DIRECTION INPUT ;
    USE SIGNAL ;
    ANTENNAGATEAREA 0.247500 ;
    PORT
      LAYER met3 ;
        RECT 0.000 194.520 4.000 195.120 ;
    END
  END core_port_i[140]
  PIN core_port_i[141]
    DIRECTION INPUT ;
    USE SIGNAL ;
    ANTENNAGATEAREA 0.247500 ;
    PORT
      LAYER met3 ;
        RECT 0.000 195.880 4.000 196.480 ;
    END
  END core_port_i[141]
  PIN core_port_i[142]
    DIRECTION INPUT ;
    USE SIGNAL ;
    ANTENNAGATEAREA 0.247500 ;
    PORT
      LAYER met3 ;
        RECT 0.000 197.240 4.000 197.840 ;
    END
  END core_port_i[142]
  PIN core_port_i[143]
    DIRECTION INPUT ;
    USE SIGNAL ;
    ANTENNAGATEAREA 0.247500 ;
    PORT
      LAYER met3 ;
        RECT 0.000 198.600 4.000 199.200 ;
    END
  END core_port_i[143]
  PIN core_port_i[144]
    DIRECTION INPUT ;
    USE SIGNAL ;
    ANTENNAGATEAREA 0.247500 ;
    PORT
      LAYER met3 ;
        RECT 0.000 199.960 4.000 200.560 ;
    END
  END core_port_i[144]
  PIN core_port_i[145]
    DIRECTION INPUT ;
    USE SIGNAL ;
    ANTENNAGATEAREA 0.247500 ;
    PORT
      LAYER met3 ;
        RECT 0.000 201.320 4.000 201.920 ;
    END
  END core_port_i[145]
  PIN core_port_i[146]
    DIRECTION INPUT ;
    USE SIGNAL ;
    ANTENNAGATEAREA 0.247500 ;
    PORT
      LAYER met3 ;
        RECT 0.000 202.680 4.000 203.280 ;
    END
  END core_port_i[146]
  PIN core_port_i[147]
    DIRECTION INPUT ;
    USE SIGNAL ;
    ANTENNAGATEAREA 0.247500 ;
    PORT
      LAYER met3 ;
        RECT 0.000 204.040 4.000 204.640 ;
    END
  END core_port_i[147]
  PIN core_port_i[148]
    DIRECTION INPUT ;
    USE SIGNAL ;
    ANTENNAGATEAREA 0.247500 ;
    PORT
      LAYER met3 ;
        RECT 0.000 205.400 4.000 206.000 ;
    END
  END core_port_i[148]
  PIN core_port_i[149]
    DIRECTION INPUT ;
    USE SIGNAL ;
    ANTENNAGATEAREA 0.247500 ;
    PORT
      LAYER met3 ;
        RECT 0.000 206.760 4.000 207.360 ;
    END
  END core_port_i[149]
  PIN core_port_i[14]
    DIRECTION INPUT ;
    USE SIGNAL ;
    ANTENNAGATEAREA 0.247500 ;
    PORT
      LAYER met3 ;
        RECT 0.000 23.160 4.000 23.760 ;
    END
  END core_port_i[14]
  PIN core_port_i[150]
    DIRECTION INPUT ;
    USE SIGNAL ;
    ANTENNAGATEAREA 0.247500 ;
    PORT
      LAYER met3 ;
        RECT 0.000 208.120 4.000 208.720 ;
    END
  END core_port_i[150]
  PIN core_port_i[151]
    DIRECTION INPUT ;
    USE SIGNAL ;
    ANTENNAGATEAREA 0.247500 ;
    PORT
      LAYER met3 ;
        RECT 0.000 209.480 4.000 210.080 ;
    END
  END core_port_i[151]
  PIN core_port_i[152]
    DIRECTION INPUT ;
    USE SIGNAL ;
    ANTENNAGATEAREA 0.426000 ;
    PORT
      LAYER met3 ;
        RECT 0.000 210.840 4.000 211.440 ;
    END
  END core_port_i[152]
  PIN core_port_i[153]
    DIRECTION INPUT ;
    USE SIGNAL ;
    ANTENNAGATEAREA 0.426000 ;
    PORT
      LAYER met3 ;
        RECT 0.000 212.200 4.000 212.800 ;
    END
  END core_port_i[153]
  PIN core_port_i[154]
    DIRECTION INPUT ;
    USE SIGNAL ;
    ANTENNAGATEAREA 0.426000 ;
    PORT
      LAYER met3 ;
        RECT 0.000 213.560 4.000 214.160 ;
    END
  END core_port_i[154]
  PIN core_port_i[155]
    DIRECTION INPUT ;
    USE SIGNAL ;
    ANTENNAGATEAREA 0.426000 ;
    PORT
      LAYER met3 ;
        RECT 0.000 214.920 4.000 215.520 ;
    END
  END core_port_i[155]
  PIN core_port_i[156]
    DIRECTION INPUT ;
    USE SIGNAL ;
    ANTENNAGATEAREA 0.426000 ;
    PORT
      LAYER met3 ;
        RECT 0.000 216.280 4.000 216.880 ;
    END
  END core_port_i[156]
  PIN core_port_i[157]
    DIRECTION INPUT ;
    USE SIGNAL ;
    ANTENNAGATEAREA 0.426000 ;
    PORT
      LAYER met3 ;
        RECT 0.000 217.640 4.000 218.240 ;
    END
  END core_port_i[157]
  PIN core_port_i[158]
    DIRECTION INPUT ;
    USE SIGNAL ;
    ANTENNAGATEAREA 0.426000 ;
    PORT
      LAYER met3 ;
        RECT 0.000 219.000 4.000 219.600 ;
    END
  END core_port_i[158]
  PIN core_port_i[159]
    DIRECTION INPUT ;
    USE SIGNAL ;
    ANTENNAGATEAREA 0.426000 ;
    PORT
      LAYER met3 ;
        RECT 0.000 220.360 4.000 220.960 ;
    END
  END core_port_i[159]
  PIN core_port_i[15]
    DIRECTION INPUT ;
    USE SIGNAL ;
    ANTENNAGATEAREA 0.247500 ;
    PORT
      LAYER met3 ;
        RECT 0.000 24.520 4.000 25.120 ;
    END
  END core_port_i[15]
  PIN core_port_i[160]
    DIRECTION INPUT ;
    USE SIGNAL ;
    ANTENNAGATEAREA 0.426000 ;
    PORT
      LAYER met3 ;
        RECT 0.000 221.720 4.000 222.320 ;
    END
  END core_port_i[160]
  PIN core_port_i[161]
    DIRECTION INPUT ;
    USE SIGNAL ;
    ANTENNAGATEAREA 0.426000 ;
    PORT
      LAYER met3 ;
        RECT 0.000 223.080 4.000 223.680 ;
    END
  END core_port_i[161]
  PIN core_port_i[162]
    DIRECTION INPUT ;
    USE SIGNAL ;
    ANTENNAGATEAREA 0.426000 ;
    PORT
      LAYER met3 ;
        RECT 0.000 224.440 4.000 225.040 ;
    END
  END core_port_i[162]
  PIN core_port_i[163]
    DIRECTION INPUT ;
    USE SIGNAL ;
    ANTENNAGATEAREA 0.426000 ;
    PORT
      LAYER met3 ;
        RECT 0.000 225.800 4.000 226.400 ;
    END
  END core_port_i[163]
  PIN core_port_i[164]
    DIRECTION INPUT ;
    USE SIGNAL ;
    ANTENNAGATEAREA 0.426000 ;
    PORT
      LAYER met3 ;
        RECT 0.000 227.160 4.000 227.760 ;
    END
  END core_port_i[164]
  PIN core_port_i[165]
    DIRECTION INPUT ;
    USE SIGNAL ;
    ANTENNAGATEAREA 0.426000 ;
    PORT
      LAYER met3 ;
        RECT 0.000 228.520 4.000 229.120 ;
    END
  END core_port_i[165]
  PIN core_port_i[166]
    DIRECTION INPUT ;
    USE SIGNAL ;
    ANTENNAGATEAREA 0.426000 ;
    PORT
      LAYER met3 ;
        RECT 0.000 229.880 4.000 230.480 ;
    END
  END core_port_i[166]
  PIN core_port_i[167]
    DIRECTION INPUT ;
    USE SIGNAL ;
    ANTENNAGATEAREA 0.426000 ;
    PORT
      LAYER met3 ;
        RECT 0.000 231.240 4.000 231.840 ;
    END
  END core_port_i[167]
  PIN core_port_i[168]
    DIRECTION INPUT ;
    USE SIGNAL ;
    ANTENNAGATEAREA 0.426000 ;
    PORT
      LAYER met3 ;
        RECT 0.000 232.600 4.000 233.200 ;
    END
  END core_port_i[168]
  PIN core_port_i[169]
    DIRECTION INPUT ;
    USE SIGNAL ;
    ANTENNAGATEAREA 0.426000 ;
    PORT
      LAYER met3 ;
        RECT 0.000 233.960 4.000 234.560 ;
    END
  END core_port_i[169]
  PIN core_port_i[16]
    DIRECTION INPUT ;
    USE SIGNAL ;
    ANTENNAGATEAREA 0.247500 ;
    PORT
      LAYER met3 ;
        RECT 0.000 25.880 4.000 26.480 ;
    END
  END core_port_i[16]
  PIN core_port_i[170]
    DIRECTION INPUT ;
    USE SIGNAL ;
    ANTENNAGATEAREA 0.426000 ;
    PORT
      LAYER met3 ;
        RECT 0.000 235.320 4.000 235.920 ;
    END
  END core_port_i[170]
  PIN core_port_i[171]
    DIRECTION INPUT ;
    USE SIGNAL ;
    ANTENNAGATEAREA 0.426000 ;
    PORT
      LAYER met3 ;
        RECT 0.000 236.680 4.000 237.280 ;
    END
  END core_port_i[171]
  PIN core_port_i[172]
    DIRECTION INPUT ;
    USE SIGNAL ;
    ANTENNAGATEAREA 0.426000 ;
    PORT
      LAYER met3 ;
        RECT 0.000 238.040 4.000 238.640 ;
    END
  END core_port_i[172]
  PIN core_port_i[173]
    DIRECTION INPUT ;
    USE SIGNAL ;
    ANTENNAGATEAREA 0.426000 ;
    PORT
      LAYER met3 ;
        RECT 0.000 239.400 4.000 240.000 ;
    END
  END core_port_i[173]
  PIN core_port_i[174]
    DIRECTION INPUT ;
    USE SIGNAL ;
    ANTENNAGATEAREA 0.426000 ;
    PORT
      LAYER met3 ;
        RECT 0.000 240.760 4.000 241.360 ;
    END
  END core_port_i[174]
  PIN core_port_i[175]
    DIRECTION INPUT ;
    USE SIGNAL ;
    ANTENNAGATEAREA 0.426000 ;
    PORT
      LAYER met3 ;
        RECT 0.000 242.120 4.000 242.720 ;
    END
  END core_port_i[175]
  PIN core_port_i[176]
    DIRECTION INPUT ;
    USE SIGNAL ;
    ANTENNAGATEAREA 0.247500 ;
    PORT
      LAYER met3 ;
        RECT 0.000 243.480 4.000 244.080 ;
    END
  END core_port_i[176]
  PIN core_port_i[177]
    DIRECTION INPUT ;
    USE SIGNAL ;
    ANTENNAGATEAREA 0.426000 ;
    PORT
      LAYER met3 ;
        RECT 0.000 244.840 4.000 245.440 ;
    END
  END core_port_i[177]
  PIN core_port_i[178]
    DIRECTION INPUT ;
    USE SIGNAL ;
    ANTENNAGATEAREA 0.426000 ;
    PORT
      LAYER met3 ;
        RECT 0.000 246.200 4.000 246.800 ;
    END
  END core_port_i[178]
  PIN core_port_i[179]
    DIRECTION INPUT ;
    USE SIGNAL ;
    ANTENNAGATEAREA 0.247500 ;
    PORT
      LAYER met3 ;
        RECT 0.000 247.560 4.000 248.160 ;
    END
  END core_port_i[179]
  PIN core_port_i[17]
    DIRECTION INPUT ;
    USE SIGNAL ;
    ANTENNAGATEAREA 0.247500 ;
    PORT
      LAYER met3 ;
        RECT 0.000 27.240 4.000 27.840 ;
    END
  END core_port_i[17]
  PIN core_port_i[180]
    DIRECTION INPUT ;
    USE SIGNAL ;
    ANTENNAGATEAREA 0.426000 ;
    PORT
      LAYER met3 ;
        RECT 0.000 248.920 4.000 249.520 ;
    END
  END core_port_i[180]
  PIN core_port_i[181]
    DIRECTION INPUT ;
    USE SIGNAL ;
    ANTENNAGATEAREA 0.426000 ;
    PORT
      LAYER met3 ;
        RECT 0.000 250.280 4.000 250.880 ;
    END
  END core_port_i[181]
  PIN core_port_i[182]
    DIRECTION INPUT ;
    USE SIGNAL ;
    ANTENNAGATEAREA 0.426000 ;
    PORT
      LAYER met3 ;
        RECT 0.000 251.640 4.000 252.240 ;
    END
  END core_port_i[182]
  PIN core_port_i[183]
    DIRECTION INPUT ;
    USE SIGNAL ;
    ANTENNAGATEAREA 0.426000 ;
    PORT
      LAYER met3 ;
        RECT 0.000 253.000 4.000 253.600 ;
    END
  END core_port_i[183]
  PIN core_port_i[184]
    DIRECTION INPUT ;
    USE SIGNAL ;
    ANTENNAGATEAREA 0.247500 ;
    PORT
      LAYER met3 ;
        RECT 0.000 254.360 4.000 254.960 ;
    END
  END core_port_i[184]
  PIN core_port_i[185]
    DIRECTION INPUT ;
    USE SIGNAL ;
    ANTENNAGATEAREA 0.426000 ;
    PORT
      LAYER met3 ;
        RECT 0.000 255.720 4.000 256.320 ;
    END
  END core_port_i[185]
  PIN core_port_i[186]
    DIRECTION INPUT ;
    USE SIGNAL ;
    ANTENNAGATEAREA 0.247500 ;
    PORT
      LAYER met3 ;
        RECT 0.000 257.080 4.000 257.680 ;
    END
  END core_port_i[186]
  PIN core_port_i[187]
    DIRECTION INPUT ;
    USE SIGNAL ;
    ANTENNAGATEAREA 0.247500 ;
    PORT
      LAYER met3 ;
        RECT 0.000 258.440 4.000 259.040 ;
    END
  END core_port_i[187]
  PIN core_port_i[188]
    DIRECTION INPUT ;
    USE SIGNAL ;
    ANTENNAGATEAREA 0.247500 ;
    PORT
      LAYER met3 ;
        RECT 0.000 259.800 4.000 260.400 ;
    END
  END core_port_i[188]
  PIN core_port_i[189]
    DIRECTION INPUT ;
    USE SIGNAL ;
    ANTENNAGATEAREA 0.247500 ;
    PORT
      LAYER met3 ;
        RECT 0.000 261.160 4.000 261.760 ;
    END
  END core_port_i[189]
  PIN core_port_i[18]
    DIRECTION INPUT ;
    USE SIGNAL ;
    ANTENNAGATEAREA 0.247500 ;
    PORT
      LAYER met3 ;
        RECT 0.000 28.600 4.000 29.200 ;
    END
  END core_port_i[18]
  PIN core_port_i[190]
    DIRECTION INPUT ;
    USE SIGNAL ;
    ANTENNAGATEAREA 0.247500 ;
    PORT
      LAYER met3 ;
        RECT 0.000 262.520 4.000 263.120 ;
    END
  END core_port_i[190]
  PIN core_port_i[191]
    DIRECTION INPUT ;
    USE SIGNAL ;
    ANTENNAGATEAREA 0.247500 ;
    PORT
      LAYER met3 ;
        RECT 0.000 263.880 4.000 264.480 ;
    END
  END core_port_i[191]
  PIN core_port_i[192]
    DIRECTION INPUT ;
    USE SIGNAL ;
    ANTENNAGATEAREA 0.426000 ;
    PORT
      LAYER met3 ;
        RECT 0.000 265.240 4.000 265.840 ;
    END
  END core_port_i[192]
  PIN core_port_i[193]
    DIRECTION INPUT ;
    USE SIGNAL ;
    ANTENNAGATEAREA 0.426000 ;
    PORT
      LAYER met3 ;
        RECT 0.000 266.600 4.000 267.200 ;
    END
  END core_port_i[193]
  PIN core_port_i[194]
    DIRECTION INPUT ;
    USE SIGNAL ;
    ANTENNAGATEAREA 0.426000 ;
    PORT
      LAYER met3 ;
        RECT 0.000 267.960 4.000 268.560 ;
    END
  END core_port_i[194]
  PIN core_port_i[195]
    DIRECTION INPUT ;
    USE SIGNAL ;
    ANTENNAGATEAREA 0.426000 ;
    PORT
      LAYER met3 ;
        RECT 0.000 269.320 4.000 269.920 ;
    END
  END core_port_i[195]
  PIN core_port_i[196]
    DIRECTION INPUT ;
    USE SIGNAL ;
    ANTENNAGATEAREA 0.426000 ;
    PORT
      LAYER met3 ;
        RECT 0.000 270.680 4.000 271.280 ;
    END
  END core_port_i[196]
  PIN core_port_i[197]
    DIRECTION INPUT ;
    USE SIGNAL ;
    ANTENNAGATEAREA 0.426000 ;
    PORT
      LAYER met3 ;
        RECT 0.000 272.040 4.000 272.640 ;
    END
  END core_port_i[197]
  PIN core_port_i[198]
    DIRECTION INPUT ;
    USE SIGNAL ;
    ANTENNAGATEAREA 0.426000 ;
    PORT
      LAYER met3 ;
        RECT 0.000 273.400 4.000 274.000 ;
    END
  END core_port_i[198]
  PIN core_port_i[199]
    DIRECTION INPUT ;
    USE SIGNAL ;
    ANTENNAGATEAREA 0.426000 ;
    PORT
      LAYER met3 ;
        RECT 0.000 274.760 4.000 275.360 ;
    END
  END core_port_i[199]
  PIN core_port_i[19]
    DIRECTION INPUT ;
    USE SIGNAL ;
    ANTENNAGATEAREA 0.247500 ;
    PORT
      LAYER met3 ;
        RECT 0.000 29.960 4.000 30.560 ;
    END
  END core_port_i[19]
  PIN core_port_i[1]
    DIRECTION INPUT ;
    USE SIGNAL ;
    ANTENNAGATEAREA 0.247500 ;
    PORT
      LAYER met3 ;
        RECT 0.000 5.480 4.000 6.080 ;
    END
  END core_port_i[1]
  PIN core_port_i[200]
    DIRECTION INPUT ;
    USE SIGNAL ;
    ANTENNAGATEAREA 0.426000 ;
    PORT
      LAYER met3 ;
        RECT 0.000 276.120 4.000 276.720 ;
    END
  END core_port_i[200]
  PIN core_port_i[201]
    DIRECTION INPUT ;
    USE SIGNAL ;
    ANTENNAGATEAREA 0.426000 ;
    PORT
      LAYER met3 ;
        RECT 0.000 277.480 4.000 278.080 ;
    END
  END core_port_i[201]
  PIN core_port_i[202]
    DIRECTION INPUT ;
    USE SIGNAL ;
    ANTENNAGATEAREA 0.426000 ;
    PORT
      LAYER met3 ;
        RECT 0.000 278.840 4.000 279.440 ;
    END
  END core_port_i[202]
  PIN core_port_i[203]
    DIRECTION INPUT ;
    USE SIGNAL ;
    ANTENNAGATEAREA 0.426000 ;
    PORT
      LAYER met3 ;
        RECT 0.000 280.200 4.000 280.800 ;
    END
  END core_port_i[203]
  PIN core_port_i[204]
    DIRECTION INPUT ;
    USE SIGNAL ;
    ANTENNAGATEAREA 0.426000 ;
    PORT
      LAYER met3 ;
        RECT 0.000 281.560 4.000 282.160 ;
    END
  END core_port_i[204]
  PIN core_port_i[205]
    DIRECTION INPUT ;
    USE SIGNAL ;
    ANTENNAGATEAREA 0.426000 ;
    PORT
      LAYER met3 ;
        RECT 0.000 282.920 4.000 283.520 ;
    END
  END core_port_i[205]
  PIN core_port_i[206]
    DIRECTION INPUT ;
    USE SIGNAL ;
    ANTENNAGATEAREA 0.426000 ;
    PORT
      LAYER met3 ;
        RECT 0.000 284.280 4.000 284.880 ;
    END
  END core_port_i[206]
  PIN core_port_i[207]
    DIRECTION INPUT ;
    USE SIGNAL ;
    ANTENNAGATEAREA 0.213000 ;
    PORT
      LAYER met3 ;
        RECT 0.000 285.640 4.000 286.240 ;
    END
  END core_port_i[207]
  PIN core_port_i[208]
    DIRECTION INPUT ;
    USE SIGNAL ;
    ANTENNAGATEAREA 0.213000 ;
    PORT
      LAYER met3 ;
        RECT 0.000 287.000 4.000 287.600 ;
    END
  END core_port_i[208]
  PIN core_port_i[209]
    DIRECTION INPUT ;
    USE SIGNAL ;
    ANTENNAGATEAREA 0.213000 ;
    PORT
      LAYER met3 ;
        RECT 0.000 288.360 4.000 288.960 ;
    END
  END core_port_i[209]
  PIN core_port_i[20]
    DIRECTION INPUT ;
    USE SIGNAL ;
    ANTENNAGATEAREA 0.247500 ;
    PORT
      LAYER met3 ;
        RECT 0.000 31.320 4.000 31.920 ;
    END
  END core_port_i[20]
  PIN core_port_i[210]
    DIRECTION INPUT ;
    USE SIGNAL ;
    ANTENNAGATEAREA 0.213000 ;
    PORT
      LAYER met3 ;
        RECT 0.000 289.720 4.000 290.320 ;
    END
  END core_port_i[210]
  PIN core_port_i[211]
    DIRECTION INPUT ;
    USE SIGNAL ;
    ANTENNAGATEAREA 0.213000 ;
    PORT
      LAYER met3 ;
        RECT 0.000 291.080 4.000 291.680 ;
    END
  END core_port_i[211]
  PIN core_port_i[212]
    DIRECTION INPUT ;
    USE SIGNAL ;
    ANTENNAGATEAREA 0.213000 ;
    PORT
      LAYER met3 ;
        RECT 0.000 292.440 4.000 293.040 ;
    END
  END core_port_i[212]
  PIN core_port_i[213]
    DIRECTION INPUT ;
    USE SIGNAL ;
    ANTENNAGATEAREA 0.213000 ;
    PORT
      LAYER met3 ;
        RECT 0.000 293.800 4.000 294.400 ;
    END
  END core_port_i[213]
  PIN core_port_i[214]
    DIRECTION INPUT ;
    USE SIGNAL ;
    ANTENNAGATEAREA 0.213000 ;
    PORT
      LAYER met3 ;
        RECT 0.000 295.160 4.000 295.760 ;
    END
  END core_port_i[214]
  PIN core_port_i[215]
    DIRECTION INPUT ;
    USE SIGNAL ;
    ANTENNAGATEAREA 0.213000 ;
    PORT
      LAYER met3 ;
        RECT 0.000 296.520 4.000 297.120 ;
    END
  END core_port_i[215]
  PIN core_port_i[216]
    DIRECTION INPUT ;
    USE SIGNAL ;
    ANTENNAGATEAREA 0.213000 ;
    PORT
      LAYER met3 ;
        RECT 0.000 297.880 4.000 298.480 ;
    END
  END core_port_i[216]
  PIN core_port_i[217]
    DIRECTION INPUT ;
    USE SIGNAL ;
    ANTENNAGATEAREA 0.213000 ;
    PORT
      LAYER met3 ;
        RECT 0.000 299.240 4.000 299.840 ;
    END
  END core_port_i[217]
  PIN core_port_i[218]
    DIRECTION INPUT ;
    USE SIGNAL ;
    ANTENNAGATEAREA 0.213000 ;
    PORT
      LAYER met3 ;
        RECT 0.000 300.600 4.000 301.200 ;
    END
  END core_port_i[218]
  PIN core_port_i[219]
    DIRECTION INPUT ;
    USE SIGNAL ;
    ANTENNAGATEAREA 0.213000 ;
    PORT
      LAYER met3 ;
        RECT 0.000 301.960 4.000 302.560 ;
    END
  END core_port_i[219]
  PIN core_port_i[21]
    DIRECTION INPUT ;
    USE SIGNAL ;
    ANTENNAGATEAREA 0.247500 ;
    PORT
      LAYER met3 ;
        RECT 0.000 32.680 4.000 33.280 ;
    END
  END core_port_i[21]
  PIN core_port_i[220]
    DIRECTION INPUT ;
    USE SIGNAL ;
    ANTENNAGATEAREA 0.213000 ;
    PORT
      LAYER met3 ;
        RECT 0.000 303.320 4.000 303.920 ;
    END
  END core_port_i[220]
  PIN core_port_i[221]
    DIRECTION INPUT ;
    USE SIGNAL ;
    ANTENNAGATEAREA 0.213000 ;
    PORT
      LAYER met3 ;
        RECT 0.000 304.680 4.000 305.280 ;
    END
  END core_port_i[221]
  PIN core_port_i[222]
    DIRECTION INPUT ;
    USE SIGNAL ;
    ANTENNAGATEAREA 0.213000 ;
    PORT
      LAYER met3 ;
        RECT 0.000 306.040 4.000 306.640 ;
    END
  END core_port_i[222]
  PIN core_port_i[223]
    DIRECTION INPUT ;
    USE SIGNAL ;
    ANTENNAGATEAREA 0.213000 ;
    PORT
      LAYER met3 ;
        RECT 0.000 307.400 4.000 308.000 ;
    END
  END core_port_i[223]
  PIN core_port_i[224]
    DIRECTION INPUT ;
    USE SIGNAL ;
    ANTENNAGATEAREA 0.213000 ;
    PORT
      LAYER met3 ;
        RECT 0.000 308.760 4.000 309.360 ;
    END
  END core_port_i[224]
  PIN core_port_i[225]
    DIRECTION INPUT ;
    USE SIGNAL ;
    ANTENNAGATEAREA 0.213000 ;
    PORT
      LAYER met3 ;
        RECT 0.000 310.120 4.000 310.720 ;
    END
  END core_port_i[225]
  PIN core_port_i[226]
    DIRECTION INPUT ;
    USE SIGNAL ;
    ANTENNAGATEAREA 0.213000 ;
    PORT
      LAYER met3 ;
        RECT 0.000 311.480 4.000 312.080 ;
    END
  END core_port_i[226]
  PIN core_port_i[227]
    DIRECTION INPUT ;
    USE SIGNAL ;
    ANTENNAGATEAREA 0.213000 ;
    PORT
      LAYER met3 ;
        RECT 0.000 312.840 4.000 313.440 ;
    END
  END core_port_i[227]
  PIN core_port_i[228]
    DIRECTION INPUT ;
    USE SIGNAL ;
    ANTENNAGATEAREA 0.213000 ;
    PORT
      LAYER met3 ;
        RECT 0.000 314.200 4.000 314.800 ;
    END
  END core_port_i[228]
  PIN core_port_i[229]
    DIRECTION INPUT ;
    USE SIGNAL ;
    ANTENNAGATEAREA 0.213000 ;
    PORT
      LAYER met3 ;
        RECT 0.000 315.560 4.000 316.160 ;
    END
  END core_port_i[229]
  PIN core_port_i[22]
    DIRECTION INPUT ;
    USE SIGNAL ;
    ANTENNAGATEAREA 0.247500 ;
    PORT
      LAYER met3 ;
        RECT 0.000 34.040 4.000 34.640 ;
    END
  END core_port_i[22]
  PIN core_port_i[230]
    DIRECTION INPUT ;
    USE SIGNAL ;
    ANTENNAGATEAREA 0.213000 ;
    PORT
      LAYER met3 ;
        RECT 0.000 316.920 4.000 317.520 ;
    END
  END core_port_i[230]
  PIN core_port_i[231]
    DIRECTION INPUT ;
    USE SIGNAL ;
    ANTENNAGATEAREA 0.213000 ;
    PORT
      LAYER met3 ;
        RECT 0.000 318.280 4.000 318.880 ;
    END
  END core_port_i[231]
  PIN core_port_i[232]
    DIRECTION INPUT ;
    USE SIGNAL ;
    ANTENNAGATEAREA 0.213000 ;
    PORT
      LAYER met3 ;
        RECT 0.000 319.640 4.000 320.240 ;
    END
  END core_port_i[232]
  PIN core_port_i[233]
    DIRECTION INPUT ;
    USE SIGNAL ;
    ANTENNAGATEAREA 0.213000 ;
    PORT
      LAYER met3 ;
        RECT 0.000 321.000 4.000 321.600 ;
    END
  END core_port_i[233]
  PIN core_port_i[234]
    DIRECTION INPUT ;
    USE SIGNAL ;
    ANTENNAGATEAREA 0.213000 ;
    PORT
      LAYER met3 ;
        RECT 0.000 322.360 4.000 322.960 ;
    END
  END core_port_i[234]
  PIN core_port_i[235]
    DIRECTION INPUT ;
    USE SIGNAL ;
    ANTENNAGATEAREA 0.213000 ;
    PORT
      LAYER met3 ;
        RECT 0.000 323.720 4.000 324.320 ;
    END
  END core_port_i[235]
  PIN core_port_i[236]
    DIRECTION INPUT ;
    USE SIGNAL ;
    ANTENNAGATEAREA 0.213000 ;
    PORT
      LAYER met3 ;
        RECT 0.000 325.080 4.000 325.680 ;
    END
  END core_port_i[236]
  PIN core_port_i[237]
    DIRECTION INPUT ;
    USE SIGNAL ;
    ANTENNAGATEAREA 0.213000 ;
    PORT
      LAYER met3 ;
        RECT 0.000 326.440 4.000 327.040 ;
    END
  END core_port_i[237]
  PIN core_port_i[238]
    DIRECTION INPUT ;
    USE SIGNAL ;
    ANTENNAGATEAREA 0.213000 ;
    PORT
      LAYER met3 ;
        RECT 0.000 327.800 4.000 328.400 ;
    END
  END core_port_i[238]
  PIN core_port_i[239]
    DIRECTION INPUT ;
    USE SIGNAL ;
    ANTENNAGATEAREA 0.247500 ;
    PORT
      LAYER met3 ;
        RECT 0.000 329.160 4.000 329.760 ;
    END
  END core_port_i[239]
  PIN core_port_i[23]
    DIRECTION INPUT ;
    USE SIGNAL ;
    ANTENNAGATEAREA 0.247500 ;
    PORT
      LAYER met3 ;
        RECT 0.000 35.400 4.000 36.000 ;
    END
  END core_port_i[23]
  PIN core_port_i[240]
    DIRECTION INPUT ;
    USE SIGNAL ;
    ANTENNAGATEAREA 0.247500 ;
    PORT
      LAYER met3 ;
        RECT 0.000 330.520 4.000 331.120 ;
    END
  END core_port_i[240]
  PIN core_port_i[241]
    DIRECTION INPUT ;
    USE SIGNAL ;
    ANTENNAGATEAREA 0.247500 ;
    PORT
      LAYER met3 ;
        RECT 0.000 331.880 4.000 332.480 ;
    END
  END core_port_i[241]
  PIN core_port_i[242]
    DIRECTION INPUT ;
    USE SIGNAL ;
    ANTENNAGATEAREA 0.213000 ;
    PORT
      LAYER met3 ;
        RECT 0.000 333.240 4.000 333.840 ;
    END
  END core_port_i[242]
  PIN core_port_i[243]
    DIRECTION INPUT ;
    USE SIGNAL ;
    ANTENNAGATEAREA 0.247500 ;
    PORT
      LAYER met3 ;
        RECT 0.000 334.600 4.000 335.200 ;
    END
  END core_port_i[243]
  PIN core_port_i[244]
    DIRECTION INPUT ;
    USE SIGNAL ;
    ANTENNAGATEAREA 0.213000 ;
    PORT
      LAYER met3 ;
        RECT 0.000 335.960 4.000 336.560 ;
    END
  END core_port_i[244]
  PIN core_port_i[245]
    DIRECTION INPUT ;
    USE SIGNAL ;
    ANTENNAGATEAREA 0.213000 ;
    PORT
      LAYER met3 ;
        RECT 0.000 337.320 4.000 337.920 ;
    END
  END core_port_i[245]
  PIN core_port_i[246]
    DIRECTION INPUT ;
    USE SIGNAL ;
    ANTENNAGATEAREA 0.247500 ;
    PORT
      LAYER met3 ;
        RECT 0.000 338.680 4.000 339.280 ;
    END
  END core_port_i[246]
  PIN core_port_i[247]
    DIRECTION INPUT ;
    USE SIGNAL ;
    ANTENNAGATEAREA 0.213000 ;
    PORT
      LAYER met3 ;
        RECT 0.000 340.040 4.000 340.640 ;
    END
  END core_port_i[247]
  PIN core_port_i[248]
    DIRECTION INPUT ;
    USE SIGNAL ;
    ANTENNAGATEAREA 0.213000 ;
    PORT
      LAYER met3 ;
        RECT 0.000 341.400 4.000 342.000 ;
    END
  END core_port_i[248]
  PIN core_port_i[249]
    DIRECTION INPUT ;
    USE SIGNAL ;
    ANTENNAGATEAREA 0.213000 ;
    PORT
      LAYER met3 ;
        RECT 0.000 342.760 4.000 343.360 ;
    END
  END core_port_i[249]
  PIN core_port_i[24]
    DIRECTION INPUT ;
    USE SIGNAL ;
    ANTENNAGATEAREA 0.247500 ;
    PORT
      LAYER met3 ;
        RECT 0.000 36.760 4.000 37.360 ;
    END
  END core_port_i[24]
  PIN core_port_i[250]
    DIRECTION INPUT ;
    USE SIGNAL ;
    ANTENNAGATEAREA 0.247500 ;
    PORT
      LAYER met3 ;
        RECT 0.000 344.120 4.000 344.720 ;
    END
  END core_port_i[250]
  PIN core_port_i[251]
    DIRECTION INPUT ;
    USE SIGNAL ;
    ANTENNAGATEAREA 0.213000 ;
    PORT
      LAYER met3 ;
        RECT 0.000 345.480 4.000 346.080 ;
    END
  END core_port_i[251]
  PIN core_port_i[252]
    DIRECTION INPUT ;
    USE SIGNAL ;
    ANTENNAGATEAREA 0.213000 ;
    PORT
      LAYER met3 ;
        RECT 0.000 346.840 4.000 347.440 ;
    END
  END core_port_i[252]
  PIN core_port_i[253]
    DIRECTION INPUT ;
    USE SIGNAL ;
    ANTENNAGATEAREA 0.213000 ;
    PORT
      LAYER met3 ;
        RECT 0.000 348.200 4.000 348.800 ;
    END
  END core_port_i[253]
  PIN core_port_i[254]
    DIRECTION INPUT ;
    USE SIGNAL ;
    ANTENNAGATEAREA 0.213000 ;
    PORT
      LAYER met3 ;
        RECT 0.000 349.560 4.000 350.160 ;
    END
  END core_port_i[254]
  PIN core_port_i[255]
    DIRECTION INPUT ;
    USE SIGNAL ;
    ANTENNAGATEAREA 0.213000 ;
    PORT
      LAYER met3 ;
        RECT 0.000 350.920 4.000 351.520 ;
    END
  END core_port_i[255]
  PIN core_port_i[256]
    DIRECTION INPUT ;
    USE SIGNAL ;
    ANTENNAGATEAREA 0.213000 ;
    PORT
      LAYER met3 ;
        RECT 0.000 352.280 4.000 352.880 ;
    END
  END core_port_i[256]
  PIN core_port_i[257]
    DIRECTION INPUT ;
    USE SIGNAL ;
    ANTENNAGATEAREA 0.213000 ;
    PORT
      LAYER met3 ;
        RECT 0.000 353.640 4.000 354.240 ;
    END
  END core_port_i[257]
  PIN core_port_i[258]
    DIRECTION INPUT ;
    USE SIGNAL ;
    ANTENNAGATEAREA 0.213000 ;
    PORT
      LAYER met3 ;
        RECT 0.000 355.000 4.000 355.600 ;
    END
  END core_port_i[258]
  PIN core_port_i[259]
    DIRECTION INPUT ;
    USE SIGNAL ;
    ANTENNAGATEAREA 0.213000 ;
    PORT
      LAYER met3 ;
        RECT 0.000 356.360 4.000 356.960 ;
    END
  END core_port_i[259]
  PIN core_port_i[25]
    DIRECTION INPUT ;
    USE SIGNAL ;
    ANTENNAGATEAREA 0.247500 ;
    PORT
      LAYER met3 ;
        RECT 0.000 38.120 4.000 38.720 ;
    END
  END core_port_i[25]
  PIN core_port_i[260]
    DIRECTION INPUT ;
    USE SIGNAL ;
    ANTENNAGATEAREA 0.213000 ;
    PORT
      LAYER met3 ;
        RECT 0.000 357.720 4.000 358.320 ;
    END
  END core_port_i[260]
  PIN core_port_i[261]
    DIRECTION INPUT ;
    USE SIGNAL ;
    ANTENNAGATEAREA 0.213000 ;
    PORT
      LAYER met3 ;
        RECT 0.000 359.080 4.000 359.680 ;
    END
  END core_port_i[261]
  PIN core_port_i[262]
    DIRECTION INPUT ;
    USE SIGNAL ;
    ANTENNAGATEAREA 0.213000 ;
    PORT
      LAYER met3 ;
        RECT 0.000 360.440 4.000 361.040 ;
    END
  END core_port_i[262]
  PIN core_port_i[263]
    DIRECTION INPUT ;
    USE SIGNAL ;
    ANTENNAGATEAREA 0.213000 ;
    PORT
      LAYER met3 ;
        RECT 0.000 361.800 4.000 362.400 ;
    END
  END core_port_i[263]
  PIN core_port_i[264]
    DIRECTION INPUT ;
    USE SIGNAL ;
    ANTENNAGATEAREA 0.213000 ;
    PORT
      LAYER met3 ;
        RECT 0.000 363.160 4.000 363.760 ;
    END
  END core_port_i[264]
  PIN core_port_i[265]
    DIRECTION INPUT ;
    USE SIGNAL ;
    ANTENNAGATEAREA 0.213000 ;
    PORT
      LAYER met3 ;
        RECT 0.000 364.520 4.000 365.120 ;
    END
  END core_port_i[265]
  PIN core_port_i[266]
    DIRECTION INPUT ;
    USE SIGNAL ;
    ANTENNAGATEAREA 0.213000 ;
    PORT
      LAYER met3 ;
        RECT 0.000 365.880 4.000 366.480 ;
    END
  END core_port_i[266]
  PIN core_port_i[267]
    DIRECTION INPUT ;
    USE SIGNAL ;
    ANTENNAGATEAREA 0.213000 ;
    PORT
      LAYER met3 ;
        RECT 0.000 367.240 4.000 367.840 ;
    END
  END core_port_i[267]
  PIN core_port_i[268]
    DIRECTION INPUT ;
    USE SIGNAL ;
    ANTENNAGATEAREA 0.213000 ;
    PORT
      LAYER met3 ;
        RECT 0.000 368.600 4.000 369.200 ;
    END
  END core_port_i[268]
  PIN core_port_i[269]
    DIRECTION INPUT ;
    USE SIGNAL ;
    ANTENNAGATEAREA 0.213000 ;
    PORT
      LAYER met3 ;
        RECT 0.000 369.960 4.000 370.560 ;
    END
  END core_port_i[269]
  PIN core_port_i[26]
    DIRECTION INPUT ;
    USE SIGNAL ;
    ANTENNAGATEAREA 0.247500 ;
    PORT
      LAYER met3 ;
        RECT 0.000 39.480 4.000 40.080 ;
    END
  END core_port_i[26]
  PIN core_port_i[270]
    DIRECTION INPUT ;
    USE SIGNAL ;
    ANTENNAGATEAREA 0.213000 ;
    PORT
      LAYER met3 ;
        RECT 0.000 371.320 4.000 371.920 ;
    END
  END core_port_i[270]
  PIN core_port_i[271]
    DIRECTION INPUT ;
    USE SIGNAL ;
    ANTENNAGATEAREA 0.426000 ;
    PORT
      LAYER met3 ;
        RECT 0.000 372.680 4.000 373.280 ;
    END
  END core_port_i[271]
  PIN core_port_i[272]
    DIRECTION INPUT ;
    USE SIGNAL ;
    ANTENNAGATEAREA 0.213000 ;
    PORT
      LAYER met3 ;
        RECT 0.000 374.040 4.000 374.640 ;
    END
  END core_port_i[272]
  PIN core_port_i[273]
    DIRECTION INPUT ;
    USE SIGNAL ;
    ANTENNAGATEAREA 0.213000 ;
    PORT
      LAYER met3 ;
        RECT 0.000 375.400 4.000 376.000 ;
    END
  END core_port_i[273]
  PIN core_port_i[274]
    DIRECTION INPUT ;
    USE SIGNAL ;
    ANTENNAGATEAREA 0.213000 ;
    PORT
      LAYER met3 ;
        RECT 0.000 376.760 4.000 377.360 ;
    END
  END core_port_i[274]
  PIN core_port_i[275]
    DIRECTION INPUT ;
    USE SIGNAL ;
    ANTENNAGATEAREA 0.213000 ;
    PORT
      LAYER met3 ;
        RECT 0.000 378.120 4.000 378.720 ;
    END
  END core_port_i[275]
  PIN core_port_i[276]
    DIRECTION INPUT ;
    USE SIGNAL ;
    ANTENNAGATEAREA 0.213000 ;
    PORT
      LAYER met3 ;
        RECT 0.000 379.480 4.000 380.080 ;
    END
  END core_port_i[276]
  PIN core_port_i[277]
    DIRECTION INPUT ;
    USE SIGNAL ;
    ANTENNAGATEAREA 0.213000 ;
    PORT
      LAYER met3 ;
        RECT 0.000 380.840 4.000 381.440 ;
    END
  END core_port_i[277]
  PIN core_port_i[278]
    DIRECTION INPUT ;
    USE SIGNAL ;
    ANTENNAGATEAREA 0.213000 ;
    PORT
      LAYER met3 ;
        RECT 0.000 382.200 4.000 382.800 ;
    END
  END core_port_i[278]
  PIN core_port_i[279]
    DIRECTION INPUT ;
    USE SIGNAL ;
    ANTENNAGATEAREA 0.213000 ;
    PORT
      LAYER met3 ;
        RECT 0.000 383.560 4.000 384.160 ;
    END
  END core_port_i[279]
  PIN core_port_i[27]
    DIRECTION INPUT ;
    USE SIGNAL ;
    ANTENNAGATEAREA 0.247500 ;
    PORT
      LAYER met3 ;
        RECT 0.000 40.840 4.000 41.440 ;
    END
  END core_port_i[27]
  PIN core_port_i[280]
    DIRECTION INPUT ;
    USE SIGNAL ;
    ANTENNAGATEAREA 0.213000 ;
    PORT
      LAYER met3 ;
        RECT 0.000 384.920 4.000 385.520 ;
    END
  END core_port_i[280]
  PIN core_port_i[281]
    DIRECTION INPUT ;
    USE SIGNAL ;
    ANTENNAGATEAREA 0.213000 ;
    PORT
      LAYER met3 ;
        RECT 0.000 386.280 4.000 386.880 ;
    END
  END core_port_i[281]
  PIN core_port_i[282]
    DIRECTION INPUT ;
    USE SIGNAL ;
    ANTENNAGATEAREA 0.213000 ;
    PORT
      LAYER met3 ;
        RECT 0.000 387.640 4.000 388.240 ;
    END
  END core_port_i[282]
  PIN core_port_i[283]
    DIRECTION INPUT ;
    USE SIGNAL ;
    ANTENNAGATEAREA 0.213000 ;
    PORT
      LAYER met3 ;
        RECT 0.000 389.000 4.000 389.600 ;
    END
  END core_port_i[283]
  PIN core_port_i[284]
    DIRECTION INPUT ;
    USE SIGNAL ;
    ANTENNAGATEAREA 0.213000 ;
    PORT
      LAYER met3 ;
        RECT 0.000 390.360 4.000 390.960 ;
    END
  END core_port_i[284]
  PIN core_port_i[285]
    DIRECTION INPUT ;
    USE SIGNAL ;
    ANTENNAGATEAREA 0.213000 ;
    PORT
      LAYER met3 ;
        RECT 0.000 391.720 4.000 392.320 ;
    END
  END core_port_i[285]
  PIN core_port_i[286]
    DIRECTION INPUT ;
    USE SIGNAL ;
    ANTENNAGATEAREA 0.213000 ;
    PORT
      LAYER met3 ;
        RECT 0.000 393.080 4.000 393.680 ;
    END
  END core_port_i[286]
  PIN core_port_i[287]
    DIRECTION INPUT ;
    USE SIGNAL ;
    ANTENNAGATEAREA 0.213000 ;
    PORT
      LAYER met3 ;
        RECT 0.000 394.440 4.000 395.040 ;
    END
  END core_port_i[287]
  PIN core_port_i[288]
    DIRECTION INPUT ;
    USE SIGNAL ;
    ANTENNAGATEAREA 0.213000 ;
    PORT
      LAYER met3 ;
        RECT 0.000 395.800 4.000 396.400 ;
    END
  END core_port_i[288]
  PIN core_port_i[289]
    DIRECTION INPUT ;
    USE SIGNAL ;
    ANTENNAGATEAREA 0.213000 ;
    PORT
      LAYER met3 ;
        RECT 0.000 397.160 4.000 397.760 ;
    END
  END core_port_i[289]
  PIN core_port_i[28]
    DIRECTION INPUT ;
    USE SIGNAL ;
    ANTENNAGATEAREA 0.247500 ;
    PORT
      LAYER met3 ;
        RECT 0.000 42.200 4.000 42.800 ;
    END
  END core_port_i[28]
  PIN core_port_i[290]
    DIRECTION INPUT ;
    USE SIGNAL ;
    ANTENNAGATEAREA 0.213000 ;
    PORT
      LAYER met3 ;
        RECT 0.000 398.520 4.000 399.120 ;
    END
  END core_port_i[290]
  PIN core_port_i[291]
    DIRECTION INPUT ;
    USE SIGNAL ;
    ANTENNAGATEAREA 0.213000 ;
    PORT
      LAYER met3 ;
        RECT 0.000 399.880 4.000 400.480 ;
    END
  END core_port_i[291]
  PIN core_port_i[292]
    DIRECTION INPUT ;
    USE SIGNAL ;
    ANTENNAGATEAREA 0.213000 ;
    PORT
      LAYER met3 ;
        RECT 0.000 401.240 4.000 401.840 ;
    END
  END core_port_i[292]
  PIN core_port_i[293]
    DIRECTION INPUT ;
    USE SIGNAL ;
    ANTENNAGATEAREA 0.213000 ;
    PORT
      LAYER met3 ;
        RECT 0.000 402.600 4.000 403.200 ;
    END
  END core_port_i[293]
  PIN core_port_i[294]
    DIRECTION INPUT ;
    USE SIGNAL ;
    ANTENNAGATEAREA 0.213000 ;
    PORT
      LAYER met3 ;
        RECT 0.000 403.960 4.000 404.560 ;
    END
  END core_port_i[294]
  PIN core_port_i[295]
    DIRECTION INPUT ;
    USE SIGNAL ;
    ANTENNAGATEAREA 0.213000 ;
    PORT
      LAYER met3 ;
        RECT 0.000 405.320 4.000 405.920 ;
    END
  END core_port_i[295]
  PIN core_port_i[296]
    DIRECTION INPUT ;
    USE SIGNAL ;
    ANTENNAGATEAREA 0.213000 ;
    PORT
      LAYER met3 ;
        RECT 0.000 406.680 4.000 407.280 ;
    END
  END core_port_i[296]
  PIN core_port_i[297]
    DIRECTION INPUT ;
    USE SIGNAL ;
    ANTENNAGATEAREA 0.213000 ;
    PORT
      LAYER met3 ;
        RECT 0.000 408.040 4.000 408.640 ;
    END
  END core_port_i[297]
  PIN core_port_i[298]
    DIRECTION INPUT ;
    USE SIGNAL ;
    ANTENNAGATEAREA 0.213000 ;
    PORT
      LAYER met3 ;
        RECT 0.000 409.400 4.000 410.000 ;
    END
  END core_port_i[298]
  PIN core_port_i[299]
    DIRECTION INPUT ;
    USE SIGNAL ;
    ANTENNAGATEAREA 0.213000 ;
    PORT
      LAYER met3 ;
        RECT 0.000 410.760 4.000 411.360 ;
    END
  END core_port_i[299]
  PIN core_port_i[29]
    DIRECTION INPUT ;
    USE SIGNAL ;
    ANTENNAGATEAREA 0.247500 ;
    PORT
      LAYER met3 ;
        RECT 0.000 43.560 4.000 44.160 ;
    END
  END core_port_i[29]
  PIN core_port_i[2]
    DIRECTION INPUT ;
    USE SIGNAL ;
    ANTENNAGATEAREA 0.247500 ;
    PORT
      LAYER met3 ;
        RECT 0.000 6.840 4.000 7.440 ;
    END
  END core_port_i[2]
  PIN core_port_i[300]
    DIRECTION INPUT ;
    USE SIGNAL ;
    ANTENNAGATEAREA 0.213000 ;
    PORT
      LAYER met3 ;
        RECT 0.000 412.120 4.000 412.720 ;
    END
  END core_port_i[300]
  PIN core_port_i[301]
    DIRECTION INPUT ;
    USE SIGNAL ;
    ANTENNAGATEAREA 0.213000 ;
    PORT
      LAYER met3 ;
        RECT 0.000 413.480 4.000 414.080 ;
    END
  END core_port_i[301]
  PIN core_port_i[302]
    DIRECTION INPUT ;
    USE SIGNAL ;
    ANTENNAGATEAREA 0.213000 ;
    PORT
      LAYER met3 ;
        RECT 0.000 414.840 4.000 415.440 ;
    END
  END core_port_i[302]
  PIN core_port_i[303]
    DIRECTION INPUT ;
    USE SIGNAL ;
    ANTENNAGATEAREA 0.213000 ;
    PORT
      LAYER met3 ;
        RECT 0.000 416.200 4.000 416.800 ;
    END
  END core_port_i[303]
  PIN core_port_i[304]
    DIRECTION INPUT ;
    USE SIGNAL ;
    ANTENNAGATEAREA 0.213000 ;
    PORT
      LAYER met3 ;
        RECT 0.000 417.560 4.000 418.160 ;
    END
  END core_port_i[304]
  PIN core_port_i[305]
    DIRECTION INPUT ;
    USE SIGNAL ;
    ANTENNAGATEAREA 0.213000 ;
    PORT
      LAYER met3 ;
        RECT 0.000 418.920 4.000 419.520 ;
    END
  END core_port_i[305]
  PIN core_port_i[306]
    DIRECTION INPUT ;
    USE SIGNAL ;
    ANTENNAGATEAREA 0.213000 ;
    PORT
      LAYER met3 ;
        RECT 0.000 420.280 4.000 420.880 ;
    END
  END core_port_i[306]
  PIN core_port_i[307]
    DIRECTION INPUT ;
    USE SIGNAL ;
    ANTENNAGATEAREA 0.213000 ;
    PORT
      LAYER met3 ;
        RECT 0.000 421.640 4.000 422.240 ;
    END
  END core_port_i[307]
  PIN core_port_i[308]
    DIRECTION INPUT ;
    USE SIGNAL ;
    ANTENNAGATEAREA 0.247500 ;
    PORT
      LAYER met3 ;
        RECT 0.000 423.000 4.000 423.600 ;
    END
  END core_port_i[308]
  PIN core_port_i[309]
    DIRECTION INPUT ;
    USE SIGNAL ;
    ANTENNAGATEAREA 0.247500 ;
    PORT
      LAYER met3 ;
        RECT 0.000 424.360 4.000 424.960 ;
    END
  END core_port_i[309]
  PIN core_port_i[30]
    DIRECTION INPUT ;
    USE SIGNAL ;
    ANTENNAGATEAREA 0.247500 ;
    PORT
      LAYER met3 ;
        RECT 0.000 44.920 4.000 45.520 ;
    END
  END core_port_i[30]
  PIN core_port_i[310]
    DIRECTION INPUT ;
    USE SIGNAL ;
    ANTENNAGATEAREA 0.247500 ;
    PORT
      LAYER met3 ;
        RECT 0.000 425.720 4.000 426.320 ;
    END
  END core_port_i[310]
  PIN core_port_i[311]
    DIRECTION INPUT ;
    USE SIGNAL ;
    ANTENNAGATEAREA 0.213000 ;
    PORT
      LAYER met3 ;
        RECT 0.000 427.080 4.000 427.680 ;
    END
  END core_port_i[311]
  PIN core_port_i[312]
    DIRECTION INPUT ;
    USE SIGNAL ;
    ANTENNAGATEAREA 0.247500 ;
    PORT
      LAYER met3 ;
        RECT 0.000 428.440 4.000 429.040 ;
    END
  END core_port_i[312]
  PIN core_port_i[313]
    DIRECTION INPUT ;
    USE SIGNAL ;
    ANTENNAGATEAREA 0.247500 ;
    PORT
      LAYER met3 ;
        RECT 0.000 429.800 4.000 430.400 ;
    END
  END core_port_i[313]
  PIN core_port_i[314]
    DIRECTION INPUT ;
    USE SIGNAL ;
    ANTENNAGATEAREA 0.213000 ;
    PORT
      LAYER met3 ;
        RECT 0.000 431.160 4.000 431.760 ;
    END
  END core_port_i[314]
  PIN core_port_i[315]
    DIRECTION INPUT ;
    USE SIGNAL ;
    ANTENNAGATEAREA 0.213000 ;
    PORT
      LAYER met3 ;
        RECT 0.000 432.520 4.000 433.120 ;
    END
  END core_port_i[315]
  PIN core_port_i[316]
    DIRECTION INPUT ;
    USE SIGNAL ;
    ANTENNAGATEAREA 0.247500 ;
    PORT
      LAYER met3 ;
        RECT 0.000 433.880 4.000 434.480 ;
    END
  END core_port_i[316]
  PIN core_port_i[317]
    DIRECTION INPUT ;
    USE SIGNAL ;
    ANTENNAGATEAREA 0.213000 ;
    PORT
      LAYER met3 ;
        RECT 0.000 435.240 4.000 435.840 ;
    END
  END core_port_i[317]
  PIN core_port_i[318]
    DIRECTION INPUT ;
    USE SIGNAL ;
    ANTENNAGATEAREA 0.213000 ;
    PORT
      LAYER met3 ;
        RECT 0.000 436.600 4.000 437.200 ;
    END
  END core_port_i[318]
  PIN core_port_i[319]
    DIRECTION INPUT ;
    USE SIGNAL ;
    ANTENNAGATEAREA 0.213000 ;
    PORT
      LAYER met3 ;
        RECT 0.000 437.960 4.000 438.560 ;
    END
  END core_port_i[319]
  PIN core_port_i[31]
    DIRECTION INPUT ;
    USE SIGNAL ;
    ANTENNAGATEAREA 0.247500 ;
    PORT
      LAYER met3 ;
        RECT 0.000 46.280 4.000 46.880 ;
    END
  END core_port_i[31]
  PIN core_port_i[320]
    DIRECTION INPUT ;
    USE SIGNAL ;
    ANTENNAGATEAREA 0.213000 ;
    PORT
      LAYER met3 ;
        RECT 0.000 439.320 4.000 439.920 ;
    END
  END core_port_i[320]
  PIN core_port_i[321]
    DIRECTION INPUT ;
    USE SIGNAL ;
    ANTENNAGATEAREA 0.247500 ;
    PORT
      LAYER met3 ;
        RECT 0.000 440.680 4.000 441.280 ;
    END
  END core_port_i[321]
  PIN core_port_i[322]
    DIRECTION INPUT ;
    USE SIGNAL ;
    ANTENNAGATEAREA 0.213000 ;
    PORT
      LAYER met3 ;
        RECT 0.000 442.040 4.000 442.640 ;
    END
  END core_port_i[322]
  PIN core_port_i[323]
    DIRECTION INPUT ;
    USE SIGNAL ;
    ANTENNAGATEAREA 0.213000 ;
    PORT
      LAYER met3 ;
        RECT 0.000 443.400 4.000 444.000 ;
    END
  END core_port_i[323]
  PIN core_port_i[324]
    DIRECTION INPUT ;
    USE SIGNAL ;
    ANTENNAGATEAREA 0.213000 ;
    PORT
      LAYER met3 ;
        RECT 0.000 444.760 4.000 445.360 ;
    END
  END core_port_i[324]
  PIN core_port_i[325]
    DIRECTION INPUT ;
    USE SIGNAL ;
    ANTENNAGATEAREA 0.213000 ;
    PORT
      LAYER met3 ;
        RECT 0.000 446.120 4.000 446.720 ;
    END
  END core_port_i[325]
  PIN core_port_i[326]
    DIRECTION INPUT ;
    USE SIGNAL ;
    ANTENNAGATEAREA 0.213000 ;
    PORT
      LAYER met3 ;
        RECT 0.000 447.480 4.000 448.080 ;
    END
  END core_port_i[326]
  PIN core_port_i[327]
    DIRECTION INPUT ;
    USE SIGNAL ;
    ANTENNAGATEAREA 0.213000 ;
    PORT
      LAYER met3 ;
        RECT 0.000 448.840 4.000 449.440 ;
    END
  END core_port_i[327]
  PIN core_port_i[328]
    DIRECTION INPUT ;
    USE SIGNAL ;
    ANTENNAGATEAREA 0.213000 ;
    PORT
      LAYER met3 ;
        RECT 0.000 450.200 4.000 450.800 ;
    END
  END core_port_i[328]
  PIN core_port_i[329]
    DIRECTION INPUT ;
    USE SIGNAL ;
    ANTENNAGATEAREA 0.213000 ;
    PORT
      LAYER met3 ;
        RECT 0.000 451.560 4.000 452.160 ;
    END
  END core_port_i[329]
  PIN core_port_i[32]
    DIRECTION INPUT ;
    USE SIGNAL ;
    ANTENNAGATEAREA 0.426000 ;
    PORT
      LAYER met3 ;
        RECT 0.000 47.640 4.000 48.240 ;
    END
  END core_port_i[32]
  PIN core_port_i[330]
    DIRECTION INPUT ;
    USE SIGNAL ;
    ANTENNAGATEAREA 0.213000 ;
    PORT
      LAYER met3 ;
        RECT 0.000 452.920 4.000 453.520 ;
    END
  END core_port_i[330]
  PIN core_port_i[331]
    DIRECTION INPUT ;
    USE SIGNAL ;
    ANTENNAGATEAREA 0.247500 ;
    PORT
      LAYER met3 ;
        RECT 0.000 454.280 4.000 454.880 ;
    END
  END core_port_i[331]
  PIN core_port_i[332]
    DIRECTION INPUT ;
    USE SIGNAL ;
    ANTENNAGATEAREA 0.213000 ;
    PORT
      LAYER met3 ;
        RECT 0.000 455.640 4.000 456.240 ;
    END
  END core_port_i[332]
  PIN core_port_i[333]
    DIRECTION INPUT ;
    USE SIGNAL ;
    ANTENNAGATEAREA 0.213000 ;
    PORT
      LAYER met3 ;
        RECT 0.000 457.000 4.000 457.600 ;
    END
  END core_port_i[333]
  PIN core_port_i[334]
    DIRECTION INPUT ;
    USE SIGNAL ;
    ANTENNAGATEAREA 0.213000 ;
    PORT
      LAYER met3 ;
        RECT 0.000 458.360 4.000 458.960 ;
    END
  END core_port_i[334]
  PIN core_port_i[335]
    DIRECTION INPUT ;
    USE SIGNAL ;
    ANTENNAGATEAREA 0.213000 ;
    PORT
      LAYER met3 ;
        RECT 0.000 459.720 4.000 460.320 ;
    END
  END core_port_i[335]
  PIN core_port_i[336]
    DIRECTION INPUT ;
    USE SIGNAL ;
    ANTENNAGATEAREA 0.213000 ;
    PORT
      LAYER met3 ;
        RECT 0.000 461.080 4.000 461.680 ;
    END
  END core_port_i[336]
  PIN core_port_i[337]
    DIRECTION INPUT ;
    USE SIGNAL ;
    ANTENNAGATEAREA 0.213000 ;
    PORT
      LAYER met3 ;
        RECT 0.000 462.440 4.000 463.040 ;
    END
  END core_port_i[337]
  PIN core_port_i[338]
    DIRECTION INPUT ;
    USE SIGNAL ;
    ANTENNAGATEAREA 0.213000 ;
    PORT
      LAYER met3 ;
        RECT 0.000 463.800 4.000 464.400 ;
    END
  END core_port_i[338]
  PIN core_port_i[339]
    DIRECTION INPUT ;
    USE SIGNAL ;
    ANTENNAGATEAREA 0.213000 ;
    PORT
      LAYER met3 ;
        RECT 0.000 465.160 4.000 465.760 ;
    END
  END core_port_i[339]
  PIN core_port_i[33]
    DIRECTION INPUT ;
    USE SIGNAL ;
    ANTENNAGATEAREA 0.426000 ;
    PORT
      LAYER met3 ;
        RECT 0.000 49.000 4.000 49.600 ;
    END
  END core_port_i[33]
  PIN core_port_i[340]
    DIRECTION INPUT ;
    USE SIGNAL ;
    ANTENNAGATEAREA 0.426000 ;
    PORT
      LAYER met3 ;
        RECT 0.000 466.520 4.000 467.120 ;
    END
  END core_port_i[340]
  PIN core_port_i[341]
    DIRECTION INPUT ;
    USE SIGNAL ;
    ANTENNAGATEAREA 0.159000 ;
    PORT
      LAYER met3 ;
        RECT 0.000 467.880 4.000 468.480 ;
    END
  END core_port_i[341]
  PIN core_port_i[342]
    DIRECTION INPUT ;
    USE SIGNAL ;
    ANTENNAGATEAREA 0.159000 ;
    PORT
      LAYER met3 ;
        RECT 0.000 469.240 4.000 469.840 ;
    END
  END core_port_i[342]
  PIN core_port_i[343]
    DIRECTION INPUT ;
    USE SIGNAL ;
    ANTENNAGATEAREA 0.159000 ;
    PORT
      LAYER met3 ;
        RECT 0.000 470.600 4.000 471.200 ;
    END
  END core_port_i[343]
  PIN core_port_i[344]
    DIRECTION INPUT ;
    USE SIGNAL ;
    ANTENNAGATEAREA 0.247500 ;
    PORT
      LAYER met3 ;
        RECT 0.000 471.960 4.000 472.560 ;
    END
  END core_port_i[344]
  PIN core_port_i[345]
    DIRECTION INPUT ;
    USE SIGNAL ;
    ANTENNAGATEAREA 0.213000 ;
    PORT
      LAYER met3 ;
        RECT 0.000 473.320 4.000 473.920 ;
    END
  END core_port_i[345]
  PIN core_port_i[346]
    DIRECTION INPUT ;
    USE SIGNAL ;
    ANTENNAGATEAREA 0.247500 ;
    PORT
      LAYER met3 ;
        RECT 0.000 474.680 4.000 475.280 ;
    END
  END core_port_i[346]
  PIN core_port_i[347]
    DIRECTION INPUT ;
    USE SIGNAL ;
    ANTENNAGATEAREA 0.247500 ;
    PORT
      LAYER met3 ;
        RECT 0.000 476.040 4.000 476.640 ;
    END
  END core_port_i[347]
  PIN core_port_i[348]
    DIRECTION INPUT ;
    USE SIGNAL ;
    ANTENNAGATEAREA 0.247500 ;
    PORT
      LAYER met3 ;
        RECT 0.000 477.400 4.000 478.000 ;
    END
  END core_port_i[348]
  PIN core_port_i[349]
    DIRECTION INPUT ;
    USE SIGNAL ;
    ANTENNAGATEAREA 0.247500 ;
    PORT
      LAYER met3 ;
        RECT 0.000 478.760 4.000 479.360 ;
    END
  END core_port_i[349]
  PIN core_port_i[34]
    DIRECTION INPUT ;
    USE SIGNAL ;
    ANTENNAGATEAREA 0.426000 ;
    PORT
      LAYER met3 ;
        RECT 0.000 50.360 4.000 50.960 ;
    END
  END core_port_i[34]
  PIN core_port_i[350]
    DIRECTION INPUT ;
    USE SIGNAL ;
    ANTENNAGATEAREA 0.247500 ;
    PORT
      LAYER met3 ;
        RECT 0.000 480.120 4.000 480.720 ;
    END
  END core_port_i[350]
  PIN core_port_i[351]
    DIRECTION INPUT ;
    USE SIGNAL ;
    ANTENNAGATEAREA 0.247500 ;
    PORT
      LAYER met3 ;
        RECT 0.000 481.480 4.000 482.080 ;
    END
  END core_port_i[351]
  PIN core_port_i[352]
    DIRECTION INPUT ;
    USE SIGNAL ;
    ANTENNAGATEAREA 0.247500 ;
    PORT
      LAYER met3 ;
        RECT 0.000 482.840 4.000 483.440 ;
    END
  END core_port_i[352]
  PIN core_port_i[353]
    DIRECTION INPUT ;
    USE SIGNAL ;
    ANTENNAGATEAREA 0.247500 ;
    PORT
      LAYER met3 ;
        RECT 0.000 484.200 4.000 484.800 ;
    END
  END core_port_i[353]
  PIN core_port_i[354]
    DIRECTION INPUT ;
    USE SIGNAL ;
    ANTENNAGATEAREA 0.247500 ;
    PORT
      LAYER met3 ;
        RECT 0.000 485.560 4.000 486.160 ;
    END
  END core_port_i[354]
  PIN core_port_i[355]
    DIRECTION INPUT ;
    USE SIGNAL ;
    ANTENNAGATEAREA 0.247500 ;
    PORT
      LAYER met3 ;
        RECT 0.000 486.920 4.000 487.520 ;
    END
  END core_port_i[355]
  PIN core_port_i[356]
    DIRECTION INPUT ;
    USE SIGNAL ;
    ANTENNAGATEAREA 0.247500 ;
    PORT
      LAYER met3 ;
        RECT 0.000 488.280 4.000 488.880 ;
    END
  END core_port_i[356]
  PIN core_port_i[357]
    DIRECTION INPUT ;
    USE SIGNAL ;
    ANTENNAGATEAREA 0.247500 ;
    PORT
      LAYER met3 ;
        RECT 0.000 489.640 4.000 490.240 ;
    END
  END core_port_i[357]
  PIN core_port_i[358]
    DIRECTION INPUT ;
    USE SIGNAL ;
    ANTENNAGATEAREA 0.247500 ;
    PORT
      LAYER met3 ;
        RECT 0.000 491.000 4.000 491.600 ;
    END
  END core_port_i[358]
  PIN core_port_i[359]
    DIRECTION INPUT ;
    USE SIGNAL ;
    ANTENNAGATEAREA 0.247500 ;
    PORT
      LAYER met3 ;
        RECT 0.000 492.360 4.000 492.960 ;
    END
  END core_port_i[359]
  PIN core_port_i[35]
    DIRECTION INPUT ;
    USE SIGNAL ;
    ANTENNAGATEAREA 0.247500 ;
    PORT
      LAYER met3 ;
        RECT 0.000 51.720 4.000 52.320 ;
    END
  END core_port_i[35]
  PIN core_port_i[360]
    DIRECTION INPUT ;
    USE SIGNAL ;
    ANTENNAGATEAREA 0.247500 ;
    PORT
      LAYER met3 ;
        RECT 0.000 493.720 4.000 494.320 ;
    END
  END core_port_i[360]
  PIN core_port_i[361]
    DIRECTION INPUT ;
    USE SIGNAL ;
    ANTENNAGATEAREA 0.247500 ;
    PORT
      LAYER met3 ;
        RECT 0.000 495.080 4.000 495.680 ;
    END
  END core_port_i[361]
  PIN core_port_i[362]
    DIRECTION INPUT ;
    USE SIGNAL ;
    ANTENNAGATEAREA 0.247500 ;
    PORT
      LAYER met3 ;
        RECT 0.000 496.440 4.000 497.040 ;
    END
  END core_port_i[362]
  PIN core_port_i[363]
    DIRECTION INPUT ;
    USE SIGNAL ;
    ANTENNAGATEAREA 0.247500 ;
    PORT
      LAYER met3 ;
        RECT 0.000 497.800 4.000 498.400 ;
    END
  END core_port_i[363]
  PIN core_port_i[364]
    DIRECTION INPUT ;
    USE SIGNAL ;
    ANTENNAGATEAREA 0.247500 ;
    PORT
      LAYER met3 ;
        RECT 0.000 499.160 4.000 499.760 ;
    END
  END core_port_i[364]
  PIN core_port_i[365]
    DIRECTION INPUT ;
    USE SIGNAL ;
    ANTENNAGATEAREA 0.247500 ;
    PORT
      LAYER met3 ;
        RECT 0.000 500.520 4.000 501.120 ;
    END
  END core_port_i[365]
  PIN core_port_i[366]
    DIRECTION INPUT ;
    USE SIGNAL ;
    ANTENNAGATEAREA 0.247500 ;
    PORT
      LAYER met3 ;
        RECT 0.000 501.880 4.000 502.480 ;
    END
  END core_port_i[366]
  PIN core_port_i[367]
    DIRECTION INPUT ;
    USE SIGNAL ;
    ANTENNAGATEAREA 0.247500 ;
    PORT
      LAYER met3 ;
        RECT 0.000 503.240 4.000 503.840 ;
    END
  END core_port_i[367]
  PIN core_port_i[368]
    DIRECTION INPUT ;
    USE SIGNAL ;
    ANTENNAGATEAREA 0.247500 ;
    PORT
      LAYER met3 ;
        RECT 0.000 504.600 4.000 505.200 ;
    END
  END core_port_i[368]
  PIN core_port_i[369]
    DIRECTION INPUT ;
    USE SIGNAL ;
    ANTENNAGATEAREA 0.247500 ;
    PORT
      LAYER met3 ;
        RECT 0.000 505.960 4.000 506.560 ;
    END
  END core_port_i[369]
  PIN core_port_i[36]
    DIRECTION INPUT ;
    USE SIGNAL ;
    ANTENNAGATEAREA 0.426000 ;
    PORT
      LAYER met3 ;
        RECT 0.000 53.080 4.000 53.680 ;
    END
  END core_port_i[36]
  PIN core_port_i[370]
    DIRECTION INPUT ;
    USE SIGNAL ;
    ANTENNAGATEAREA 0.247500 ;
    PORT
      LAYER met3 ;
        RECT 0.000 507.320 4.000 507.920 ;
    END
  END core_port_i[370]
  PIN core_port_i[371]
    DIRECTION INPUT ;
    USE SIGNAL ;
    ANTENNAGATEAREA 0.247500 ;
    PORT
      LAYER met3 ;
        RECT 0.000 508.680 4.000 509.280 ;
    END
  END core_port_i[371]
  PIN core_port_i[372]
    DIRECTION INPUT ;
    USE SIGNAL ;
    ANTENNAGATEAREA 0.247500 ;
    PORT
      LAYER met3 ;
        RECT 0.000 510.040 4.000 510.640 ;
    END
  END core_port_i[372]
  PIN core_port_i[373]
    DIRECTION INPUT ;
    USE SIGNAL ;
    ANTENNAGATEAREA 0.247500 ;
    PORT
      LAYER met3 ;
        RECT 0.000 511.400 4.000 512.000 ;
    END
  END core_port_i[373]
  PIN core_port_i[374]
    DIRECTION INPUT ;
    USE SIGNAL ;
    ANTENNAGATEAREA 0.247500 ;
    PORT
      LAYER met3 ;
        RECT 0.000 512.760 4.000 513.360 ;
    END
  END core_port_i[374]
  PIN core_port_i[375]
    DIRECTION INPUT ;
    USE SIGNAL ;
    ANTENNAGATEAREA 0.247500 ;
    PORT
      LAYER met3 ;
        RECT 0.000 514.120 4.000 514.720 ;
    END
  END core_port_i[375]
  PIN core_port_i[376]
    DIRECTION INPUT ;
    USE SIGNAL ;
    ANTENNAGATEAREA 0.247500 ;
    PORT
      LAYER met3 ;
        RECT 0.000 515.480 4.000 516.080 ;
    END
  END core_port_i[376]
  PIN core_port_i[377]
    DIRECTION INPUT ;
    USE SIGNAL ;
    ANTENNAGATEAREA 0.213000 ;
    PORT
      LAYER met3 ;
        RECT 0.000 516.840 4.000 517.440 ;
    END
  END core_port_i[377]
  PIN core_port_i[378]
    DIRECTION INPUT ;
    USE SIGNAL ;
    ANTENNAGATEAREA 0.213000 ;
    PORT
      LAYER met3 ;
        RECT 0.000 518.200 4.000 518.800 ;
    END
  END core_port_i[378]
  PIN core_port_i[379]
    DIRECTION INPUT ;
    USE SIGNAL ;
    ANTENNAGATEAREA 0.213000 ;
    PORT
      LAYER met3 ;
        RECT 0.000 519.560 4.000 520.160 ;
    END
  END core_port_i[379]
  PIN core_port_i[37]
    DIRECTION INPUT ;
    USE SIGNAL ;
    ANTENNAGATEAREA 0.247500 ;
    PORT
      LAYER met3 ;
        RECT 0.000 54.440 4.000 55.040 ;
    END
  END core_port_i[37]
  PIN core_port_i[380]
    DIRECTION INPUT ;
    USE SIGNAL ;
    ANTENNAGATEAREA 0.213000 ;
    PORT
      LAYER met3 ;
        RECT 0.000 520.920 4.000 521.520 ;
    END
  END core_port_i[380]
  PIN core_port_i[381]
    DIRECTION INPUT ;
    USE SIGNAL ;
    ANTENNAGATEAREA 0.213000 ;
    PORT
      LAYER met3 ;
        RECT 0.000 522.280 4.000 522.880 ;
    END
  END core_port_i[381]
  PIN core_port_i[382]
    DIRECTION INPUT ;
    USE SIGNAL ;
    ANTENNAGATEAREA 0.213000 ;
    PORT
      LAYER met3 ;
        RECT 0.000 523.640 4.000 524.240 ;
    END
  END core_port_i[382]
  PIN core_port_i[383]
    DIRECTION INPUT ;
    USE SIGNAL ;
    ANTENNAGATEAREA 0.213000 ;
    PORT
      LAYER met3 ;
        RECT 0.000 525.000 4.000 525.600 ;
    END
  END core_port_i[383]
  PIN core_port_i[384]
    DIRECTION INPUT ;
    USE SIGNAL ;
    ANTENNAGATEAREA 0.213000 ;
    PORT
      LAYER met3 ;
        RECT 0.000 526.360 4.000 526.960 ;
    END
  END core_port_i[384]
  PIN core_port_i[385]
    DIRECTION INPUT ;
    USE SIGNAL ;
    ANTENNAGATEAREA 0.213000 ;
    PORT
      LAYER met3 ;
        RECT 0.000 527.720 4.000 528.320 ;
    END
  END core_port_i[385]
  PIN core_port_i[386]
    DIRECTION INPUT ;
    USE SIGNAL ;
    ANTENNAGATEAREA 0.213000 ;
    PORT
      LAYER met3 ;
        RECT 0.000 529.080 4.000 529.680 ;
    END
  END core_port_i[386]
  PIN core_port_i[387]
    DIRECTION INPUT ;
    USE SIGNAL ;
    ANTENNAGATEAREA 0.213000 ;
    PORT
      LAYER met3 ;
        RECT 0.000 530.440 4.000 531.040 ;
    END
  END core_port_i[387]
  PIN core_port_i[388]
    DIRECTION INPUT ;
    USE SIGNAL ;
    ANTENNAGATEAREA 0.213000 ;
    PORT
      LAYER met3 ;
        RECT 0.000 531.800 4.000 532.400 ;
    END
  END core_port_i[388]
  PIN core_port_i[389]
    DIRECTION INPUT ;
    USE SIGNAL ;
    ANTENNAGATEAREA 0.213000 ;
    PORT
      LAYER met3 ;
        RECT 0.000 533.160 4.000 533.760 ;
    END
  END core_port_i[389]
  PIN core_port_i[38]
    DIRECTION INPUT ;
    USE SIGNAL ;
    ANTENNAGATEAREA 0.247500 ;
    PORT
      LAYER met3 ;
        RECT 0.000 55.800 4.000 56.400 ;
    END
  END core_port_i[38]
  PIN core_port_i[390]
    DIRECTION INPUT ;
    USE SIGNAL ;
    ANTENNAGATEAREA 0.213000 ;
    PORT
      LAYER met3 ;
        RECT 0.000 534.520 4.000 535.120 ;
    END
  END core_port_i[390]
  PIN core_port_i[391]
    DIRECTION INPUT ;
    USE SIGNAL ;
    ANTENNAGATEAREA 0.213000 ;
    PORT
      LAYER met3 ;
        RECT 0.000 535.880 4.000 536.480 ;
    END
  END core_port_i[391]
  PIN core_port_i[392]
    DIRECTION INPUT ;
    USE SIGNAL ;
    ANTENNAGATEAREA 0.213000 ;
    PORT
      LAYER met3 ;
        RECT 0.000 537.240 4.000 537.840 ;
    END
  END core_port_i[392]
  PIN core_port_i[393]
    DIRECTION INPUT ;
    USE SIGNAL ;
    ANTENNAGATEAREA 0.213000 ;
    PORT
      LAYER met3 ;
        RECT 0.000 538.600 4.000 539.200 ;
    END
  END core_port_i[393]
  PIN core_port_i[394]
    DIRECTION INPUT ;
    USE SIGNAL ;
    ANTENNAGATEAREA 0.213000 ;
    PORT
      LAYER met3 ;
        RECT 0.000 539.960 4.000 540.560 ;
    END
  END core_port_i[394]
  PIN core_port_i[395]
    DIRECTION INPUT ;
    USE SIGNAL ;
    ANTENNAGATEAREA 0.213000 ;
    PORT
      LAYER met3 ;
        RECT 0.000 541.320 4.000 541.920 ;
    END
  END core_port_i[395]
  PIN core_port_i[396]
    DIRECTION INPUT ;
    USE SIGNAL ;
    ANTENNAGATEAREA 0.213000 ;
    PORT
      LAYER met3 ;
        RECT 0.000 542.680 4.000 543.280 ;
    END
  END core_port_i[396]
  PIN core_port_i[397]
    DIRECTION INPUT ;
    USE SIGNAL ;
    ANTENNAGATEAREA 0.213000 ;
    PORT
      LAYER met3 ;
        RECT 0.000 544.040 4.000 544.640 ;
    END
  END core_port_i[397]
  PIN core_port_i[398]
    DIRECTION INPUT ;
    USE SIGNAL ;
    ANTENNAGATEAREA 0.213000 ;
    PORT
      LAYER met3 ;
        RECT 0.000 545.400 4.000 546.000 ;
    END
  END core_port_i[398]
  PIN core_port_i[399]
    DIRECTION INPUT ;
    USE SIGNAL ;
    ANTENNAGATEAREA 0.213000 ;
    PORT
      LAYER met3 ;
        RECT 0.000 546.760 4.000 547.360 ;
    END
  END core_port_i[399]
  PIN core_port_i[39]
    DIRECTION INPUT ;
    USE SIGNAL ;
    ANTENNAGATEAREA 0.247500 ;
    PORT
      LAYER met3 ;
        RECT 0.000 57.160 4.000 57.760 ;
    END
  END core_port_i[39]
  PIN core_port_i[3]
    DIRECTION INPUT ;
    USE SIGNAL ;
    ANTENNAGATEAREA 0.247500 ;
    PORT
      LAYER met3 ;
        RECT 0.000 8.200 4.000 8.800 ;
    END
  END core_port_i[3]
  PIN core_port_i[400]
    DIRECTION INPUT ;
    USE SIGNAL ;
    ANTENNAGATEAREA 0.213000 ;
    PORT
      LAYER met3 ;
        RECT 0.000 548.120 4.000 548.720 ;
    END
  END core_port_i[400]
  PIN core_port_i[401]
    DIRECTION INPUT ;
    USE SIGNAL ;
    ANTENNAGATEAREA 0.213000 ;
    PORT
      LAYER met3 ;
        RECT 0.000 549.480 4.000 550.080 ;
    END
  END core_port_i[401]
  PIN core_port_i[402]
    DIRECTION INPUT ;
    USE SIGNAL ;
    ANTENNAGATEAREA 0.213000 ;
    PORT
      LAYER met3 ;
        RECT 0.000 550.840 4.000 551.440 ;
    END
  END core_port_i[402]
  PIN core_port_i[403]
    DIRECTION INPUT ;
    USE SIGNAL ;
    ANTENNAGATEAREA 0.213000 ;
    PORT
      LAYER met3 ;
        RECT 0.000 552.200 4.000 552.800 ;
    END
  END core_port_i[403]
  PIN core_port_i[404]
    DIRECTION INPUT ;
    USE SIGNAL ;
    ANTENNAGATEAREA 0.213000 ;
    PORT
      LAYER met3 ;
        RECT 0.000 553.560 4.000 554.160 ;
    END
  END core_port_i[404]
  PIN core_port_i[405]
    DIRECTION INPUT ;
    USE SIGNAL ;
    ANTENNAGATEAREA 0.213000 ;
    PORT
      LAYER met3 ;
        RECT 0.000 554.920 4.000 555.520 ;
    END
  END core_port_i[405]
  PIN core_port_i[406]
    DIRECTION INPUT ;
    USE SIGNAL ;
    ANTENNAGATEAREA 0.213000 ;
    PORT
      LAYER met3 ;
        RECT 0.000 556.280 4.000 556.880 ;
    END
  END core_port_i[406]
  PIN core_port_i[407]
    DIRECTION INPUT ;
    USE SIGNAL ;
    ANTENNAGATEAREA 0.247500 ;
    PORT
      LAYER met3 ;
        RECT 0.000 557.640 4.000 558.240 ;
    END
  END core_port_i[407]
  PIN core_port_i[408]
    DIRECTION INPUT ;
    USE SIGNAL ;
    ANTENNAGATEAREA 0.213000 ;
    PORT
      LAYER met3 ;
        RECT 0.000 559.000 4.000 559.600 ;
    END
  END core_port_i[408]
  PIN core_port_i[409]
    DIRECTION INPUT ;
    USE SIGNAL ;
    ANTENNAGATEAREA 0.426000 ;
    PORT
      LAYER met3 ;
        RECT 0.000 560.360 4.000 560.960 ;
    END
  END core_port_i[409]
  PIN core_port_i[40]
    DIRECTION INPUT ;
    USE SIGNAL ;
    ANTENNAGATEAREA 0.247500 ;
    PORT
      LAYER met3 ;
        RECT 0.000 58.520 4.000 59.120 ;
    END
  END core_port_i[40]
  PIN core_port_i[410]
    DIRECTION INPUT ;
    USE SIGNAL ;
    ANTENNAGATEAREA 0.213000 ;
    PORT
      LAYER met3 ;
        RECT 0.000 561.720 4.000 562.320 ;
    END
  END core_port_i[410]
  PIN core_port_i[411]
    DIRECTION INPUT ;
    USE SIGNAL ;
    ANTENNAGATEAREA 0.213000 ;
    PORT
      LAYER met3 ;
        RECT 0.000 563.080 4.000 563.680 ;
    END
  END core_port_i[411]
  PIN core_port_i[412]
    DIRECTION INPUT ;
    USE SIGNAL ;
    ANTENNAGATEAREA 0.213000 ;
    PORT
      LAYER met3 ;
        RECT 0.000 564.440 4.000 565.040 ;
    END
  END core_port_i[412]
  PIN core_port_i[413]
    DIRECTION INPUT ;
    USE SIGNAL ;
    ANTENNAGATEAREA 0.213000 ;
    PORT
      LAYER met3 ;
        RECT 0.000 565.800 4.000 566.400 ;
    END
  END core_port_i[413]
  PIN core_port_i[41]
    DIRECTION INPUT ;
    USE SIGNAL ;
    ANTENNAGATEAREA 0.247500 ;
    PORT
      LAYER met3 ;
        RECT 0.000 59.880 4.000 60.480 ;
    END
  END core_port_i[41]
  PIN core_port_i[42]
    DIRECTION INPUT ;
    USE SIGNAL ;
    ANTENNAGATEAREA 0.247500 ;
    PORT
      LAYER met3 ;
        RECT 0.000 61.240 4.000 61.840 ;
    END
  END core_port_i[42]
  PIN core_port_i[43]
    DIRECTION INPUT ;
    USE SIGNAL ;
    ANTENNAGATEAREA 0.426000 ;
    PORT
      LAYER met3 ;
        RECT 0.000 62.600 4.000 63.200 ;
    END
  END core_port_i[43]
  PIN core_port_i[44]
    DIRECTION INPUT ;
    USE SIGNAL ;
    ANTENNAGATEAREA 0.247500 ;
    PORT
      LAYER met3 ;
        RECT 0.000 63.960 4.000 64.560 ;
    END
  END core_port_i[44]
  PIN core_port_i[45]
    DIRECTION INPUT ;
    USE SIGNAL ;
    ANTENNAGATEAREA 0.426000 ;
    PORT
      LAYER met3 ;
        RECT 0.000 65.320 4.000 65.920 ;
    END
  END core_port_i[45]
  PIN core_port_i[46]
    DIRECTION INPUT ;
    USE SIGNAL ;
    ANTENNAGATEAREA 0.247500 ;
    PORT
      LAYER met3 ;
        RECT 0.000 66.680 4.000 67.280 ;
    END
  END core_port_i[46]
  PIN core_port_i[47]
    DIRECTION INPUT ;
    USE SIGNAL ;
    ANTENNAGATEAREA 0.247500 ;
    PORT
      LAYER met3 ;
        RECT 0.000 68.040 4.000 68.640 ;
    END
  END core_port_i[47]
  PIN core_port_i[48]
    DIRECTION INPUT ;
    USE SIGNAL ;
    ANTENNAGATEAREA 0.247500 ;
    PORT
      LAYER met3 ;
        RECT 0.000 69.400 4.000 70.000 ;
    END
  END core_port_i[48]
  PIN core_port_i[49]
    DIRECTION INPUT ;
    USE SIGNAL ;
    ANTENNAGATEAREA 0.247500 ;
    PORT
      LAYER met3 ;
        RECT 0.000 70.760 4.000 71.360 ;
    END
  END core_port_i[49]
  PIN core_port_i[4]
    DIRECTION INPUT ;
    USE SIGNAL ;
    ANTENNAGATEAREA 0.247500 ;
    PORT
      LAYER met3 ;
        RECT 0.000 9.560 4.000 10.160 ;
    END
  END core_port_i[4]
  PIN core_port_i[50]
    DIRECTION INPUT ;
    USE SIGNAL ;
    ANTENNAGATEAREA 0.247500 ;
    PORT
      LAYER met3 ;
        RECT 0.000 72.120 4.000 72.720 ;
    END
  END core_port_i[50]
  PIN core_port_i[51]
    DIRECTION INPUT ;
    USE SIGNAL ;
    ANTENNAGATEAREA 0.426000 ;
    PORT
      LAYER met3 ;
        RECT 0.000 73.480 4.000 74.080 ;
    END
  END core_port_i[51]
  PIN core_port_i[52]
    DIRECTION INPUT ;
    USE SIGNAL ;
    ANTENNAGATEAREA 0.247500 ;
    PORT
      LAYER met3 ;
        RECT 0.000 74.840 4.000 75.440 ;
    END
  END core_port_i[52]
  PIN core_port_i[53]
    DIRECTION INPUT ;
    USE SIGNAL ;
    ANTENNAGATEAREA 0.426000 ;
    PORT
      LAYER met3 ;
        RECT 0.000 76.200 4.000 76.800 ;
    END
  END core_port_i[53]
  PIN core_port_i[54]
    DIRECTION INPUT ;
    USE SIGNAL ;
    ANTENNAGATEAREA 0.247500 ;
    PORT
      LAYER met3 ;
        RECT 0.000 77.560 4.000 78.160 ;
    END
  END core_port_i[54]
  PIN core_port_i[55]
    DIRECTION INPUT ;
    USE SIGNAL ;
    ANTENNAGATEAREA 0.247500 ;
    PORT
      LAYER met3 ;
        RECT 0.000 78.920 4.000 79.520 ;
    END
  END core_port_i[55]
  PIN core_port_i[56]
    DIRECTION INPUT ;
    USE SIGNAL ;
    ANTENNAGATEAREA 0.247500 ;
    PORT
      LAYER met3 ;
        RECT 0.000 80.280 4.000 80.880 ;
    END
  END core_port_i[56]
  PIN core_port_i[57]
    DIRECTION INPUT ;
    USE SIGNAL ;
    ANTENNAGATEAREA 0.426000 ;
    PORT
      LAYER met3 ;
        RECT 0.000 81.640 4.000 82.240 ;
    END
  END core_port_i[57]
  PIN core_port_i[58]
    DIRECTION INPUT ;
    USE SIGNAL ;
    ANTENNAGATEAREA 0.426000 ;
    PORT
      LAYER met3 ;
        RECT 0.000 83.000 4.000 83.600 ;
    END
  END core_port_i[58]
  PIN core_port_i[59]
    DIRECTION INPUT ;
    USE SIGNAL ;
    ANTENNAGATEAREA 0.426000 ;
    PORT
      LAYER met3 ;
        RECT 0.000 84.360 4.000 84.960 ;
    END
  END core_port_i[59]
  PIN core_port_i[5]
    DIRECTION INPUT ;
    USE SIGNAL ;
    ANTENNAGATEAREA 0.247500 ;
    PORT
      LAYER met3 ;
        RECT 0.000 10.920 4.000 11.520 ;
    END
  END core_port_i[5]
  PIN core_port_i[60]
    DIRECTION INPUT ;
    USE SIGNAL ;
    ANTENNAGATEAREA 0.426000 ;
    PORT
      LAYER met3 ;
        RECT 0.000 85.720 4.000 86.320 ;
    END
  END core_port_i[60]
  PIN core_port_i[61]
    DIRECTION INPUT ;
    USE SIGNAL ;
    ANTENNAGATEAREA 0.247500 ;
    PORT
      LAYER met3 ;
        RECT 0.000 87.080 4.000 87.680 ;
    END
  END core_port_i[61]
  PIN core_port_i[62]
    DIRECTION INPUT ;
    USE SIGNAL ;
    ANTENNAGATEAREA 0.426000 ;
    PORT
      LAYER met3 ;
        RECT 0.000 88.440 4.000 89.040 ;
    END
  END core_port_i[62]
  PIN core_port_i[63]
    DIRECTION INPUT ;
    USE SIGNAL ;
    ANTENNAGATEAREA 0.426000 ;
    PORT
      LAYER met3 ;
        RECT 0.000 89.800 4.000 90.400 ;
    END
  END core_port_i[63]
  PIN core_port_i[64]
    DIRECTION INPUT ;
    USE SIGNAL ;
    ANTENNAGATEAREA 0.495000 ;
    PORT
      LAYER met3 ;
        RECT 0.000 91.160 4.000 91.760 ;
    END
  END core_port_i[64]
  PIN core_port_i[65]
    DIRECTION INPUT ;
    USE SIGNAL ;
    ANTENNAGATEAREA 0.247500 ;
    PORT
      LAYER met3 ;
        RECT 0.000 92.520 4.000 93.120 ;
    END
  END core_port_i[65]
  PIN core_port_i[66]
    DIRECTION INPUT ;
    USE SIGNAL ;
    ANTENNAGATEAREA 0.247500 ;
    PORT
      LAYER met3 ;
        RECT 0.000 93.880 4.000 94.480 ;
    END
  END core_port_i[66]
  PIN core_port_i[67]
    DIRECTION INPUT ;
    USE SIGNAL ;
    ANTENNAGATEAREA 0.247500 ;
    PORT
      LAYER met3 ;
        RECT 0.000 95.240 4.000 95.840 ;
    END
  END core_port_i[67]
  PIN core_port_i[68]
    DIRECTION INPUT ;
    USE SIGNAL ;
    ANTENNAGATEAREA 0.247500 ;
    PORT
      LAYER met3 ;
        RECT 0.000 96.600 4.000 97.200 ;
    END
  END core_port_i[68]
  PIN core_port_i[69]
    DIRECTION INPUT ;
    USE SIGNAL ;
    ANTENNAGATEAREA 0.247500 ;
    PORT
      LAYER met3 ;
        RECT 0.000 97.960 4.000 98.560 ;
    END
  END core_port_i[69]
  PIN core_port_i[6]
    DIRECTION INPUT ;
    USE SIGNAL ;
    ANTENNAGATEAREA 0.247500 ;
    PORT
      LAYER met3 ;
        RECT 0.000 12.280 4.000 12.880 ;
    END
  END core_port_i[6]
  PIN core_port_i[70]
    DIRECTION INPUT ;
    USE SIGNAL ;
    ANTENNAGATEAREA 0.247500 ;
    PORT
      LAYER met3 ;
        RECT 0.000 99.320 4.000 99.920 ;
    END
  END core_port_i[70]
  PIN core_port_i[71]
    DIRECTION INPUT ;
    USE SIGNAL ;
    ANTENNAGATEAREA 0.247500 ;
    PORT
      LAYER met3 ;
        RECT 0.000 100.680 4.000 101.280 ;
    END
  END core_port_i[71]
  PIN core_port_i[72]
    DIRECTION INPUT ;
    USE SIGNAL ;
    ANTENNAGATEAREA 0.247500 ;
    PORT
      LAYER met3 ;
        RECT 0.000 102.040 4.000 102.640 ;
    END
  END core_port_i[72]
  PIN core_port_i[73]
    DIRECTION INPUT ;
    USE SIGNAL ;
    ANTENNAGATEAREA 0.247500 ;
    PORT
      LAYER met3 ;
        RECT 0.000 103.400 4.000 104.000 ;
    END
  END core_port_i[73]
  PIN core_port_i[74]
    DIRECTION INPUT ;
    USE SIGNAL ;
    ANTENNAGATEAREA 0.247500 ;
    PORT
      LAYER met3 ;
        RECT 0.000 104.760 4.000 105.360 ;
    END
  END core_port_i[74]
  PIN core_port_i[75]
    DIRECTION INPUT ;
    USE SIGNAL ;
    ANTENNAGATEAREA 0.247500 ;
    PORT
      LAYER met3 ;
        RECT 0.000 106.120 4.000 106.720 ;
    END
  END core_port_i[75]
  PIN core_port_i[76]
    DIRECTION INPUT ;
    USE SIGNAL ;
    ANTENNAGATEAREA 0.247500 ;
    PORT
      LAYER met3 ;
        RECT 0.000 107.480 4.000 108.080 ;
    END
  END core_port_i[76]
  PIN core_port_i[77]
    DIRECTION INPUT ;
    USE SIGNAL ;
    ANTENNAGATEAREA 0.247500 ;
    PORT
      LAYER met3 ;
        RECT 0.000 108.840 4.000 109.440 ;
    END
  END core_port_i[77]
  PIN core_port_i[78]
    DIRECTION INPUT ;
    USE SIGNAL ;
    ANTENNAGATEAREA 0.247500 ;
    PORT
      LAYER met3 ;
        RECT 0.000 110.200 4.000 110.800 ;
    END
  END core_port_i[78]
  PIN core_port_i[79]
    DIRECTION INPUT ;
    USE SIGNAL ;
    ANTENNAGATEAREA 0.247500 ;
    PORT
      LAYER met3 ;
        RECT 0.000 111.560 4.000 112.160 ;
    END
  END core_port_i[79]
  PIN core_port_i[7]
    DIRECTION INPUT ;
    USE SIGNAL ;
    ANTENNAGATEAREA 0.247500 ;
    PORT
      LAYER met3 ;
        RECT 0.000 13.640 4.000 14.240 ;
    END
  END core_port_i[7]
  PIN core_port_i[80]
    DIRECTION INPUT ;
    USE SIGNAL ;
    ANTENNAGATEAREA 0.247500 ;
    PORT
      LAYER met3 ;
        RECT 0.000 112.920 4.000 113.520 ;
    END
  END core_port_i[80]
  PIN core_port_i[81]
    DIRECTION INPUT ;
    USE SIGNAL ;
    ANTENNAGATEAREA 0.247500 ;
    PORT
      LAYER met3 ;
        RECT 0.000 114.280 4.000 114.880 ;
    END
  END core_port_i[81]
  PIN core_port_i[82]
    DIRECTION INPUT ;
    USE SIGNAL ;
    ANTENNAGATEAREA 0.247500 ;
    PORT
      LAYER met3 ;
        RECT 0.000 115.640 4.000 116.240 ;
    END
  END core_port_i[82]
  PIN core_port_i[83]
    DIRECTION INPUT ;
    USE SIGNAL ;
    ANTENNAGATEAREA 0.247500 ;
    PORT
      LAYER met3 ;
        RECT 0.000 117.000 4.000 117.600 ;
    END
  END core_port_i[83]
  PIN core_port_i[84]
    DIRECTION INPUT ;
    USE SIGNAL ;
    ANTENNAGATEAREA 0.247500 ;
    PORT
      LAYER met3 ;
        RECT 0.000 118.360 4.000 118.960 ;
    END
  END core_port_i[84]
  PIN core_port_i[85]
    DIRECTION INPUT ;
    USE SIGNAL ;
    ANTENNAGATEAREA 0.247500 ;
    PORT
      LAYER met3 ;
        RECT 0.000 119.720 4.000 120.320 ;
    END
  END core_port_i[85]
  PIN core_port_i[86]
    DIRECTION INPUT ;
    USE SIGNAL ;
    ANTENNAGATEAREA 0.247500 ;
    PORT
      LAYER met3 ;
        RECT 0.000 121.080 4.000 121.680 ;
    END
  END core_port_i[86]
  PIN core_port_i[87]
    DIRECTION INPUT ;
    USE SIGNAL ;
    ANTENNAGATEAREA 0.247500 ;
    PORT
      LAYER met3 ;
        RECT 0.000 122.440 4.000 123.040 ;
    END
  END core_port_i[87]
  PIN core_port_i[88]
    DIRECTION INPUT ;
    USE SIGNAL ;
    ANTENNAGATEAREA 0.247500 ;
    PORT
      LAYER met3 ;
        RECT 0.000 123.800 4.000 124.400 ;
    END
  END core_port_i[88]
  PIN core_port_i[89]
    DIRECTION INPUT ;
    USE SIGNAL ;
    ANTENNAGATEAREA 0.247500 ;
    PORT
      LAYER met3 ;
        RECT 0.000 125.160 4.000 125.760 ;
    END
  END core_port_i[89]
  PIN core_port_i[8]
    DIRECTION INPUT ;
    USE SIGNAL ;
    ANTENNAGATEAREA 0.247500 ;
    PORT
      LAYER met3 ;
        RECT 0.000 15.000 4.000 15.600 ;
    END
  END core_port_i[8]
  PIN core_port_i[90]
    DIRECTION INPUT ;
    USE SIGNAL ;
    ANTENNAGATEAREA 0.247500 ;
    PORT
      LAYER met3 ;
        RECT 0.000 126.520 4.000 127.120 ;
    END
  END core_port_i[90]
  PIN core_port_i[91]
    DIRECTION INPUT ;
    USE SIGNAL ;
    ANTENNAGATEAREA 0.247500 ;
    PORT
      LAYER met3 ;
        RECT 0.000 127.880 4.000 128.480 ;
    END
  END core_port_i[91]
  PIN core_port_i[92]
    DIRECTION INPUT ;
    USE SIGNAL ;
    ANTENNAGATEAREA 0.247500 ;
    PORT
      LAYER met3 ;
        RECT 0.000 129.240 4.000 129.840 ;
    END
  END core_port_i[92]
  PIN core_port_i[93]
    DIRECTION INPUT ;
    USE SIGNAL ;
    ANTENNAGATEAREA 0.247500 ;
    PORT
      LAYER met3 ;
        RECT 0.000 130.600 4.000 131.200 ;
    END
  END core_port_i[93]
  PIN core_port_i[94]
    DIRECTION INPUT ;
    USE SIGNAL ;
    ANTENNAGATEAREA 0.247500 ;
    PORT
      LAYER met3 ;
        RECT 0.000 131.960 4.000 132.560 ;
    END
  END core_port_i[94]
  PIN core_port_i[95]
    DIRECTION INPUT ;
    USE SIGNAL ;
    ANTENNAGATEAREA 0.247500 ;
    PORT
      LAYER met3 ;
        RECT 0.000 133.320 4.000 133.920 ;
    END
  END core_port_i[95]
  PIN core_port_i[96]
    DIRECTION INPUT ;
    USE SIGNAL ;
    ANTENNAGATEAREA 0.247500 ;
    PORT
      LAYER met3 ;
        RECT 0.000 134.680 4.000 135.280 ;
    END
  END core_port_i[96]
  PIN core_port_i[97]
    DIRECTION INPUT ;
    USE SIGNAL ;
    ANTENNAGATEAREA 0.247500 ;
    PORT
      LAYER met3 ;
        RECT 0.000 136.040 4.000 136.640 ;
    END
  END core_port_i[97]
  PIN core_port_i[98]
    DIRECTION INPUT ;
    USE SIGNAL ;
    ANTENNAGATEAREA 0.247500 ;
    PORT
      LAYER met3 ;
        RECT 0.000 137.400 4.000 138.000 ;
    END
  END core_port_i[98]
  PIN core_port_i[99]
    DIRECTION INPUT ;
    USE SIGNAL ;
    ANTENNAGATEAREA 0.247500 ;
    PORT
      LAYER met3 ;
        RECT 0.000 138.760 4.000 139.360 ;
    END
  END core_port_i[99]
  PIN core_port_i[9]
    DIRECTION INPUT ;
    USE SIGNAL ;
    ANTENNAGATEAREA 0.247500 ;
    PORT
      LAYER met3 ;
        RECT 0.000 16.360 4.000 16.960 ;
    END
  END core_port_i[9]
  PIN core_port_o[0]
    DIRECTION OUTPUT TRISTATE ;
    USE SIGNAL ;
    ANTENNADIFFAREA 2.673000 ;
    PORT
      LAYER met3 ;
        RECT 0.000 567.160 4.000 567.760 ;
    END
  END core_port_o[0]
  PIN core_port_o[100]
    DIRECTION OUTPUT TRISTATE ;
    USE SIGNAL ;
    ANTENNADIFFAREA 2.673000 ;
    PORT
      LAYER met3 ;
        RECT 0.000 703.160 4.000 703.760 ;
    END
  END core_port_o[100]
  PIN core_port_o[101]
    DIRECTION OUTPUT TRISTATE ;
    USE SIGNAL ;
    ANTENNADIFFAREA 2.673000 ;
    PORT
      LAYER met3 ;
        RECT 0.000 704.520 4.000 705.120 ;
    END
  END core_port_o[101]
  PIN core_port_o[102]
    DIRECTION OUTPUT TRISTATE ;
    USE SIGNAL ;
    ANTENNADIFFAREA 2.673000 ;
    PORT
      LAYER met3 ;
        RECT 0.000 705.880 4.000 706.480 ;
    END
  END core_port_o[102]
  PIN core_port_o[103]
    DIRECTION OUTPUT TRISTATE ;
    USE SIGNAL ;
    ANTENNADIFFAREA 2.673000 ;
    PORT
      LAYER met3 ;
        RECT 0.000 707.240 4.000 707.840 ;
    END
  END core_port_o[103]
  PIN core_port_o[104]
    DIRECTION OUTPUT TRISTATE ;
    USE SIGNAL ;
    ANTENNADIFFAREA 2.673000 ;
    PORT
      LAYER met3 ;
        RECT 0.000 708.600 4.000 709.200 ;
    END
  END core_port_o[104]
  PIN core_port_o[105]
    DIRECTION OUTPUT TRISTATE ;
    USE SIGNAL ;
    ANTENNADIFFAREA 2.673000 ;
    PORT
      LAYER met3 ;
        RECT 0.000 709.960 4.000 710.560 ;
    END
  END core_port_o[105]
  PIN core_port_o[106]
    DIRECTION OUTPUT TRISTATE ;
    USE SIGNAL ;
    ANTENNADIFFAREA 2.673000 ;
    PORT
      LAYER met3 ;
        RECT 0.000 711.320 4.000 711.920 ;
    END
  END core_port_o[106]
  PIN core_port_o[107]
    DIRECTION OUTPUT TRISTATE ;
    USE SIGNAL ;
    ANTENNADIFFAREA 2.673000 ;
    PORT
      LAYER met3 ;
        RECT 0.000 712.680 4.000 713.280 ;
    END
  END core_port_o[107]
  PIN core_port_o[108]
    DIRECTION OUTPUT TRISTATE ;
    USE SIGNAL ;
    ANTENNADIFFAREA 2.673000 ;
    PORT
      LAYER met3 ;
        RECT 0.000 714.040 4.000 714.640 ;
    END
  END core_port_o[108]
  PIN core_port_o[109]
    DIRECTION OUTPUT TRISTATE ;
    USE SIGNAL ;
    ANTENNADIFFAREA 2.673000 ;
    PORT
      LAYER met3 ;
        RECT 0.000 715.400 4.000 716.000 ;
    END
  END core_port_o[109]
  PIN core_port_o[10]
    DIRECTION OUTPUT TRISTATE ;
    USE SIGNAL ;
    ANTENNADIFFAREA 2.673000 ;
    PORT
      LAYER met3 ;
        RECT 0.000 580.760 4.000 581.360 ;
    END
  END core_port_o[10]
  PIN core_port_o[110]
    DIRECTION OUTPUT TRISTATE ;
    USE SIGNAL ;
    ANTENNADIFFAREA 2.673000 ;
    PORT
      LAYER met3 ;
        RECT 0.000 716.760 4.000 717.360 ;
    END
  END core_port_o[110]
  PIN core_port_o[111]
    DIRECTION OUTPUT TRISTATE ;
    USE SIGNAL ;
    ANTENNADIFFAREA 2.673000 ;
    PORT
      LAYER met3 ;
        RECT 0.000 718.120 4.000 718.720 ;
    END
  END core_port_o[111]
  PIN core_port_o[112]
    DIRECTION OUTPUT TRISTATE ;
    USE SIGNAL ;
    ANTENNADIFFAREA 2.673000 ;
    PORT
      LAYER met3 ;
        RECT 0.000 719.480 4.000 720.080 ;
    END
  END core_port_o[112]
  PIN core_port_o[113]
    DIRECTION OUTPUT TRISTATE ;
    USE SIGNAL ;
    ANTENNADIFFAREA 2.673000 ;
    PORT
      LAYER met3 ;
        RECT 0.000 720.840 4.000 721.440 ;
    END
  END core_port_o[113]
  PIN core_port_o[114]
    DIRECTION OUTPUT TRISTATE ;
    USE SIGNAL ;
    ANTENNADIFFAREA 2.673000 ;
    PORT
      LAYER met3 ;
        RECT 0.000 722.200 4.000 722.800 ;
    END
  END core_port_o[114]
  PIN core_port_o[115]
    DIRECTION OUTPUT TRISTATE ;
    USE SIGNAL ;
    ANTENNADIFFAREA 2.673000 ;
    PORT
      LAYER met3 ;
        RECT 0.000 723.560 4.000 724.160 ;
    END
  END core_port_o[115]
  PIN core_port_o[116]
    DIRECTION OUTPUT TRISTATE ;
    USE SIGNAL ;
    ANTENNADIFFAREA 2.673000 ;
    PORT
      LAYER met3 ;
        RECT 0.000 724.920 4.000 725.520 ;
    END
  END core_port_o[116]
  PIN core_port_o[117]
    DIRECTION OUTPUT TRISTATE ;
    USE SIGNAL ;
    ANTENNADIFFAREA 2.673000 ;
    PORT
      LAYER met3 ;
        RECT 0.000 726.280 4.000 726.880 ;
    END
  END core_port_o[117]
  PIN core_port_o[118]
    DIRECTION OUTPUT TRISTATE ;
    USE SIGNAL ;
    ANTENNADIFFAREA 2.673000 ;
    PORT
      LAYER met3 ;
        RECT 0.000 727.640 4.000 728.240 ;
    END
  END core_port_o[118]
  PIN core_port_o[119]
    DIRECTION OUTPUT TRISTATE ;
    USE SIGNAL ;
    ANTENNADIFFAREA 2.673000 ;
    PORT
      LAYER met3 ;
        RECT 0.000 729.000 4.000 729.600 ;
    END
  END core_port_o[119]
  PIN core_port_o[11]
    DIRECTION OUTPUT TRISTATE ;
    USE SIGNAL ;
    ANTENNADIFFAREA 2.673000 ;
    PORT
      LAYER met3 ;
        RECT 0.000 582.120 4.000 582.720 ;
    END
  END core_port_o[11]
  PIN core_port_o[120]
    DIRECTION OUTPUT TRISTATE ;
    USE SIGNAL ;
    ANTENNADIFFAREA 2.673000 ;
    PORT
      LAYER met3 ;
        RECT 0.000 730.360 4.000 730.960 ;
    END
  END core_port_o[120]
  PIN core_port_o[121]
    DIRECTION OUTPUT TRISTATE ;
    USE SIGNAL ;
    ANTENNADIFFAREA 2.673000 ;
    PORT
      LAYER met3 ;
        RECT 0.000 731.720 4.000 732.320 ;
    END
  END core_port_o[121]
  PIN core_port_o[122]
    DIRECTION OUTPUT TRISTATE ;
    USE SIGNAL ;
    ANTENNADIFFAREA 2.673000 ;
    PORT
      LAYER met3 ;
        RECT 0.000 733.080 4.000 733.680 ;
    END
  END core_port_o[122]
  PIN core_port_o[123]
    DIRECTION OUTPUT TRISTATE ;
    USE SIGNAL ;
    ANTENNADIFFAREA 2.673000 ;
    PORT
      LAYER met3 ;
        RECT 0.000 734.440 4.000 735.040 ;
    END
  END core_port_o[123]
  PIN core_port_o[124]
    DIRECTION OUTPUT TRISTATE ;
    USE SIGNAL ;
    ANTENNADIFFAREA 2.673000 ;
    PORT
      LAYER met3 ;
        RECT 0.000 735.800 4.000 736.400 ;
    END
  END core_port_o[124]
  PIN core_port_o[125]
    DIRECTION OUTPUT TRISTATE ;
    USE SIGNAL ;
    ANTENNADIFFAREA 2.673000 ;
    PORT
      LAYER met3 ;
        RECT 0.000 737.160 4.000 737.760 ;
    END
  END core_port_o[125]
  PIN core_port_o[126]
    DIRECTION OUTPUT TRISTATE ;
    USE SIGNAL ;
    ANTENNADIFFAREA 2.673000 ;
    PORT
      LAYER met3 ;
        RECT 0.000 738.520 4.000 739.120 ;
    END
  END core_port_o[126]
  PIN core_port_o[127]
    DIRECTION OUTPUT TRISTATE ;
    USE SIGNAL ;
    ANTENNADIFFAREA 2.673000 ;
    PORT
      LAYER met3 ;
        RECT 0.000 739.880 4.000 740.480 ;
    END
  END core_port_o[127]
  PIN core_port_o[128]
    DIRECTION OUTPUT TRISTATE ;
    USE SIGNAL ;
    ANTENNADIFFAREA 2.673000 ;
    PORT
      LAYER met3 ;
        RECT 0.000 741.240 4.000 741.840 ;
    END
  END core_port_o[128]
  PIN core_port_o[129]
    DIRECTION OUTPUT TRISTATE ;
    USE SIGNAL ;
    ANTENNADIFFAREA 2.673000 ;
    PORT
      LAYER met3 ;
        RECT 0.000 742.600 4.000 743.200 ;
    END
  END core_port_o[129]
  PIN core_port_o[12]
    DIRECTION OUTPUT TRISTATE ;
    USE SIGNAL ;
    ANTENNADIFFAREA 2.673000 ;
    PORT
      LAYER met3 ;
        RECT 0.000 583.480 4.000 584.080 ;
    END
  END core_port_o[12]
  PIN core_port_o[130]
    DIRECTION OUTPUT TRISTATE ;
    USE SIGNAL ;
    ANTENNADIFFAREA 2.673000 ;
    PORT
      LAYER met3 ;
        RECT 0.000 743.960 4.000 744.560 ;
    END
  END core_port_o[130]
  PIN core_port_o[131]
    DIRECTION OUTPUT TRISTATE ;
    USE SIGNAL ;
    ANTENNADIFFAREA 2.673000 ;
    PORT
      LAYER met3 ;
        RECT 0.000 745.320 4.000 745.920 ;
    END
  END core_port_o[131]
  PIN core_port_o[132]
    DIRECTION OUTPUT TRISTATE ;
    USE SIGNAL ;
    ANTENNADIFFAREA 2.673000 ;
    PORT
      LAYER met3 ;
        RECT 0.000 746.680 4.000 747.280 ;
    END
  END core_port_o[132]
  PIN core_port_o[133]
    DIRECTION OUTPUT TRISTATE ;
    USE SIGNAL ;
    ANTENNADIFFAREA 2.673000 ;
    PORT
      LAYER met3 ;
        RECT 0.000 748.040 4.000 748.640 ;
    END
  END core_port_o[133]
  PIN core_port_o[134]
    DIRECTION OUTPUT TRISTATE ;
    USE SIGNAL ;
    ANTENNADIFFAREA 2.673000 ;
    PORT
      LAYER met3 ;
        RECT 0.000 749.400 4.000 750.000 ;
    END
  END core_port_o[134]
  PIN core_port_o[135]
    DIRECTION OUTPUT TRISTATE ;
    USE SIGNAL ;
    ANTENNADIFFAREA 2.673000 ;
    PORT
      LAYER met3 ;
        RECT 0.000 750.760 4.000 751.360 ;
    END
  END core_port_o[135]
  PIN core_port_o[136]
    DIRECTION OUTPUT TRISTATE ;
    USE SIGNAL ;
    ANTENNADIFFAREA 2.673000 ;
    PORT
      LAYER met3 ;
        RECT 0.000 752.120 4.000 752.720 ;
    END
  END core_port_o[136]
  PIN core_port_o[137]
    DIRECTION OUTPUT TRISTATE ;
    USE SIGNAL ;
    ANTENNADIFFAREA 2.673000 ;
    PORT
      LAYER met3 ;
        RECT 0.000 753.480 4.000 754.080 ;
    END
  END core_port_o[137]
  PIN core_port_o[138]
    DIRECTION OUTPUT TRISTATE ;
    USE SIGNAL ;
    ANTENNADIFFAREA 2.673000 ;
    PORT
      LAYER met3 ;
        RECT 0.000 754.840 4.000 755.440 ;
    END
  END core_port_o[138]
  PIN core_port_o[139]
    DIRECTION OUTPUT TRISTATE ;
    USE SIGNAL ;
    ANTENNADIFFAREA 2.673000 ;
    PORT
      LAYER met3 ;
        RECT 0.000 756.200 4.000 756.800 ;
    END
  END core_port_o[139]
  PIN core_port_o[13]
    DIRECTION OUTPUT TRISTATE ;
    USE SIGNAL ;
    ANTENNADIFFAREA 2.673000 ;
    PORT
      LAYER met3 ;
        RECT 0.000 584.840 4.000 585.440 ;
    END
  END core_port_o[13]
  PIN core_port_o[140]
    DIRECTION OUTPUT TRISTATE ;
    USE SIGNAL ;
    ANTENNADIFFAREA 2.673000 ;
    PORT
      LAYER met3 ;
        RECT 0.000 757.560 4.000 758.160 ;
    END
  END core_port_o[140]
  PIN core_port_o[141]
    DIRECTION OUTPUT TRISTATE ;
    USE SIGNAL ;
    ANTENNADIFFAREA 2.673000 ;
    PORT
      LAYER met3 ;
        RECT 0.000 758.920 4.000 759.520 ;
    END
  END core_port_o[141]
  PIN core_port_o[142]
    DIRECTION OUTPUT TRISTATE ;
    USE SIGNAL ;
    ANTENNADIFFAREA 2.673000 ;
    PORT
      LAYER met3 ;
        RECT 0.000 760.280 4.000 760.880 ;
    END
  END core_port_o[142]
  PIN core_port_o[143]
    DIRECTION OUTPUT TRISTATE ;
    USE SIGNAL ;
    ANTENNADIFFAREA 2.673000 ;
    PORT
      LAYER met3 ;
        RECT 0.000 761.640 4.000 762.240 ;
    END
  END core_port_o[143]
  PIN core_port_o[144]
    DIRECTION OUTPUT TRISTATE ;
    USE SIGNAL ;
    ANTENNADIFFAREA 2.673000 ;
    PORT
      LAYER met3 ;
        RECT 0.000 763.000 4.000 763.600 ;
    END
  END core_port_o[144]
  PIN core_port_o[145]
    DIRECTION OUTPUT TRISTATE ;
    USE SIGNAL ;
    ANTENNADIFFAREA 2.673000 ;
    PORT
      LAYER met3 ;
        RECT 0.000 764.360 4.000 764.960 ;
    END
  END core_port_o[145]
  PIN core_port_o[146]
    DIRECTION OUTPUT TRISTATE ;
    USE SIGNAL ;
    ANTENNADIFFAREA 2.673000 ;
    PORT
      LAYER met3 ;
        RECT 0.000 765.720 4.000 766.320 ;
    END
  END core_port_o[146]
  PIN core_port_o[147]
    DIRECTION OUTPUT TRISTATE ;
    USE SIGNAL ;
    ANTENNADIFFAREA 2.673000 ;
    PORT
      LAYER met3 ;
        RECT 0.000 767.080 4.000 767.680 ;
    END
  END core_port_o[147]
  PIN core_port_o[148]
    DIRECTION OUTPUT TRISTATE ;
    USE SIGNAL ;
    ANTENNADIFFAREA 2.673000 ;
    PORT
      LAYER met3 ;
        RECT 0.000 768.440 4.000 769.040 ;
    END
  END core_port_o[148]
  PIN core_port_o[149]
    DIRECTION OUTPUT TRISTATE ;
    USE SIGNAL ;
    ANTENNADIFFAREA 2.673000 ;
    PORT
      LAYER met3 ;
        RECT 0.000 769.800 4.000 770.400 ;
    END
  END core_port_o[149]
  PIN core_port_o[14]
    DIRECTION OUTPUT TRISTATE ;
    USE SIGNAL ;
    ANTENNADIFFAREA 2.673000 ;
    PORT
      LAYER met3 ;
        RECT 0.000 586.200 4.000 586.800 ;
    END
  END core_port_o[14]
  PIN core_port_o[150]
    DIRECTION OUTPUT TRISTATE ;
    USE SIGNAL ;
    ANTENNADIFFAREA 2.673000 ;
    PORT
      LAYER met3 ;
        RECT 0.000 771.160 4.000 771.760 ;
    END
  END core_port_o[150]
  PIN core_port_o[151]
    DIRECTION OUTPUT TRISTATE ;
    USE SIGNAL ;
    ANTENNADIFFAREA 2.673000 ;
    PORT
      LAYER met3 ;
        RECT 0.000 772.520 4.000 773.120 ;
    END
  END core_port_o[151]
  PIN core_port_o[152]
    DIRECTION OUTPUT TRISTATE ;
    USE SIGNAL ;
    ANTENNADIFFAREA 2.673000 ;
    PORT
      LAYER met3 ;
        RECT 0.000 773.880 4.000 774.480 ;
    END
  END core_port_o[152]
  PIN core_port_o[153]
    DIRECTION OUTPUT TRISTATE ;
    USE SIGNAL ;
    ANTENNADIFFAREA 2.673000 ;
    PORT
      LAYER met3 ;
        RECT 0.000 775.240 4.000 775.840 ;
    END
  END core_port_o[153]
  PIN core_port_o[154]
    DIRECTION OUTPUT TRISTATE ;
    USE SIGNAL ;
    ANTENNADIFFAREA 2.673000 ;
    PORT
      LAYER met3 ;
        RECT 0.000 776.600 4.000 777.200 ;
    END
  END core_port_o[154]
  PIN core_port_o[155]
    DIRECTION OUTPUT TRISTATE ;
    USE SIGNAL ;
    ANTENNADIFFAREA 2.673000 ;
    PORT
      LAYER met3 ;
        RECT 0.000 777.960 4.000 778.560 ;
    END
  END core_port_o[155]
  PIN core_port_o[156]
    DIRECTION OUTPUT TRISTATE ;
    USE SIGNAL ;
    ANTENNADIFFAREA 2.673000 ;
    PORT
      LAYER met3 ;
        RECT 0.000 779.320 4.000 779.920 ;
    END
  END core_port_o[156]
  PIN core_port_o[157]
    DIRECTION OUTPUT TRISTATE ;
    USE SIGNAL ;
    ANTENNADIFFAREA 2.673000 ;
    PORT
      LAYER met3 ;
        RECT 0.000 780.680 4.000 781.280 ;
    END
  END core_port_o[157]
  PIN core_port_o[158]
    DIRECTION OUTPUT TRISTATE ;
    USE SIGNAL ;
    ANTENNADIFFAREA 2.673000 ;
    PORT
      LAYER met3 ;
        RECT 0.000 782.040 4.000 782.640 ;
    END
  END core_port_o[158]
  PIN core_port_o[159]
    DIRECTION OUTPUT TRISTATE ;
    USE SIGNAL ;
    ANTENNADIFFAREA 2.673000 ;
    PORT
      LAYER met3 ;
        RECT 0.000 783.400 4.000 784.000 ;
    END
  END core_port_o[159]
  PIN core_port_o[15]
    DIRECTION OUTPUT TRISTATE ;
    USE SIGNAL ;
    ANTENNADIFFAREA 2.673000 ;
    PORT
      LAYER met3 ;
        RECT 0.000 587.560 4.000 588.160 ;
    END
  END core_port_o[15]
  PIN core_port_o[160]
    DIRECTION OUTPUT TRISTATE ;
    USE SIGNAL ;
    ANTENNADIFFAREA 2.673000 ;
    PORT
      LAYER met3 ;
        RECT 0.000 784.760 4.000 785.360 ;
    END
  END core_port_o[160]
  PIN core_port_o[161]
    DIRECTION OUTPUT TRISTATE ;
    USE SIGNAL ;
    ANTENNADIFFAREA 2.673000 ;
    PORT
      LAYER met3 ;
        RECT 0.000 786.120 4.000 786.720 ;
    END
  END core_port_o[161]
  PIN core_port_o[162]
    DIRECTION OUTPUT TRISTATE ;
    USE SIGNAL ;
    ANTENNADIFFAREA 2.673000 ;
    PORT
      LAYER met3 ;
        RECT 0.000 787.480 4.000 788.080 ;
    END
  END core_port_o[162]
  PIN core_port_o[163]
    DIRECTION OUTPUT TRISTATE ;
    USE SIGNAL ;
    ANTENNADIFFAREA 2.673000 ;
    PORT
      LAYER met3 ;
        RECT 0.000 788.840 4.000 789.440 ;
    END
  END core_port_o[163]
  PIN core_port_o[164]
    DIRECTION OUTPUT TRISTATE ;
    USE SIGNAL ;
    ANTENNADIFFAREA 2.673000 ;
    PORT
      LAYER met3 ;
        RECT 0.000 790.200 4.000 790.800 ;
    END
  END core_port_o[164]
  PIN core_port_o[165]
    DIRECTION OUTPUT TRISTATE ;
    USE SIGNAL ;
    ANTENNADIFFAREA 2.673000 ;
    PORT
      LAYER met3 ;
        RECT 0.000 791.560 4.000 792.160 ;
    END
  END core_port_o[165]
  PIN core_port_o[166]
    DIRECTION OUTPUT TRISTATE ;
    USE SIGNAL ;
    ANTENNADIFFAREA 2.673000 ;
    PORT
      LAYER met3 ;
        RECT 0.000 792.920 4.000 793.520 ;
    END
  END core_port_o[166]
  PIN core_port_o[167]
    DIRECTION OUTPUT TRISTATE ;
    USE SIGNAL ;
    ANTENNADIFFAREA 2.673000 ;
    PORT
      LAYER met3 ;
        RECT 0.000 794.280 4.000 794.880 ;
    END
  END core_port_o[167]
  PIN core_port_o[168]
    DIRECTION OUTPUT TRISTATE ;
    USE SIGNAL ;
    ANTENNADIFFAREA 2.673000 ;
    PORT
      LAYER met3 ;
        RECT 0.000 795.640 4.000 796.240 ;
    END
  END core_port_o[168]
  PIN core_port_o[169]
    DIRECTION OUTPUT TRISTATE ;
    USE SIGNAL ;
    ANTENNADIFFAREA 2.673000 ;
    PORT
      LAYER met3 ;
        RECT 0.000 797.000 4.000 797.600 ;
    END
  END core_port_o[169]
  PIN core_port_o[16]
    DIRECTION OUTPUT TRISTATE ;
    USE SIGNAL ;
    ANTENNADIFFAREA 2.673000 ;
    PORT
      LAYER met3 ;
        RECT 0.000 588.920 4.000 589.520 ;
    END
  END core_port_o[16]
  PIN core_port_o[170]
    DIRECTION OUTPUT TRISTATE ;
    USE SIGNAL ;
    ANTENNADIFFAREA 2.673000 ;
    PORT
      LAYER met3 ;
        RECT 0.000 798.360 4.000 798.960 ;
    END
  END core_port_o[170]
  PIN core_port_o[171]
    DIRECTION OUTPUT TRISTATE ;
    USE SIGNAL ;
    ANTENNADIFFAREA 2.673000 ;
    PORT
      LAYER met3 ;
        RECT 0.000 799.720 4.000 800.320 ;
    END
  END core_port_o[171]
  PIN core_port_o[172]
    DIRECTION OUTPUT TRISTATE ;
    USE SIGNAL ;
    ANTENNADIFFAREA 2.673000 ;
    PORT
      LAYER met3 ;
        RECT 0.000 801.080 4.000 801.680 ;
    END
  END core_port_o[172]
  PIN core_port_o[173]
    DIRECTION OUTPUT TRISTATE ;
    USE SIGNAL ;
    ANTENNADIFFAREA 2.673000 ;
    PORT
      LAYER met3 ;
        RECT 0.000 802.440 4.000 803.040 ;
    END
  END core_port_o[173]
  PIN core_port_o[174]
    DIRECTION OUTPUT TRISTATE ;
    USE SIGNAL ;
    ANTENNADIFFAREA 2.673000 ;
    PORT
      LAYER met3 ;
        RECT 0.000 803.800 4.000 804.400 ;
    END
  END core_port_o[174]
  PIN core_port_o[175]
    DIRECTION OUTPUT TRISTATE ;
    USE SIGNAL ;
    ANTENNADIFFAREA 2.673000 ;
    PORT
      LAYER met3 ;
        RECT 0.000 805.160 4.000 805.760 ;
    END
  END core_port_o[175]
  PIN core_port_o[176]
    DIRECTION OUTPUT TRISTATE ;
    USE SIGNAL ;
    ANTENNADIFFAREA 2.673000 ;
    PORT
      LAYER met3 ;
        RECT 0.000 806.520 4.000 807.120 ;
    END
  END core_port_o[176]
  PIN core_port_o[177]
    DIRECTION OUTPUT TRISTATE ;
    USE SIGNAL ;
    ANTENNADIFFAREA 2.673000 ;
    PORT
      LAYER met3 ;
        RECT 0.000 807.880 4.000 808.480 ;
    END
  END core_port_o[177]
  PIN core_port_o[178]
    DIRECTION OUTPUT TRISTATE ;
    USE SIGNAL ;
    ANTENNADIFFAREA 2.673000 ;
    PORT
      LAYER met3 ;
        RECT 0.000 809.240 4.000 809.840 ;
    END
  END core_port_o[178]
  PIN core_port_o[179]
    DIRECTION OUTPUT TRISTATE ;
    USE SIGNAL ;
    ANTENNADIFFAREA 2.673000 ;
    PORT
      LAYER met3 ;
        RECT 0.000 810.600 4.000 811.200 ;
    END
  END core_port_o[179]
  PIN core_port_o[17]
    DIRECTION OUTPUT TRISTATE ;
    USE SIGNAL ;
    ANTENNADIFFAREA 2.673000 ;
    PORT
      LAYER met3 ;
        RECT 0.000 590.280 4.000 590.880 ;
    END
  END core_port_o[17]
  PIN core_port_o[180]
    DIRECTION OUTPUT TRISTATE ;
    USE SIGNAL ;
    ANTENNADIFFAREA 2.673000 ;
    PORT
      LAYER met3 ;
        RECT 0.000 811.960 4.000 812.560 ;
    END
  END core_port_o[180]
  PIN core_port_o[181]
    DIRECTION OUTPUT TRISTATE ;
    USE SIGNAL ;
    ANTENNADIFFAREA 2.673000 ;
    PORT
      LAYER met3 ;
        RECT 0.000 813.320 4.000 813.920 ;
    END
  END core_port_o[181]
  PIN core_port_o[182]
    DIRECTION OUTPUT TRISTATE ;
    USE SIGNAL ;
    ANTENNADIFFAREA 2.673000 ;
    PORT
      LAYER met3 ;
        RECT 0.000 814.680 4.000 815.280 ;
    END
  END core_port_o[182]
  PIN core_port_o[183]
    DIRECTION OUTPUT TRISTATE ;
    USE SIGNAL ;
    ANTENNADIFFAREA 2.673000 ;
    PORT
      LAYER met3 ;
        RECT 0.000 816.040 4.000 816.640 ;
    END
  END core_port_o[183]
  PIN core_port_o[184]
    DIRECTION OUTPUT TRISTATE ;
    USE SIGNAL ;
    ANTENNADIFFAREA 2.673000 ;
    PORT
      LAYER met3 ;
        RECT 0.000 817.400 4.000 818.000 ;
    END
  END core_port_o[184]
  PIN core_port_o[185]
    DIRECTION OUTPUT TRISTATE ;
    USE SIGNAL ;
    ANTENNADIFFAREA 2.673000 ;
    PORT
      LAYER met3 ;
        RECT 0.000 818.760 4.000 819.360 ;
    END
  END core_port_o[185]
  PIN core_port_o[186]
    DIRECTION OUTPUT TRISTATE ;
    USE SIGNAL ;
    ANTENNADIFFAREA 2.673000 ;
    PORT
      LAYER met3 ;
        RECT 0.000 820.120 4.000 820.720 ;
    END
  END core_port_o[186]
  PIN core_port_o[187]
    DIRECTION OUTPUT TRISTATE ;
    USE SIGNAL ;
    ANTENNADIFFAREA 2.673000 ;
    PORT
      LAYER met3 ;
        RECT 0.000 821.480 4.000 822.080 ;
    END
  END core_port_o[187]
  PIN core_port_o[188]
    DIRECTION OUTPUT TRISTATE ;
    USE SIGNAL ;
    ANTENNADIFFAREA 2.673000 ;
    PORT
      LAYER met3 ;
        RECT 0.000 822.840 4.000 823.440 ;
    END
  END core_port_o[188]
  PIN core_port_o[189]
    DIRECTION OUTPUT TRISTATE ;
    USE SIGNAL ;
    ANTENNADIFFAREA 2.673000 ;
    PORT
      LAYER met3 ;
        RECT 0.000 824.200 4.000 824.800 ;
    END
  END core_port_o[189]
  PIN core_port_o[18]
    DIRECTION OUTPUT TRISTATE ;
    USE SIGNAL ;
    ANTENNADIFFAREA 2.673000 ;
    PORT
      LAYER met3 ;
        RECT 0.000 591.640 4.000 592.240 ;
    END
  END core_port_o[18]
  PIN core_port_o[190]
    DIRECTION OUTPUT TRISTATE ;
    USE SIGNAL ;
    ANTENNADIFFAREA 2.673000 ;
    PORT
      LAYER met3 ;
        RECT 0.000 825.560 4.000 826.160 ;
    END
  END core_port_o[190]
  PIN core_port_o[191]
    DIRECTION OUTPUT TRISTATE ;
    USE SIGNAL ;
    ANTENNADIFFAREA 2.673000 ;
    PORT
      LAYER met3 ;
        RECT 0.000 826.920 4.000 827.520 ;
    END
  END core_port_o[191]
  PIN core_port_o[192]
    DIRECTION OUTPUT TRISTATE ;
    USE SIGNAL ;
    ANTENNADIFFAREA 2.673000 ;
    PORT
      LAYER met3 ;
        RECT 0.000 828.280 4.000 828.880 ;
    END
  END core_port_o[192]
  PIN core_port_o[193]
    DIRECTION OUTPUT TRISTATE ;
    USE SIGNAL ;
    ANTENNADIFFAREA 2.673000 ;
    PORT
      LAYER met3 ;
        RECT 0.000 829.640 4.000 830.240 ;
    END
  END core_port_o[193]
  PIN core_port_o[194]
    DIRECTION OUTPUT TRISTATE ;
    USE SIGNAL ;
    ANTENNADIFFAREA 2.673000 ;
    PORT
      LAYER met3 ;
        RECT 0.000 831.000 4.000 831.600 ;
    END
  END core_port_o[194]
  PIN core_port_o[195]
    DIRECTION OUTPUT TRISTATE ;
    USE SIGNAL ;
    ANTENNADIFFAREA 2.673000 ;
    PORT
      LAYER met3 ;
        RECT 0.000 832.360 4.000 832.960 ;
    END
  END core_port_o[195]
  PIN core_port_o[196]
    DIRECTION OUTPUT TRISTATE ;
    USE SIGNAL ;
    ANTENNADIFFAREA 2.673000 ;
    PORT
      LAYER met3 ;
        RECT 0.000 833.720 4.000 834.320 ;
    END
  END core_port_o[196]
  PIN core_port_o[197]
    DIRECTION OUTPUT TRISTATE ;
    USE SIGNAL ;
    ANTENNADIFFAREA 2.673000 ;
    PORT
      LAYER met3 ;
        RECT 0.000 835.080 4.000 835.680 ;
    END
  END core_port_o[197]
  PIN core_port_o[198]
    DIRECTION OUTPUT TRISTATE ;
    USE SIGNAL ;
    ANTENNADIFFAREA 2.673000 ;
    PORT
      LAYER met3 ;
        RECT 0.000 836.440 4.000 837.040 ;
    END
  END core_port_o[198]
  PIN core_port_o[199]
    DIRECTION OUTPUT TRISTATE ;
    USE SIGNAL ;
    ANTENNADIFFAREA 2.673000 ;
    PORT
      LAYER met3 ;
        RECT 0.000 837.800 4.000 838.400 ;
    END
  END core_port_o[199]
  PIN core_port_o[19]
    DIRECTION OUTPUT TRISTATE ;
    USE SIGNAL ;
    ANTENNADIFFAREA 2.673000 ;
    PORT
      LAYER met3 ;
        RECT 0.000 593.000 4.000 593.600 ;
    END
  END core_port_o[19]
  PIN core_port_o[1]
    DIRECTION OUTPUT TRISTATE ;
    USE SIGNAL ;
    ANTENNADIFFAREA 2.673000 ;
    PORT
      LAYER met3 ;
        RECT 0.000 568.520 4.000 569.120 ;
    END
  END core_port_o[1]
  PIN core_port_o[200]
    DIRECTION OUTPUT TRISTATE ;
    USE SIGNAL ;
    ANTENNADIFFAREA 2.673000 ;
    PORT
      LAYER met3 ;
        RECT 0.000 839.160 4.000 839.760 ;
    END
  END core_port_o[200]
  PIN core_port_o[201]
    DIRECTION OUTPUT TRISTATE ;
    USE SIGNAL ;
    ANTENNADIFFAREA 2.673000 ;
    PORT
      LAYER met3 ;
        RECT 0.000 840.520 4.000 841.120 ;
    END
  END core_port_o[201]
  PIN core_port_o[202]
    DIRECTION OUTPUT TRISTATE ;
    USE SIGNAL ;
    ANTENNADIFFAREA 2.673000 ;
    PORT
      LAYER met3 ;
        RECT 0.000 841.880 4.000 842.480 ;
    END
  END core_port_o[202]
  PIN core_port_o[203]
    DIRECTION OUTPUT TRISTATE ;
    USE SIGNAL ;
    ANTENNADIFFAREA 2.673000 ;
    PORT
      LAYER met3 ;
        RECT 0.000 843.240 4.000 843.840 ;
    END
  END core_port_o[203]
  PIN core_port_o[20]
    DIRECTION OUTPUT TRISTATE ;
    USE SIGNAL ;
    ANTENNADIFFAREA 2.673000 ;
    PORT
      LAYER met3 ;
        RECT 0.000 594.360 4.000 594.960 ;
    END
  END core_port_o[20]
  PIN core_port_o[21]
    DIRECTION OUTPUT TRISTATE ;
    USE SIGNAL ;
    ANTENNADIFFAREA 2.673000 ;
    PORT
      LAYER met3 ;
        RECT 0.000 595.720 4.000 596.320 ;
    END
  END core_port_o[21]
  PIN core_port_o[22]
    DIRECTION OUTPUT TRISTATE ;
    USE SIGNAL ;
    ANTENNADIFFAREA 2.673000 ;
    PORT
      LAYER met3 ;
        RECT 0.000 597.080 4.000 597.680 ;
    END
  END core_port_o[22]
  PIN core_port_o[23]
    DIRECTION OUTPUT TRISTATE ;
    USE SIGNAL ;
    ANTENNADIFFAREA 2.673000 ;
    PORT
      LAYER met3 ;
        RECT 0.000 598.440 4.000 599.040 ;
    END
  END core_port_o[23]
  PIN core_port_o[24]
    DIRECTION OUTPUT TRISTATE ;
    USE SIGNAL ;
    ANTENNADIFFAREA 2.673000 ;
    PORT
      LAYER met3 ;
        RECT 0.000 599.800 4.000 600.400 ;
    END
  END core_port_o[24]
  PIN core_port_o[25]
    DIRECTION OUTPUT TRISTATE ;
    USE SIGNAL ;
    ANTENNADIFFAREA 2.673000 ;
    PORT
      LAYER met3 ;
        RECT 0.000 601.160 4.000 601.760 ;
    END
  END core_port_o[25]
  PIN core_port_o[26]
    DIRECTION OUTPUT TRISTATE ;
    USE SIGNAL ;
    ANTENNADIFFAREA 2.673000 ;
    PORT
      LAYER met3 ;
        RECT 0.000 602.520 4.000 603.120 ;
    END
  END core_port_o[26]
  PIN core_port_o[27]
    DIRECTION OUTPUT TRISTATE ;
    USE SIGNAL ;
    ANTENNADIFFAREA 2.673000 ;
    PORT
      LAYER met3 ;
        RECT 0.000 603.880 4.000 604.480 ;
    END
  END core_port_o[27]
  PIN core_port_o[28]
    DIRECTION OUTPUT TRISTATE ;
    USE SIGNAL ;
    ANTENNADIFFAREA 2.673000 ;
    PORT
      LAYER met3 ;
        RECT 0.000 605.240 4.000 605.840 ;
    END
  END core_port_o[28]
  PIN core_port_o[29]
    DIRECTION OUTPUT TRISTATE ;
    USE SIGNAL ;
    ANTENNADIFFAREA 2.673000 ;
    PORT
      LAYER met3 ;
        RECT 0.000 606.600 4.000 607.200 ;
    END
  END core_port_o[29]
  PIN core_port_o[2]
    DIRECTION OUTPUT TRISTATE ;
    USE SIGNAL ;
    ANTENNADIFFAREA 2.673000 ;
    PORT
      LAYER met3 ;
        RECT 0.000 569.880 4.000 570.480 ;
    END
  END core_port_o[2]
  PIN core_port_o[30]
    DIRECTION OUTPUT TRISTATE ;
    USE SIGNAL ;
    ANTENNADIFFAREA 2.673000 ;
    PORT
      LAYER met3 ;
        RECT 0.000 607.960 4.000 608.560 ;
    END
  END core_port_o[30]
  PIN core_port_o[31]
    DIRECTION OUTPUT TRISTATE ;
    USE SIGNAL ;
    ANTENNADIFFAREA 2.673000 ;
    PORT
      LAYER met3 ;
        RECT 0.000 609.320 4.000 609.920 ;
    END
  END core_port_o[31]
  PIN core_port_o[32]
    DIRECTION OUTPUT TRISTATE ;
    USE SIGNAL ;
    ANTENNADIFFAREA 2.673000 ;
    PORT
      LAYER met3 ;
        RECT 0.000 610.680 4.000 611.280 ;
    END
  END core_port_o[32]
  PIN core_port_o[33]
    DIRECTION OUTPUT TRISTATE ;
    USE SIGNAL ;
    ANTENNADIFFAREA 2.673000 ;
    PORT
      LAYER met3 ;
        RECT 0.000 612.040 4.000 612.640 ;
    END
  END core_port_o[33]
  PIN core_port_o[34]
    DIRECTION OUTPUT TRISTATE ;
    USE SIGNAL ;
    ANTENNADIFFAREA 2.673000 ;
    PORT
      LAYER met3 ;
        RECT 0.000 613.400 4.000 614.000 ;
    END
  END core_port_o[34]
  PIN core_port_o[35]
    DIRECTION OUTPUT TRISTATE ;
    USE SIGNAL ;
    ANTENNADIFFAREA 2.673000 ;
    PORT
      LAYER met3 ;
        RECT 0.000 614.760 4.000 615.360 ;
    END
  END core_port_o[35]
  PIN core_port_o[36]
    DIRECTION OUTPUT TRISTATE ;
    USE SIGNAL ;
    ANTENNADIFFAREA 2.673000 ;
    PORT
      LAYER met3 ;
        RECT 0.000 616.120 4.000 616.720 ;
    END
  END core_port_o[36]
  PIN core_port_o[37]
    DIRECTION OUTPUT TRISTATE ;
    USE SIGNAL ;
    ANTENNADIFFAREA 2.673000 ;
    PORT
      LAYER met3 ;
        RECT 0.000 617.480 4.000 618.080 ;
    END
  END core_port_o[37]
  PIN core_port_o[38]
    DIRECTION OUTPUT TRISTATE ;
    USE SIGNAL ;
    ANTENNADIFFAREA 2.673000 ;
    PORT
      LAYER met3 ;
        RECT 0.000 618.840 4.000 619.440 ;
    END
  END core_port_o[38]
  PIN core_port_o[39]
    DIRECTION OUTPUT TRISTATE ;
    USE SIGNAL ;
    ANTENNADIFFAREA 2.673000 ;
    PORT
      LAYER met3 ;
        RECT 0.000 620.200 4.000 620.800 ;
    END
  END core_port_o[39]
  PIN core_port_o[3]
    DIRECTION OUTPUT TRISTATE ;
    USE SIGNAL ;
    ANTENNADIFFAREA 2.673000 ;
    PORT
      LAYER met3 ;
        RECT 0.000 571.240 4.000 571.840 ;
    END
  END core_port_o[3]
  PIN core_port_o[40]
    DIRECTION OUTPUT TRISTATE ;
    USE SIGNAL ;
    ANTENNADIFFAREA 2.673000 ;
    PORT
      LAYER met3 ;
        RECT 0.000 621.560 4.000 622.160 ;
    END
  END core_port_o[40]
  PIN core_port_o[41]
    DIRECTION OUTPUT TRISTATE ;
    USE SIGNAL ;
    ANTENNADIFFAREA 2.673000 ;
    PORT
      LAYER met3 ;
        RECT 0.000 622.920 4.000 623.520 ;
    END
  END core_port_o[41]
  PIN core_port_o[42]
    DIRECTION OUTPUT TRISTATE ;
    USE SIGNAL ;
    ANTENNADIFFAREA 2.673000 ;
    PORT
      LAYER met3 ;
        RECT 0.000 624.280 4.000 624.880 ;
    END
  END core_port_o[42]
  PIN core_port_o[43]
    DIRECTION OUTPUT TRISTATE ;
    USE SIGNAL ;
    ANTENNADIFFAREA 2.673000 ;
    PORT
      LAYER met3 ;
        RECT 0.000 625.640 4.000 626.240 ;
    END
  END core_port_o[43]
  PIN core_port_o[44]
    DIRECTION OUTPUT TRISTATE ;
    USE SIGNAL ;
    ANTENNADIFFAREA 2.673000 ;
    PORT
      LAYER met3 ;
        RECT 0.000 627.000 4.000 627.600 ;
    END
  END core_port_o[44]
  PIN core_port_o[45]
    DIRECTION OUTPUT TRISTATE ;
    USE SIGNAL ;
    ANTENNADIFFAREA 2.673000 ;
    PORT
      LAYER met3 ;
        RECT 0.000 628.360 4.000 628.960 ;
    END
  END core_port_o[45]
  PIN core_port_o[46]
    DIRECTION OUTPUT TRISTATE ;
    USE SIGNAL ;
    ANTENNADIFFAREA 2.673000 ;
    PORT
      LAYER met3 ;
        RECT 0.000 629.720 4.000 630.320 ;
    END
  END core_port_o[46]
  PIN core_port_o[47]
    DIRECTION OUTPUT TRISTATE ;
    USE SIGNAL ;
    ANTENNADIFFAREA 2.673000 ;
    PORT
      LAYER met3 ;
        RECT 0.000 631.080 4.000 631.680 ;
    END
  END core_port_o[47]
  PIN core_port_o[48]
    DIRECTION OUTPUT TRISTATE ;
    USE SIGNAL ;
    ANTENNADIFFAREA 2.673000 ;
    PORT
      LAYER met3 ;
        RECT 0.000 632.440 4.000 633.040 ;
    END
  END core_port_o[48]
  PIN core_port_o[49]
    DIRECTION OUTPUT TRISTATE ;
    USE SIGNAL ;
    ANTENNADIFFAREA 2.673000 ;
    PORT
      LAYER met3 ;
        RECT 0.000 633.800 4.000 634.400 ;
    END
  END core_port_o[49]
  PIN core_port_o[4]
    DIRECTION OUTPUT TRISTATE ;
    USE SIGNAL ;
    ANTENNADIFFAREA 2.673000 ;
    PORT
      LAYER met3 ;
        RECT 0.000 572.600 4.000 573.200 ;
    END
  END core_port_o[4]
  PIN core_port_o[50]
    DIRECTION OUTPUT TRISTATE ;
    USE SIGNAL ;
    ANTENNADIFFAREA 2.673000 ;
    PORT
      LAYER met3 ;
        RECT 0.000 635.160 4.000 635.760 ;
    END
  END core_port_o[50]
  PIN core_port_o[51]
    DIRECTION OUTPUT TRISTATE ;
    USE SIGNAL ;
    ANTENNADIFFAREA 2.673000 ;
    PORT
      LAYER met3 ;
        RECT 0.000 636.520 4.000 637.120 ;
    END
  END core_port_o[51]
  PIN core_port_o[52]
    DIRECTION OUTPUT TRISTATE ;
    USE SIGNAL ;
    ANTENNADIFFAREA 2.673000 ;
    PORT
      LAYER met3 ;
        RECT 0.000 637.880 4.000 638.480 ;
    END
  END core_port_o[52]
  PIN core_port_o[53]
    DIRECTION OUTPUT TRISTATE ;
    USE SIGNAL ;
    ANTENNADIFFAREA 2.673000 ;
    PORT
      LAYER met3 ;
        RECT 0.000 639.240 4.000 639.840 ;
    END
  END core_port_o[53]
  PIN core_port_o[54]
    DIRECTION OUTPUT TRISTATE ;
    USE SIGNAL ;
    ANTENNADIFFAREA 2.673000 ;
    PORT
      LAYER met3 ;
        RECT 0.000 640.600 4.000 641.200 ;
    END
  END core_port_o[54]
  PIN core_port_o[55]
    DIRECTION OUTPUT TRISTATE ;
    USE SIGNAL ;
    ANTENNADIFFAREA 2.673000 ;
    PORT
      LAYER met3 ;
        RECT 0.000 641.960 4.000 642.560 ;
    END
  END core_port_o[55]
  PIN core_port_o[56]
    DIRECTION OUTPUT TRISTATE ;
    USE SIGNAL ;
    ANTENNADIFFAREA 2.673000 ;
    PORT
      LAYER met3 ;
        RECT 0.000 643.320 4.000 643.920 ;
    END
  END core_port_o[56]
  PIN core_port_o[57]
    DIRECTION OUTPUT TRISTATE ;
    USE SIGNAL ;
    ANTENNADIFFAREA 2.673000 ;
    PORT
      LAYER met3 ;
        RECT 0.000 644.680 4.000 645.280 ;
    END
  END core_port_o[57]
  PIN core_port_o[58]
    DIRECTION OUTPUT TRISTATE ;
    USE SIGNAL ;
    ANTENNADIFFAREA 2.673000 ;
    PORT
      LAYER met3 ;
        RECT 0.000 646.040 4.000 646.640 ;
    END
  END core_port_o[58]
  PIN core_port_o[59]
    DIRECTION OUTPUT TRISTATE ;
    USE SIGNAL ;
    ANTENNADIFFAREA 2.673000 ;
    PORT
      LAYER met3 ;
        RECT 0.000 647.400 4.000 648.000 ;
    END
  END core_port_o[59]
  PIN core_port_o[5]
    DIRECTION OUTPUT TRISTATE ;
    USE SIGNAL ;
    ANTENNADIFFAREA 2.673000 ;
    PORT
      LAYER met3 ;
        RECT 0.000 573.960 4.000 574.560 ;
    END
  END core_port_o[5]
  PIN core_port_o[60]
    DIRECTION OUTPUT TRISTATE ;
    USE SIGNAL ;
    ANTENNADIFFAREA 2.673000 ;
    PORT
      LAYER met3 ;
        RECT 0.000 648.760 4.000 649.360 ;
    END
  END core_port_o[60]
  PIN core_port_o[61]
    DIRECTION OUTPUT TRISTATE ;
    USE SIGNAL ;
    ANTENNADIFFAREA 2.673000 ;
    PORT
      LAYER met3 ;
        RECT 0.000 650.120 4.000 650.720 ;
    END
  END core_port_o[61]
  PIN core_port_o[62]
    DIRECTION OUTPUT TRISTATE ;
    USE SIGNAL ;
    ANTENNADIFFAREA 2.673000 ;
    PORT
      LAYER met3 ;
        RECT 0.000 651.480 4.000 652.080 ;
    END
  END core_port_o[62]
  PIN core_port_o[63]
    DIRECTION OUTPUT TRISTATE ;
    USE SIGNAL ;
    ANTENNADIFFAREA 2.673000 ;
    PORT
      LAYER met3 ;
        RECT 0.000 652.840 4.000 653.440 ;
    END
  END core_port_o[63]
  PIN core_port_o[64]
    DIRECTION OUTPUT TRISTATE ;
    USE SIGNAL ;
    ANTENNADIFFAREA 2.673000 ;
    PORT
      LAYER met3 ;
        RECT 0.000 654.200 4.000 654.800 ;
    END
  END core_port_o[64]
  PIN core_port_o[65]
    DIRECTION OUTPUT TRISTATE ;
    USE SIGNAL ;
    ANTENNADIFFAREA 2.673000 ;
    PORT
      LAYER met3 ;
        RECT 0.000 655.560 4.000 656.160 ;
    END
  END core_port_o[65]
  PIN core_port_o[66]
    DIRECTION OUTPUT TRISTATE ;
    USE SIGNAL ;
    ANTENNADIFFAREA 2.673000 ;
    PORT
      LAYER met3 ;
        RECT 0.000 656.920 4.000 657.520 ;
    END
  END core_port_o[66]
  PIN core_port_o[67]
    DIRECTION OUTPUT TRISTATE ;
    USE SIGNAL ;
    ANTENNADIFFAREA 2.673000 ;
    PORT
      LAYER met3 ;
        RECT 0.000 658.280 4.000 658.880 ;
    END
  END core_port_o[67]
  PIN core_port_o[68]
    DIRECTION OUTPUT TRISTATE ;
    USE SIGNAL ;
    ANTENNADIFFAREA 2.673000 ;
    PORT
      LAYER met3 ;
        RECT 0.000 659.640 4.000 660.240 ;
    END
  END core_port_o[68]
  PIN core_port_o[69]
    DIRECTION OUTPUT TRISTATE ;
    USE SIGNAL ;
    ANTENNADIFFAREA 2.673000 ;
    PORT
      LAYER met3 ;
        RECT 0.000 661.000 4.000 661.600 ;
    END
  END core_port_o[69]
  PIN core_port_o[6]
    DIRECTION OUTPUT TRISTATE ;
    USE SIGNAL ;
    ANTENNADIFFAREA 2.673000 ;
    PORT
      LAYER met3 ;
        RECT 0.000 575.320 4.000 575.920 ;
    END
  END core_port_o[6]
  PIN core_port_o[70]
    DIRECTION OUTPUT TRISTATE ;
    USE SIGNAL ;
    ANTENNADIFFAREA 2.673000 ;
    PORT
      LAYER met3 ;
        RECT 0.000 662.360 4.000 662.960 ;
    END
  END core_port_o[70]
  PIN core_port_o[71]
    DIRECTION OUTPUT TRISTATE ;
    USE SIGNAL ;
    ANTENNADIFFAREA 2.673000 ;
    PORT
      LAYER met3 ;
        RECT 0.000 663.720 4.000 664.320 ;
    END
  END core_port_o[71]
  PIN core_port_o[72]
    DIRECTION OUTPUT TRISTATE ;
    USE SIGNAL ;
    ANTENNADIFFAREA 2.673000 ;
    PORT
      LAYER met3 ;
        RECT 0.000 665.080 4.000 665.680 ;
    END
  END core_port_o[72]
  PIN core_port_o[73]
    DIRECTION OUTPUT TRISTATE ;
    USE SIGNAL ;
    ANTENNADIFFAREA 2.673000 ;
    PORT
      LAYER met3 ;
        RECT 0.000 666.440 4.000 667.040 ;
    END
  END core_port_o[73]
  PIN core_port_o[74]
    DIRECTION OUTPUT TRISTATE ;
    USE SIGNAL ;
    ANTENNADIFFAREA 2.673000 ;
    PORT
      LAYER met3 ;
        RECT 0.000 667.800 4.000 668.400 ;
    END
  END core_port_o[74]
  PIN core_port_o[75]
    DIRECTION OUTPUT TRISTATE ;
    USE SIGNAL ;
    ANTENNADIFFAREA 2.673000 ;
    PORT
      LAYER met3 ;
        RECT 0.000 669.160 4.000 669.760 ;
    END
  END core_port_o[75]
  PIN core_port_o[76]
    DIRECTION OUTPUT TRISTATE ;
    USE SIGNAL ;
    ANTENNADIFFAREA 2.673000 ;
    PORT
      LAYER met3 ;
        RECT 0.000 670.520 4.000 671.120 ;
    END
  END core_port_o[76]
  PIN core_port_o[77]
    DIRECTION OUTPUT TRISTATE ;
    USE SIGNAL ;
    ANTENNADIFFAREA 2.673000 ;
    PORT
      LAYER met3 ;
        RECT 0.000 671.880 4.000 672.480 ;
    END
  END core_port_o[77]
  PIN core_port_o[78]
    DIRECTION OUTPUT TRISTATE ;
    USE SIGNAL ;
    ANTENNADIFFAREA 2.673000 ;
    PORT
      LAYER met3 ;
        RECT 0.000 673.240 4.000 673.840 ;
    END
  END core_port_o[78]
  PIN core_port_o[79]
    DIRECTION OUTPUT TRISTATE ;
    USE SIGNAL ;
    ANTENNADIFFAREA 2.673000 ;
    PORT
      LAYER met3 ;
        RECT 0.000 674.600 4.000 675.200 ;
    END
  END core_port_o[79]
  PIN core_port_o[7]
    DIRECTION OUTPUT TRISTATE ;
    USE SIGNAL ;
    ANTENNADIFFAREA 2.673000 ;
    PORT
      LAYER met3 ;
        RECT 0.000 576.680 4.000 577.280 ;
    END
  END core_port_o[7]
  PIN core_port_o[80]
    DIRECTION OUTPUT TRISTATE ;
    USE SIGNAL ;
    ANTENNADIFFAREA 2.673000 ;
    PORT
      LAYER met3 ;
        RECT 0.000 675.960 4.000 676.560 ;
    END
  END core_port_o[80]
  PIN core_port_o[81]
    DIRECTION OUTPUT TRISTATE ;
    USE SIGNAL ;
    ANTENNADIFFAREA 2.673000 ;
    PORT
      LAYER met3 ;
        RECT 0.000 677.320 4.000 677.920 ;
    END
  END core_port_o[81]
  PIN core_port_o[82]
    DIRECTION OUTPUT TRISTATE ;
    USE SIGNAL ;
    ANTENNADIFFAREA 2.673000 ;
    PORT
      LAYER met3 ;
        RECT 0.000 678.680 4.000 679.280 ;
    END
  END core_port_o[82]
  PIN core_port_o[83]
    DIRECTION OUTPUT TRISTATE ;
    USE SIGNAL ;
    ANTENNADIFFAREA 2.673000 ;
    PORT
      LAYER met3 ;
        RECT 0.000 680.040 4.000 680.640 ;
    END
  END core_port_o[83]
  PIN core_port_o[84]
    DIRECTION OUTPUT TRISTATE ;
    USE SIGNAL ;
    ANTENNADIFFAREA 2.673000 ;
    PORT
      LAYER met3 ;
        RECT 0.000 681.400 4.000 682.000 ;
    END
  END core_port_o[84]
  PIN core_port_o[85]
    DIRECTION OUTPUT TRISTATE ;
    USE SIGNAL ;
    ANTENNADIFFAREA 2.673000 ;
    PORT
      LAYER met3 ;
        RECT 0.000 682.760 4.000 683.360 ;
    END
  END core_port_o[85]
  PIN core_port_o[86]
    DIRECTION OUTPUT TRISTATE ;
    USE SIGNAL ;
    ANTENNADIFFAREA 2.673000 ;
    PORT
      LAYER met3 ;
        RECT 0.000 684.120 4.000 684.720 ;
    END
  END core_port_o[86]
  PIN core_port_o[87]
    DIRECTION OUTPUT TRISTATE ;
    USE SIGNAL ;
    ANTENNADIFFAREA 2.673000 ;
    PORT
      LAYER met3 ;
        RECT 0.000 685.480 4.000 686.080 ;
    END
  END core_port_o[87]
  PIN core_port_o[88]
    DIRECTION OUTPUT TRISTATE ;
    USE SIGNAL ;
    ANTENNADIFFAREA 2.673000 ;
    PORT
      LAYER met3 ;
        RECT 0.000 686.840 4.000 687.440 ;
    END
  END core_port_o[88]
  PIN core_port_o[89]
    DIRECTION OUTPUT TRISTATE ;
    USE SIGNAL ;
    ANTENNADIFFAREA 2.673000 ;
    PORT
      LAYER met3 ;
        RECT 0.000 688.200 4.000 688.800 ;
    END
  END core_port_o[89]
  PIN core_port_o[8]
    DIRECTION OUTPUT TRISTATE ;
    USE SIGNAL ;
    ANTENNADIFFAREA 2.673000 ;
    PORT
      LAYER met3 ;
        RECT 0.000 578.040 4.000 578.640 ;
    END
  END core_port_o[8]
  PIN core_port_o[90]
    DIRECTION OUTPUT TRISTATE ;
    USE SIGNAL ;
    ANTENNADIFFAREA 2.673000 ;
    PORT
      LAYER met3 ;
        RECT 0.000 689.560 4.000 690.160 ;
    END
  END core_port_o[90]
  PIN core_port_o[91]
    DIRECTION OUTPUT TRISTATE ;
    USE SIGNAL ;
    ANTENNADIFFAREA 2.673000 ;
    PORT
      LAYER met3 ;
        RECT 0.000 690.920 4.000 691.520 ;
    END
  END core_port_o[91]
  PIN core_port_o[92]
    DIRECTION OUTPUT TRISTATE ;
    USE SIGNAL ;
    ANTENNADIFFAREA 2.673000 ;
    PORT
      LAYER met3 ;
        RECT 0.000 692.280 4.000 692.880 ;
    END
  END core_port_o[92]
  PIN core_port_o[93]
    DIRECTION OUTPUT TRISTATE ;
    USE SIGNAL ;
    ANTENNADIFFAREA 2.673000 ;
    PORT
      LAYER met3 ;
        RECT 0.000 693.640 4.000 694.240 ;
    END
  END core_port_o[93]
  PIN core_port_o[94]
    DIRECTION OUTPUT TRISTATE ;
    USE SIGNAL ;
    ANTENNADIFFAREA 2.673000 ;
    PORT
      LAYER met3 ;
        RECT 0.000 695.000 4.000 695.600 ;
    END
  END core_port_o[94]
  PIN core_port_o[95]
    DIRECTION OUTPUT TRISTATE ;
    USE SIGNAL ;
    ANTENNADIFFAREA 2.673000 ;
    PORT
      LAYER met3 ;
        RECT 0.000 696.360 4.000 696.960 ;
    END
  END core_port_o[95]
  PIN core_port_o[96]
    DIRECTION OUTPUT TRISTATE ;
    USE SIGNAL ;
    ANTENNADIFFAREA 2.673000 ;
    PORT
      LAYER met3 ;
        RECT 0.000 697.720 4.000 698.320 ;
    END
  END core_port_o[96]
  PIN core_port_o[97]
    DIRECTION OUTPUT TRISTATE ;
    USE SIGNAL ;
    ANTENNADIFFAREA 2.673000 ;
    PORT
      LAYER met3 ;
        RECT 0.000 699.080 4.000 699.680 ;
    END
  END core_port_o[97]
  PIN core_port_o[98]
    DIRECTION OUTPUT TRISTATE ;
    USE SIGNAL ;
    ANTENNADIFFAREA 2.673000 ;
    PORT
      LAYER met3 ;
        RECT 0.000 700.440 4.000 701.040 ;
    END
  END core_port_o[98]
  PIN core_port_o[99]
    DIRECTION OUTPUT TRISTATE ;
    USE SIGNAL ;
    ANTENNADIFFAREA 2.673000 ;
    PORT
      LAYER met3 ;
        RECT 0.000 701.800 4.000 702.400 ;
    END
  END core_port_o[99]
  PIN core_port_o[9]
    DIRECTION OUTPUT TRISTATE ;
    USE SIGNAL ;
    ANTENNADIFFAREA 2.673000 ;
    PORT
      LAYER met3 ;
        RECT 0.000 579.400 4.000 580.000 ;
    END
  END core_port_o[9]
  PIN vccd1
    DIRECTION INOUT ;
    USE POWER ;
    PORT
      LAYER met4 ;
        RECT 21.040 10.640 22.640 838.000 ;
    END
    PORT
      LAYER met4 ;
        RECT 174.640 10.640 176.240 838.000 ;
    END
    PORT
      LAYER met4 ;
        RECT 328.240 10.640 329.840 838.000 ;
    END
    PORT
      LAYER met4 ;
        RECT 481.840 10.640 483.440 838.000 ;
    END
    PORT
      LAYER met4 ;
        RECT 635.440 10.640 637.040 838.000 ;
    END
    PORT
      LAYER met4 ;
        RECT 789.040 10.640 790.640 838.000 ;
    END
  END vccd1
  PIN vssd1
    DIRECTION INOUT ;
    USE GROUND ;
    PORT
      LAYER met4 ;
        RECT 97.840 10.640 99.440 838.000 ;
    END
    PORT
      LAYER met4 ;
        RECT 251.440 10.640 253.040 838.000 ;
    END
    PORT
      LAYER met4 ;
        RECT 405.040 10.640 406.640 838.000 ;
    END
    PORT
      LAYER met4 ;
        RECT 558.640 10.640 560.240 838.000 ;
    END
    PORT
      LAYER met4 ;
        RECT 712.240 10.640 713.840 838.000 ;
    END
  END vssd1
  OBS
      LAYER li1 ;
        RECT 5.520 10.795 843.180 837.845 ;
      LAYER met1 ;
        RECT 4.670 9.900 843.180 842.140 ;
      LAYER met2 ;
        RECT 4.690 4.235 843.090 843.725 ;
      LAYER met3 ;
        RECT 4.400 4.255 844.600 843.705 ;
      LAYER met4 ;
        RECT 350.815 53.215 404.640 834.185 ;
        RECT 407.040 53.215 481.440 834.185 ;
        RECT 483.840 53.215 558.240 834.185 ;
        RECT 560.640 53.215 635.040 834.185 ;
        RECT 637.440 53.215 711.840 834.185 ;
        RECT 714.240 53.215 788.640 834.185 ;
        RECT 791.040 53.215 837.825 834.185 ;
  END
END address_coalescer_m
END LIBRARY

